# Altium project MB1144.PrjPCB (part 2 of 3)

## Sheet MCU2.SchDoc: MCU2
size A3; DocumentNumber: MB1144; Revision: C-02; SheetNumber: 4; SheetTotal: 25; PageSetup: Record=PageOptions|CenterHorizontal=True|CenterVertical=True|PrintScale=1.04|XCorrection=1.00|YCorrection=1.00|PrintKind=1|BorderSize=5000000|LeftOffset=0|BottomOffset=0|Orientation=2|PaperLength=1000|PaperWidth=1000|Scale=100|PaperSource=7|PrintQuality=600|MediaType=1|DitherType=10|PaperKind=A3|PrintScaleMode=1; Project: STM32L476G-EVAL

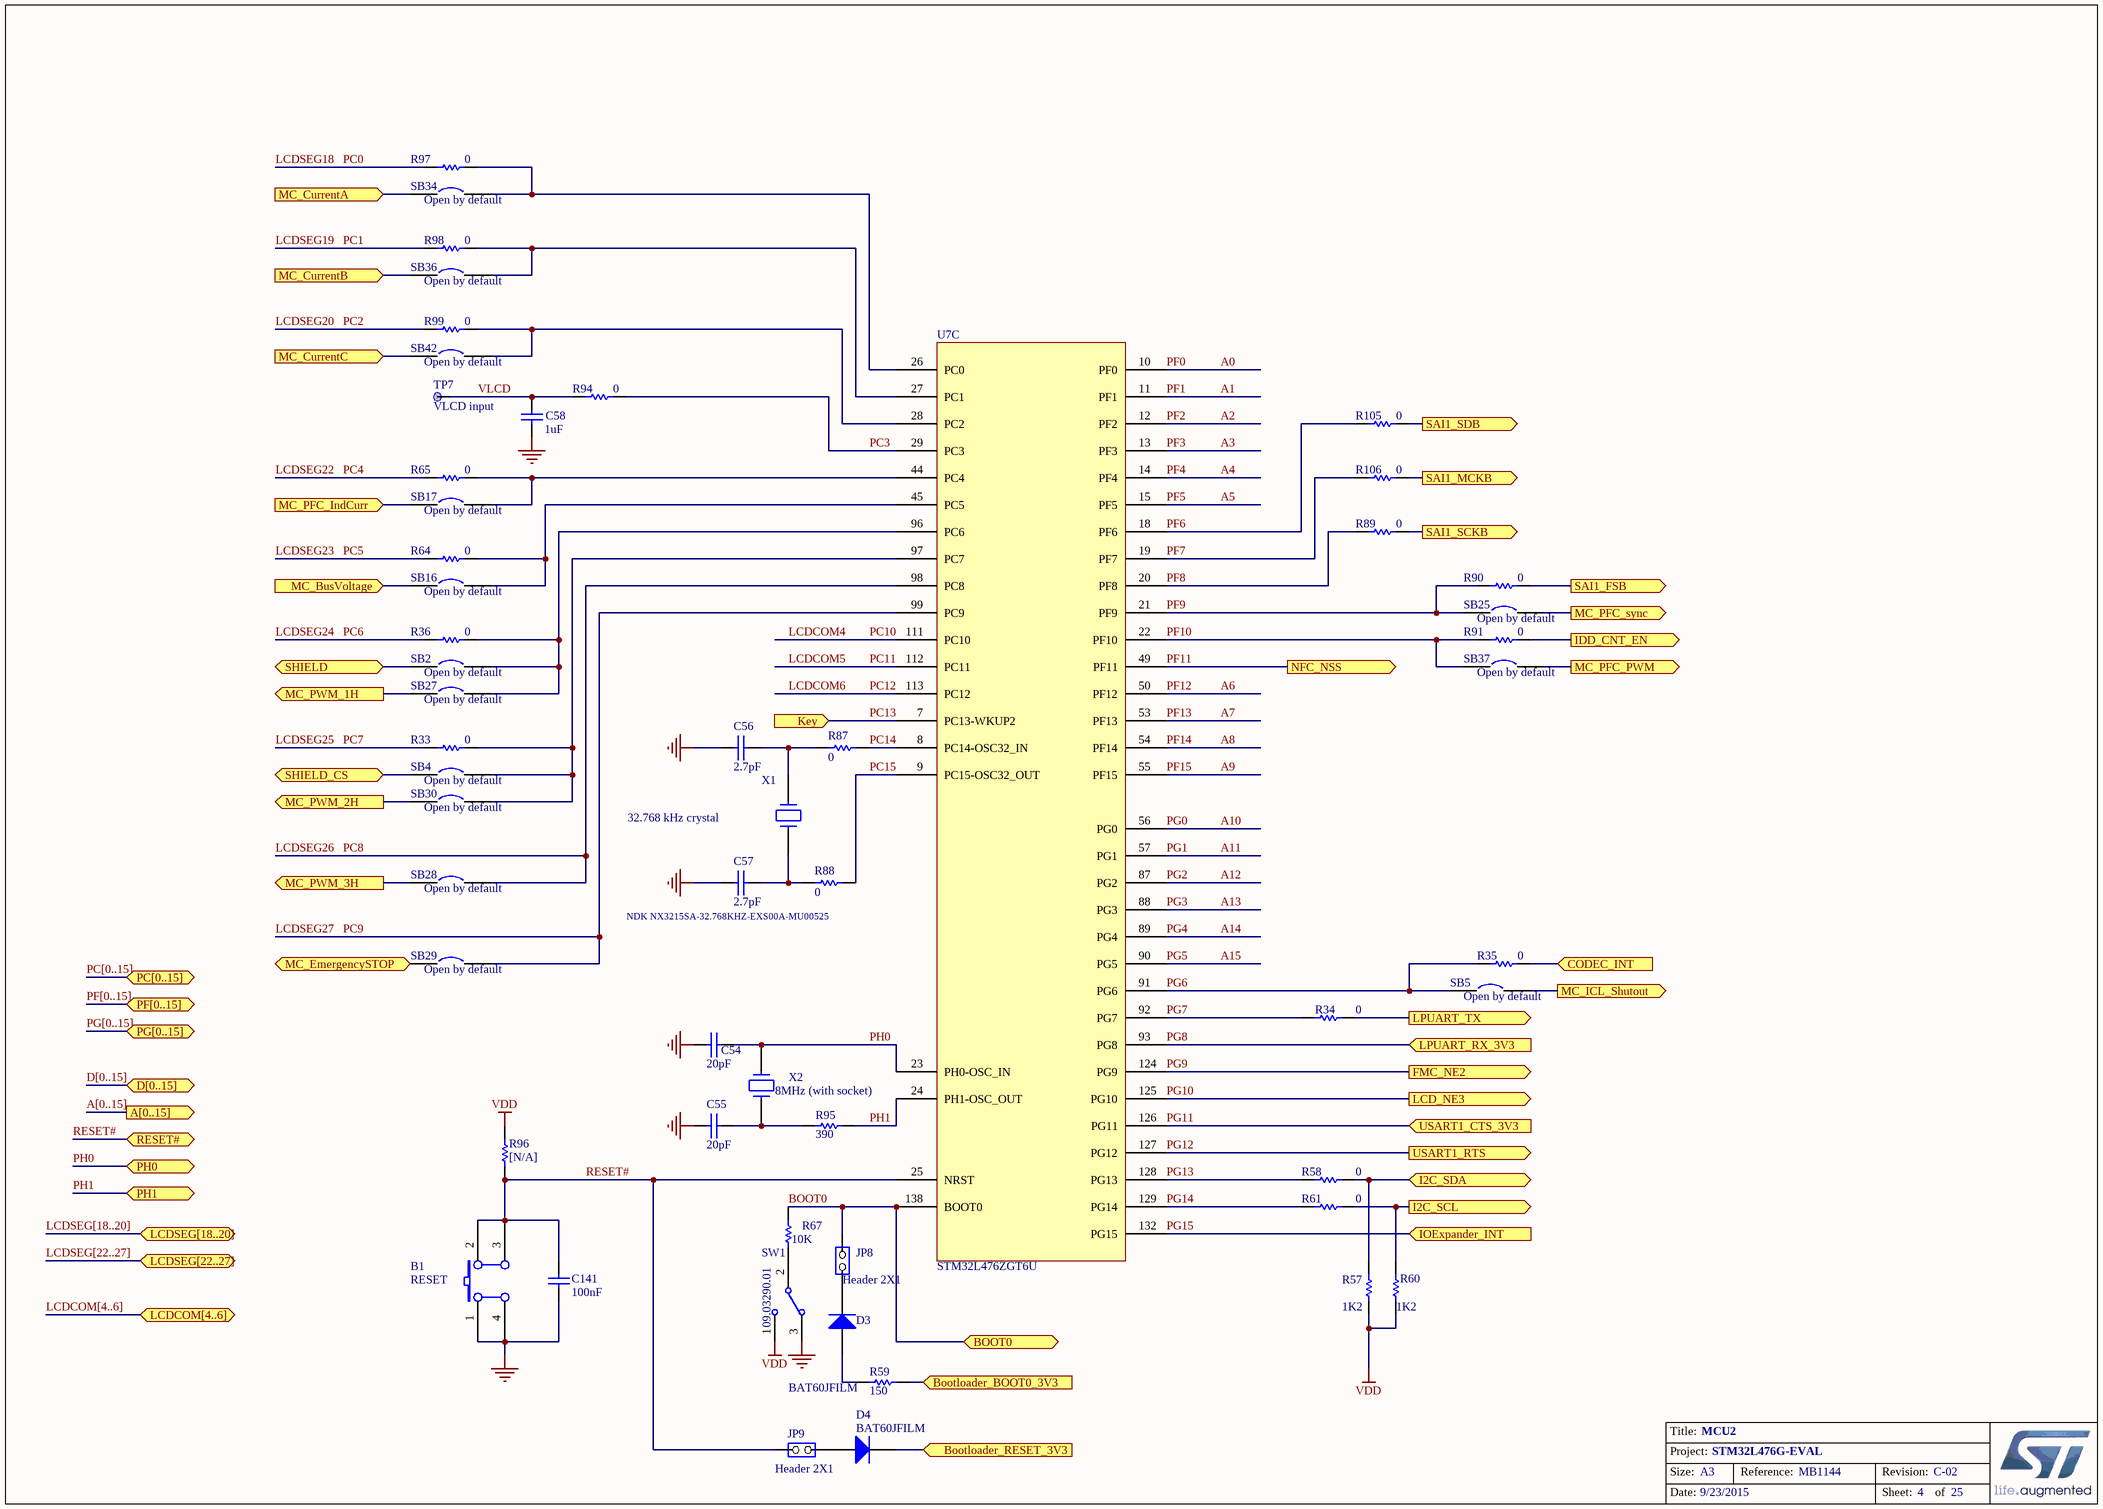
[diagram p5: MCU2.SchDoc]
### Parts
B1  RESET  [PB10]
C54  20pF  [0402R]
C55  20pF  [0402R]
C56  2.7pF  [0603C]
C57  2.7pF  [0603C]
C58  1uF  [0603C]
C141  100nF  [0402C]
D3  BAT60JFILM  [SOD-323]
D4  BAT60JFILM  [SOD-323]
JP8  Header 2X1  [SIP2]
JP9  Header 2X1  [SIP2]
R33  0  [SB_0603]
R34  0  [0603R]
R35  0  [SB_0603]
R36  0  [SB_0603]
R57  1K2  [0402R]
R58  0  [0603R]
R59  150  [0402R]
R60  1K2  [0402R]
R61  0  [0603R]
R64  0  [SB_0603]
R65  0  [SB_0603]
R67  10K  [0402R]
R87  0  [0603R]
R88  0  [0603R]
R89  0  [0603R]
R90  0  [SB_0603]
R91  0  [SB_0603]
R94  0  [0603R]
R95  390  [0603R]
R96  [N/A]  [0603R]
R97  0  [SB_0603]
R98  0  [SB_0603]
R99  0  [SB_0603]
R105  0  [0603R]
R106  0  [0603R]
SB2  Open by default  [SB_0603]
SB4  Open by default  [SB_0603]
SB5  Open by default  [SB_0603]
SB16  Open by default  [SB_0603]
SB17  Open by default  [SB_0603]
SB25  Open by default  [SB_0603]
SB27  Open by default  [SB_0603]
SB28  Open by default  [SB_0603]
SB29  Open by default  [SB_0603]
SB30  Open by default  [SB_0603]
SB34  Open by default  [SB_0603]
SB36  Open by default  [SB_0603]
SB37  Open by default  [SB_0603]
SB42  Open by default  [SB_0603]
SW1  09.03290.01  [SW1_3TH_2R54_10X2R5]
TP7  TP Name: VLCD input  [TP]  (hidden comment: [N/A])
U7  STM32L476ZGT6U  [TQFP144_0R5_22X22_SOCKET]  (part C of 3)
X1  NDK NX3215SA-32.768KHZ-EXS00A-MU00525  [XTAL_2SM_3R2X1R5]
X2  8MHz (with socket)  [XTAL_SOCKET]

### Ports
A[0..15] (out), BOOT0, Bootloader_BOOT0_3V3 (in), Bootloader_RESET_3V3 (in), CODEC_INT (in), D[0..15] (bidir), FMC_NE2 (out), I2C_SCL (out), I2C_SDA (bidir), IDD_CNT_EN (out), IOExpander_INT (in), Key (in), LCD_NE3 (out), LCDCOM[4..6] (bidir), LCDSEG[18..20] (bidir), LCDSEG[22..27] (bidir), LPUART_RX_3V3 (in), LPUART_TX (out), MC_BusVoltage (in), MC_CurrentA (in), MC_CurrentB (in), MC_CurrentC (in), MC_EmergencySTOP (in), MC_ICL_Shutout (out), MC_PFC_IndCurr (in), MC_PFC_PWM (out), MC_PFC_sync (out), MC_PWM_1H (out), MC_PWM_2H (out), MC_PWM_3H (out), NFC_NSS (out), PC[0..15] (bidir), PF[0..15] (bidir), PG[0..15] (bidir), PH0, PH1, RESET# (bidir), SAI1_FSB (out), SAI1_MCKB (out), SAI1_SCKB (out), SAI1_SDB (out), SHIELD, SHIELD_CS, USART1_CTS_3V3 (in), USART1_RTS (out)

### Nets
GND: B1.1(A0) B1.4(A1) C54.2 C55.2 C56.2 C57.2 C58.1 C141.1 SW1.3
VDD: R57.2 R60.2 R96.2 SW1.1
A0: U7.10(PF0)  [also labelled PF0]
A1: U7.11(PF1)  [also labelled PF1]
A2: U7.12(PF2)  [also labelled PF2]
A3: U7.13(PF3)  [also labelled PF3]
A4: U7.14(PF4)  [also labelled PF4]
A5: U7.15(PF5)  [also labelled PF5]
A6: U7.50(PF12)  [also labelled PF12]
A7: U7.53(PF13)  [also labelled PF13]
A8: U7.54(PF14)  [also labelled PF14]
A9: U7.55(PF15)  [also labelled PF15]
A10: U7.56(PG0)  [also labelled PG0]
A11: U7.57(PG1)  [also labelled PG1]
A12: U7.87(PG2)  [also labelled PG2]
A13: U7.88(PG3)  [also labelled PG3]
A14: U7.89(PG4)  [also labelled PG4]
A15: U7.90(PG5)  [also labelled PG5]
BOOT0: JP8.1(COMMON) R67.1 U7.138(BOOT0) ; port BOOT0
I2C_SCL: R60.1 R61.1 ; port I2C_SCL
I2C_SDA: R57.1 R58.1 ; port I2C_SDA
LCDCOM4: U7.111(PC10)  [also labelled PC10]
LCDCOM5: U7.112(PC11)  [also labelled PC11]
LCDCOM6: U7.113(PC12)  [also labelled PC12]
LCDSEG18: R97.1  [also labelled PC0]
LCDSEG19: R98.1  [also labelled PC1]
LCDSEG20: R99.1  [also labelled PC2]
LCDSEG22: R65.1  [also labelled PC4]
LCDSEG23: R64.1  [also labelled PC5]
LCDSEG24: R36.1  [also labelled PC6]
LCDSEG25: R33.1  [also labelled PC7]
LCDSEG26: SB28.2 U7.98(PC8)  [also labelled PC8]
LCDSEG27: SB29.2 U7.99(PC9)  [also labelled PC9]
PC3: R94.1 U7.29(PC3)
PC13: U7.7(PC13-WKUP2) ; port Key
PC14: R87.2 U7.8(PC14-OSC32_IN)
PC15: R88.2 U7.9(PC15-OSC32_OUT)
PF6: R105.2 U7.18(PF6)
PF7: R106.2 U7.19(PF7)
PF8: R89.2 U7.20(PF8)
PF9: R90.2 SB25.1 U7.21(PF9)
PF10: R91.2 SB37.1 U7.22(PF10)
PF11: U7.49(PF11) ; port NFC_NSS
PG6: R35.2 SB5.1 U7.91(PG6)
PG7: R34.2 U7.92(PG7)
PG8: U7.93(PG8) ; port LPUART_RX_3V3
PG9: U7.124(PG9) ; port FMC_NE2
PG10: U7.125(PG10) ; port LCD_NE3  [project net LCD_NE3]
PG11: U7.126(PG11) ; port USART1_CTS_3V3
PG12: U7.127(PG12) ; port USART1_RTS
PG13: R58.2 U7.128(PG13)
PG14: R61.2 U7.129(PG14)
PG15: U7.132(PG15) ; port IOExpander_INT
PH0: C54.1 U7.23(PH0-OSC_IN) X2.2 ; port PH0
PH1: R95.1 U7.24(PH1-OSC_OUT) ; port PH1
RESET#: B1.2(B0) B1.3(B1) C141.2 JP9.1(COMMON) R96.1 U7.25(NRST) ; port RESET#
VLCD: C58.2 R94.2 TP7.1
NetC3_1: SB17.1 ; port MC_PFC_IndCurr
NetC7_2: SB29.1 ; port MC_EmergencySTOP
NetC9_2: SB37.2 ; port MC_PFC_PWM
NetC10_2: SB42.1 ; port MC_CurrentC
NetC11_1: SB16.1 ; port MC_BusVoltage
NetC13_2: SB36.1 ; port MC_CurrentB
NetC14_2: SB34.1 ; port MC_CurrentA
NetC16_2: SB25.2 ; port MC_PFC_sync
NetC34_2: SB4.1 ; port SHIELD_CS
NetC55_1: C55.1 R95.2 X2.1
NetC56_1: C56.1 R87.1 X1.2
NetC57_1: C57.1 R88.1 X1.1
NetCN2_3: SB27.1 ; port MC_PWM_1H
NetCN2_7: SB30.1 ; port MC_PWM_2H
NetCN2_11: SB28.1 ; port MC_PWM_3H
NetCN2_21: SB5.2 ; port MC_ICL_Shutout
NetD3_1: D3.1(A) R59.1
NetD3_2: D3.2(K) JP8.2(NO)
NetD4_1: D4.1(A) JP9.2(NO)
NetD4_2: D4.2(K) ; port Bootloader_RESET_3V3
NetR33_2: R33.2 SB4.2 SB30.2 U7.97(PC7)
NetR34_1: R34.1 ; port LPUART_TX
NetR35_1: R35.1 ; port CODEC_INT
NetR36_2: R36.2 SB2.2 SB27.2 U7.96(PC6)
NetR37_1: SB2.1 ; port SHIELD
NetR59_2: R59.2 ; port Bootloader_BOOT0_3V3
NetR64_2: R64.2 SB16.2 U7.45(PC5)
NetR65_2: R65.2 SB17.2 U7.44(PC4)
NetR67_2: R67.2 SW1.2
NetR89_1: R89.1 ; port SAI1_SCKB
NetR90_1: R90.1 ; port SAI1_FSB
NetR91_1: R91.1 ; port IDD_CNT_EN
NetR97_2: R97.2 SB34.2 U7.26(PC0)
NetR98_2: R98.2 SB36.2 U7.27(PC1)
NetR99_2: R99.2 SB42.2 U7.28(PC2)
NetR105_1: R105.1 ; port SAI1_SDB
NetR106_1: R106.1 ; port SAI1_MCKB

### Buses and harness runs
bus A[0..15] = port A[0..15]
bus D[0..15] = port D[0..15]
bus LCDCOM[4..6] = port LCDCOM[4..6]
bus LCDSEG[18..20] = port LCDSEG[18..20]
bus LCDSEG[22..27] = port LCDSEG[22..27]
bus PC[0..15] = port PC[0..15]
bus PF[0..15] = port PF[0..15]
bus PG[0..15] = port PG[0..15]

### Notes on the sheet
- 32.768 kHz crystal

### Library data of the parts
B1 = SW PUSHBUTTON: SE PUSHBUTTON; Ordered by: Subcon; Comments: no comment; Assembly: Black; ECCN_US/EU: NA
C54-C57 = CAP: Capacitor; Ordered by: Subcon; ECCN_US/EU: NA
C58 = CAP: Capacitor; Value: 100nF; Ordered by: Subcon; ECCN_US/EU: NA
C141 = CAP: Capacitor; Value: 100pF; Ordered by: Subcon; ECCN_US/EU: NA
D3 D4 = Diode: Default Diode; Code - JEDEC: DO-214-AB; Ordered by: ST; ECCN_US/EU: EAR99/NEC; Ref St: 9151097
JP8 JP9 = JP2: Ordered by: Subcon; ECCN_US/EU: NA
R33 R34 R36 R57 R58 R60 R61 R64 R65 R87 R88 R95 R97-R99 = Res1: Resistor; Value: 1K; Ordered by: Subcon; ECCN_US/EU: NA
R35 R59 R67 R89-R91 R94 R105 R106 = res1: Resistor; Value: 1K; Ordered by: Subcon; ECCN_US/EU: NA
R96 = res1: Resistor; Value: 1K; Ordered by: Subcon; ECCN_US/EU: NA; Fitted: NO
SB2 SB4 SB5 SB16 SB17 SB25 SB27-SB30 SB34 SB36 SB37 SB42 = Circuit Breaker: Ordered by: Subcon; Comments: Solder bridge; Fitted: NO; ECCN_US/EU: NA
SW1 = SW-SPDT: SPDT Subminiature Toggle Switch, Right Angle Mounting, Vertical Actuation; Revision 1: Jul-2002: Re-released for DXP Platform.; Revision 2: 17-Dec-2003: Schematic revised, PCB Footprint replaced.; Ordered by: Subcon; ECCN_US/EU: NA
TP7 = TP: Ordered by: Subcon; Fitted or not fitted: NO; ECCN_US/EU: NA; Fitted: NO
U7 = STM32L476_TQFP144: Manuf_Part_1: STM32L476ZGT6U cut1.3; Ordered by: ST; ECCN_US/EU: 3A991A2/NEC; Assembly: MCU; Ref St: 9175195
X1 = CRYSTAL_32K: Crystal; Ordered by: ST; ECCN_US/EU: NA
X2 = CRYSTAL: Manuf_1: jfvny; Manuf_Part_1: HC-49S-C16QSA-8M; Ordered by: Subcon; ECCN_US/EU: NA

## Sheet SRAM&Flash.SchDoc: SRAM&Flash
size A3; DocumentNumber: MB1144; Revision: C-02; SheetNumber: 10; SheetTotal: 25; Project: STM32L476G-EVAL

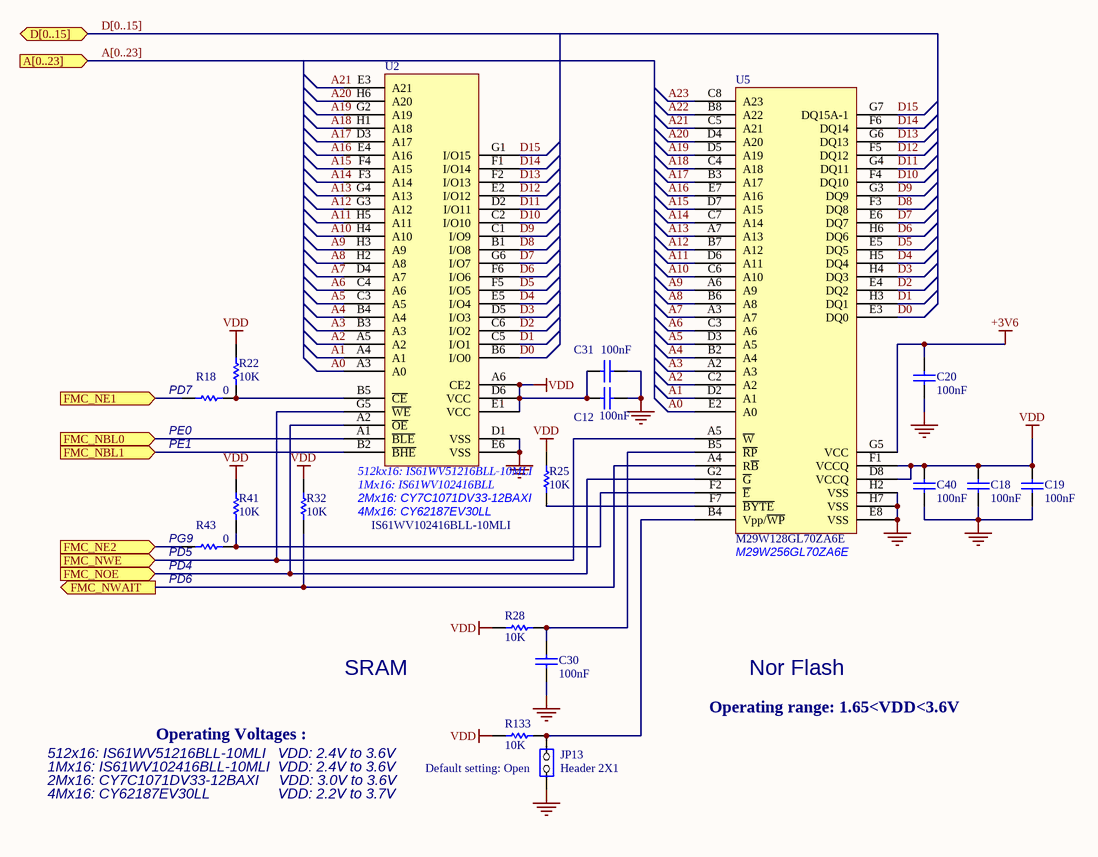
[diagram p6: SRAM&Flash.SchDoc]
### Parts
C12  100nF  [0402C]
C18  100nF  [0402C]
C19  100nF  [0402C]
C20  100nF  [0402C]
C30  100nF  [0402C]
C31  100nF  [0402C]
C40  100nF  [0402C]
JP13  Header 2X1  [SIP2]
R18  0  [0603R]
R22  10K  [0402R]
R25  10K  [0402R]
R28  10K  [0402R]
R32  10K  [0402R]
R41  10K  [0402R]
R43  0  [0603R]
R133  10K  [0402R]
U2  IS61WV102416BLL-10MLI  [BGA48_0R75_9X11]
U5  M29W128GL70ZA6E  [BGA64_1_10X13]

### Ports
A[0..23] (in), D[0..15] (bidir), FMC_NBL0 (in), FMC_NBL1 (in), FMC_NE1 (in), FMC_NE2 (in), FMC_NOE (in), FMC_NWAIT (out), FMC_NWE (in)

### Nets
+3V6: C20.1 U5.G5(VCC)
GND: C12.2 C18.2 C19.2 C20.2 C30.2 C31.2 C40.2 JP13.1(COMMON) U2.D1(VSS) U2.E6(VSS) U5.E8(VSS) U5.H2(VSS) U5.H7(VSS)
VDD: C12.1 C18.1 C19.1 C31.1 C40.1 R22.1 R25.1 R28.1 R32.1 R41.1 R133.1 U2.A6(CE2) U2.D6(VCC) U2.E1(VCC) U5.D8(VCCQ) U5.F1(VCCQ)
A0: U2.A3(A0) U5.E2(A0)
A1: U2.A4(A1) U5.D2(A1)
A2: U2.A5(A2) U5.C2(A2)
A3: U2.B3(A3) U5.A2(A3)
A4: U2.B4(A4) U5.B2(A4)
A5: U2.C3(A5) U5.D3(A5)
A6: U2.C4(A6) U5.C3(A6)
A7: U2.D4(A7) U5.A3(A7)
A8: U2.H2(A8) U5.B6(A8)
A9: U2.H3(A9) U5.A6(A9)
A10: U2.H4(A10) U5.C6(A10)
A11: U2.H5(A11) U5.D6(A11)
A12: U2.G3(A12) U5.B7(A12)
A13: U2.G4(A13) U5.A7(A13)
A14: U2.F3(A14) U5.C7(A14)
A15: U2.F4(A15) U5.D7(A15)
A16: U2.E4(A16) U5.E7(A16)
A17: U2.D3(A17) U5.B3(A17)
A18: U2.H1(A18) U5.C4(A18)
A19: U2.G2(A19) U5.D5(A19)
A20: U2.H6(A20) U5.D4(A20)
A21: U2.E3(A21) U5.C5(A21)
A22: U5.B8(A22)
A23: U5.C8(A23)
D0: U2.B6(I/O0) U5.E3(DQ0)
D1: U2.C5(I/O1) U5.H3(DQ1)
D2: U2.C6(I/O2) U5.E4(DQ2)
D3: U2.D5(I/O3) U5.H4(DQ3)
D4: U2.E5(I/O4) U5.H5(DQ4)
D5: U2.F5(I/O5) U5.E5(DQ5)
D6: U2.F6(I/O6) U5.H6(DQ6)
D7: U2.G6(I/O7) U5.E6(DQ7)
D8: U2.B1(I/O8) U5.F3(DQ8)
D9: U2.C1(I/O9) U5.G3(DQ9)
D10: U2.C2(I/O10) U5.F4(DQ10)
D11: U2.D2(I/O11) U5.G4(DQ11)
D12: U2.E2(I/O12) U5.F5(DQ12)
D13: U2.F2(I/O13) U5.G6(DQ13)
D14: U2.F1(I/O14) U5.F6(DQ14)
D15: U2.G1(I/O15) U5.G7(DQ15A-1)
PD4: U2.A2(~{OE}) U5.G2(~{G}) ; port FMC_NOE
PD5: U2.G5(~{WE}) U5.A5(~{W}) ; port FMC_NWE
PD7: R18.2 ; port FMC_NE1
PG9: R43.2 ; port FMC_NE2
NetC30_1: C30.1 R28.2 U5.B5(~{RP})
NetCN14_40: U2.A1(~{BLE}) ; port FMC_NBL0
NetCN14_42: U2.B2(~{BHE}) ; port FMC_NBL1
NetJP13_2: JP13.2(NO) R133.2 U5.B4(Vpp/~{WP})
NetR18_1: R18.1 R22.2 U2.B5(~{CE})
NetR25_2: R25.2 U5.F7(~{BYTE})
NetR32_2: R32.2 U5.A4(R~{B}) ; port FMC_NWAIT
NetR41_2: R41.2 R43.1 U5.F2(~{E})

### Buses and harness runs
bus A[0..23] = port A[0..23]
bus D[0..15] = port D[0..15]

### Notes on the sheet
- (near R18) PE0
- (near R18) PD7
- PE1
- 2Mx16: CY7C1071DV33-12BAXI
- 512kx16: IS61WV51216BLL-10MLI
- (near U2) 1Mx16: IS61WV102416BLL
- (near R43) PD5
- (near R43) PG9
- (near R43) PD4
- 4Mx16: CY62187EV30LL
- (near U5) M29W256GL70ZA6E
- (near R43) PD6
- SRAM
- Nor Flash
- 512x16: IS61WV51216BLL-10MLI   VDD: 2.4V to 3.6V
- 1Mx16: IS61WV102416BLL-10MLI  VDD: 2.4V to 3.6V
- Operating Voltages :
- (near JP13) Default setting: Open
- Operating range: 1.65<VDD<3.6V
- 2Mx16: CY7C1071DV33-12BAXI     VDD: 3.0V to 3.6V
- 4Mx16: CY62187EV30LL                 VDD: 2.2V to 3.7V

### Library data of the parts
C12 C18-C20 C30 C31 C40 = Cap: Capacitor; Value: 10nF; Ordered by: Subcon; ECCN_US/EU: NA
JP13 = JP2: Ordered by: Subcon; ECCN_US/EU: NA
R18 R43 = Res1: as R33 on sheet MCU2
R22 R25 R28 R32 R41 R133 = res1: as R35 on sheet MCU2
U2 = SRAM_4Mx16: Manuf_1: ISSI; Manuf_Part_1: IS61WV102416ALL; Comments: 1Mx16 ISSI SRAM; Ordered by: Subcon; ECCN_US/EU: EAR99/NEC
U5 = M29W128FL70ZA6E: Manuf_1: Micron; Ordered by: Subcon; ECCN_US/EU: 3A991

## Sheet MotorControl.SchDoc: MotorControl
size A4; DocumentNumber: MB1144; Revision: C-02; SheetNumber: 23; SheetTotal: 25; Project: STM32L476G-EVAL

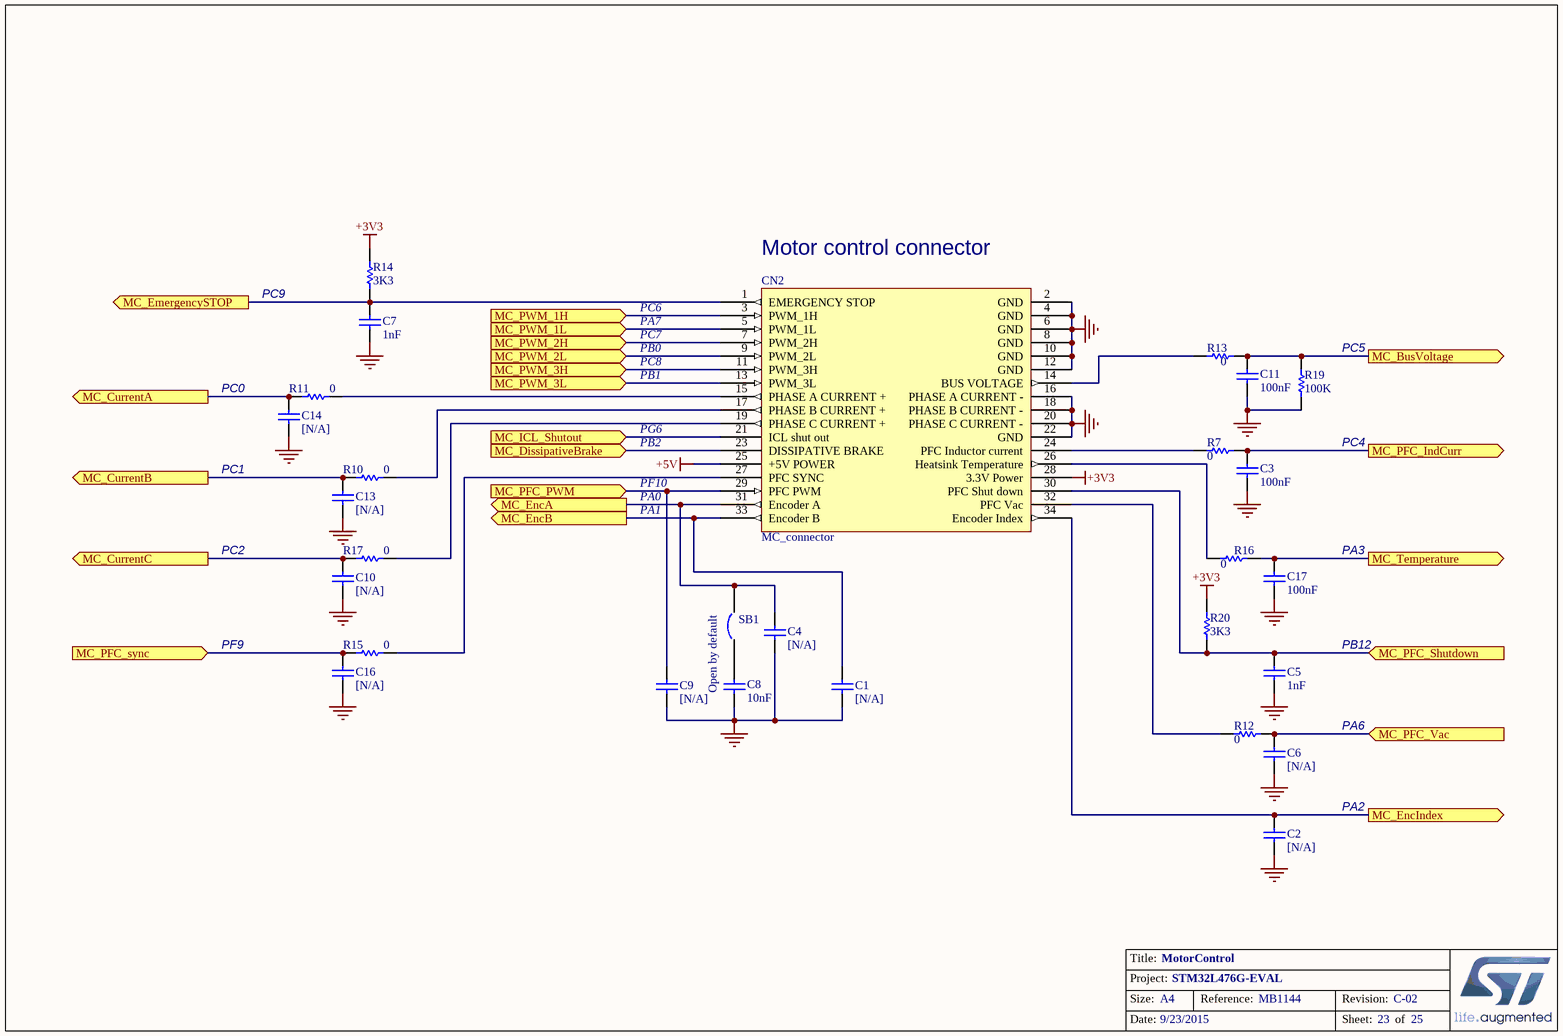
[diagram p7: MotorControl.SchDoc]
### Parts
C1  [N/A]  [0603C]
C2  [N/A]  [0603C]
C3  100nF  [0402C]
C4  [N/A]  [0603C]
C5  1nF  [0402C]
C6  [N/A]  [0603C]
C7  1nF  [0402C]
C8  10nF  [0402C]
C9  [N/A]  [0603C]
C10  [N/A]  [0603C]
C11  100nF  [0402C]
C13  [N/A]  [0603C]
C14  [N/A]  [0603C]
C16  [N/A]  [0603C]
C17  100nF  [0402C]
CN2  MC_connector  [IDC34S]
R7  0  [0603R]
R10  0  [0603R]
R11  0  [0603R]
R12  0  [0603R]
R13  0  [0603R]
R14  3K3  [0402R]
R15  0  [0603R]
R16  0  [0603R]
R17  0  [0603R]
R19  100K  [0402R]
R20  3K3  [0402R]
SB1  Open by default  [SB_0603]

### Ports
MC_BusVoltage (out), MC_CurrentA (out), MC_CurrentB (out), MC_CurrentC (out), MC_DissipativeBrake (in), MC_EmergencySTOP (out), MC_EncA (out), MC_EncB (out), MC_EncIndex (out), MC_ICL_Shutout (in), MC_PFC_IndCurr (out), MC_PFC_PWM (in), MC_PFC_Shutdown (in), MC_PFC_sync (in), MC_PFC_Vac (in), MC_PWM_1H (in), MC_PWM_1L (in), MC_PWM_2H (in), MC_PWM_2L (in), MC_PWM_3H (in), MC_PWM_3L (in), MC_Temperature (out)

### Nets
+3V3: CN2.28(3.3V_Power) R14.2 R20.2
+5V: CN2.25(+5V_POWER)
GND: C1.1 C2.1 C3.2 C4.1 C5.1 C6.1 C7.1 C8.2 C9.1 C10.1 C11.2 C13.1 C14.1 C16.1 C17.2 CN2.2(GND) CN2.4(GND) CN2.6(GND) CN2.8(GND) CN2.10(GND) CN2.12(GND) CN2.16(PHASE_A_CURRENT_-) CN2.18(PHASE_B_CURRENT_-) CN2.20(PHASE_C_CURRENT_-) CN2.22(GND) R19.2
NetC1_2: C1.2 CN2.33(Encoder_B) ; port MC_EncB
NetC2_2: C2.2 CN2.34(Encoder_Index) ; port MC_EncIndex
NetC3_1: C3.1 R7.2 ; port MC_PFC_IndCurr
NetC4_2: C4.2 CN2.31(Encoder_A) SB1.2 ; port MC_EncA
NetC5_2: C5.2 CN2.30(PFC_Shut_down) R20.1 ; port MC_PFC_Shutdown
NetC6_2: C6.2 R12.2 ; port MC_PFC_Vac
NetC7_2: C7.2 CN2.1(EMERGENCY_STOP) R14.1 ; port MC_EmergencySTOP
NetC8_1: C8.1 SB1.1
NetC9_2: C9.2 CN2.29(PFC_PWM) ; port MC_PFC_PWM
NetC10_2: C10.2 R17.1 ; port MC_CurrentC
NetC11_1: C11.1 R13.2 R19.1 ; port MC_BusVoltage
NetC13_2: C13.2 R10.1 ; port MC_CurrentB
NetC14_2: C14.2 R11.1 ; port MC_CurrentA
NetC16_2: C16.2 R15.1 ; port MC_PFC_sync
NetC17_1: C17.1 R16.2 ; port MC_Temperature
NetCN2_3: CN2.3(PWM_1H) ; port MC_PWM_1H
NetCN2_5: CN2.5(PWM_1L) ; port MC_PWM_1L
NetCN2_7: CN2.7(PWM_2H) ; port MC_PWM_2H
NetCN2_9: CN2.9(PWM_2L) ; port MC_PWM_2L
NetCN2_11: CN2.11(PWM_3H) ; port MC_PWM_3H
NetCN2_13: CN2.13(PWM_3L) ; port MC_PWM_3L
NetCN2_14: CN2.14(BUS_VOLTAGE) R13.1
NetCN2_15: CN2.15(PHASE_A_CURRENT_+) R11.2
NetCN2_17: CN2.17(PHASE_B_CURRENT_+) R10.2
NetCN2_19: CN2.19(PHASE_C_CURRENT_+) R17.2
NetCN2_21: CN2.21(ICL_shut_out) ; port MC_ICL_Shutout
NetCN2_23: CN2.23(DISSIPATIVE_BRAKE) ; port MC_DissipativeBrake
NetCN2_24: CN2.24(PFC_Inductor_current) R7.1
NetCN2_26: CN2.26(Heatsink_Temperature) R16.1
NetCN2_27: CN2.27(PFC_SYNC) R15.2
NetCN2_32: CN2.32(PFC_Vac) R12.1

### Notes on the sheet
- PC9
- PC6
- (near CN2) Motor control connector
- PA7
- PB0
- PB1
- PC7
- PC8
- (near R19) PC5
- PC0
- PG6
- PB2
- PC4
- PC1
- PA1
- PA0
- PF10
- PC2
- PA3
- PF9
- PB12
- PA6
- PA2

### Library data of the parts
C1 C2 C4 C6 C9 C10 C13 C14 C16 = cap: Capacitor; Value: 100pF; Ordered by: Subcon; ECCN_US/EU: NA; Fitted: NO
C3 C11 C17 = Cap: as C12 on sheet SRAM&Flash
C5 C7 C8 = CAP: as C141 on sheet MCU2
CN2 = MC_connector_1: Ordered by: Subcon; Comments: Motor Control conn.; ECCN_US/EU: NA
R7 R10-R17 R20 = Res1: as R33 on sheet MCU2
R19 = res1: as R35 on sheet MCU2
SB1 = Circuit Breaker: as SB2 on sheet MCU2

## Sheet MicroSD.SchDoc: MicroSD
size A4; DocumentNumber: MB1144; Revision: C-02; SheetNumber: 14; SheetTotal: 25; Project: STM32L476G-EVAL

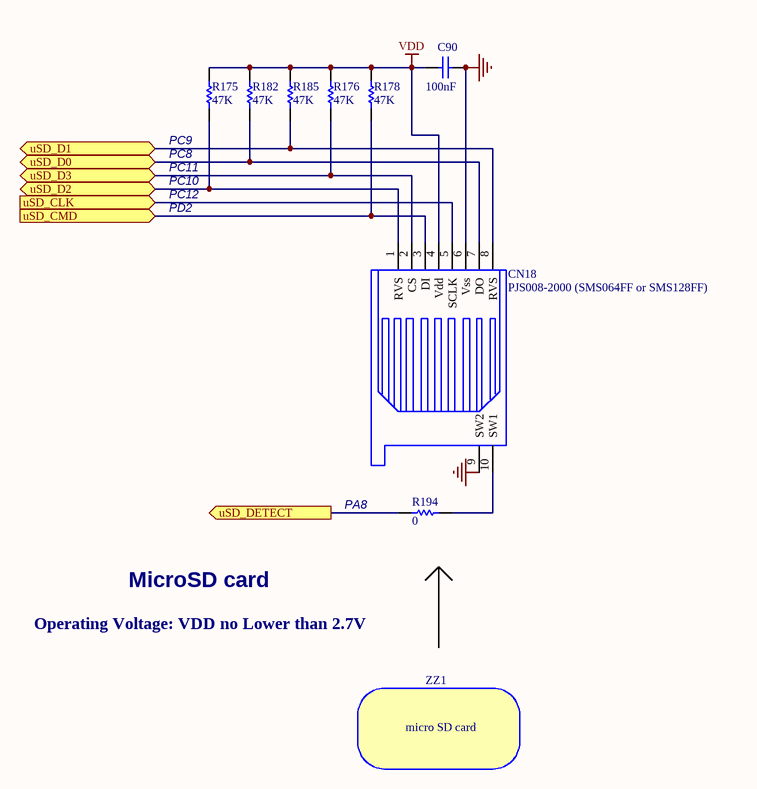
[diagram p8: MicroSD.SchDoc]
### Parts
C90  100nF  [0402C]
CN18  PJS008-2000 (SMS064FF or SMS128FF)  [MSD_PJS008_]
R175  47K  [0402R]
R176  47K  [0402R]
R178  47K  [0402R]
R182  47K  [0402R]
R185  47K  [0402R]
R194  0  [0603R]
ZZ1  micro SD card

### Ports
uSD_CLK (in), uSD_CMD (in), uSD_D0 (bidir), uSD_D1 (bidir), uSD_D2 (bidir), uSD_D3 (bidir), uSD_DETECT (out)

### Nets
GND: C90.2 CN18.6(Vss) CN18.9(SW2)
VDD: C90.1 CN18.4(Vdd) R175.1 R176.1 R178.1 R182.1 R185.1
NetCN11_4: R194.1 ; port uSD_DETECT
NetCN14_2: CN18.3(DI) R178.2 ; port uSD_CMD
NetCN18_1: CN18.1(RVS) R175.2 ; port uSD_D2
NetCN18_2: CN18.2(CS) R176.2 ; port uSD_D3
NetCN18_5: CN18.5(SCLK) ; port uSD_CLK
NetCN18_7: CN18.7(DO) R182.2 ; port uSD_D0
NetCN18_8: CN18.8(RVS) R185.2 ; port uSD_D1
NetCN18_10: CN18.10(SW1) R194.2

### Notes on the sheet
- (near R175) PC9
- (near R175) PC8
- PC10
- PC11
- PC12
- PD2
- PA8
- MicroSD card
- Operating Voltage: VDD no Lower than 2.7V

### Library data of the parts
C90 = CAP: as C141 on sheet MCU2
CN18 = SMS016AFA5E: ECCN_US/EU: NA; Ordered by: Subcon; Assembly: with SD card; Comments: Micro SD card connector
R175 R176 R178 R182 R185 R194 = Res1: as R33 on sheet MCU2
ZZ1 = BoM_Item: 4GB or more; Ordered by: Subcon; Assembly: to plug in CN18

## Sheet QSPI.SchDoc: QSPI
size A4; DocumentNumber: MB1144; Revision: C-02; SheetNumber: 13; SheetTotal: 25; Project: STM32L476G-EVAL

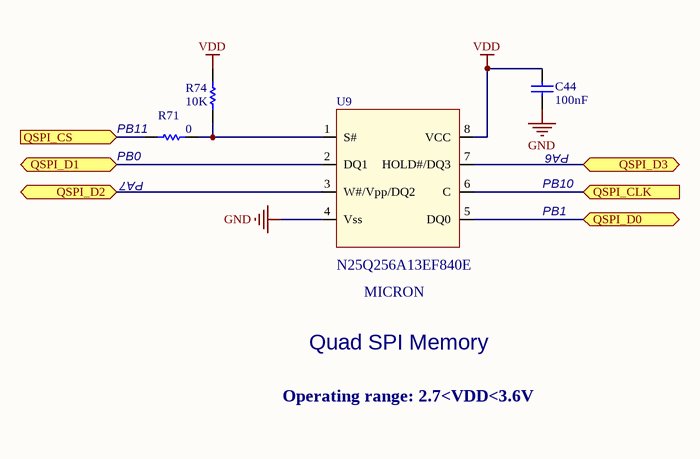
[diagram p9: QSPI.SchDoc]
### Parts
C44  100nF  [0402C]
R71  0  [0603R]
R74  10K  [0402R]
U9  N25Q256A13EF840E  [DFN8_1R27_6X8_TP4R8X5R8]

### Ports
QSPI_CLK (in), QSPI_CS (in), QSPI_D0 (bidir), QSPI_D1 (bidir), QSPI_D2 (bidir), QSPI_D3 (bidir)

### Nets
GND: C44.2 U9.4(Vss)
VDD: C44.1 R74.1 U9.8(VCC)
NetR71_1: R71.1 R74.2 U9.1(S#)
NetR71_2: R71.2 ; port QSPI_CS
NetSB9_1: U9.6(C) ; port QSPI_CLK
NetSB12_1: U9.5(DQ0) ; port QSPI_D0
NetSB14_1: U9.2(DQ1) ; port QSPI_D1
NetSB18_1: U9.3(W#/Vpp/DQ2) ; port QSPI_D2
NetSB21_1: U9.7(HOLD#/DQ3) ; port QSPI_D3

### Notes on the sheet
- (near R71) PB0
- (near R71) PB11
- PA6
- (near R71) PA7
- PB1
- PB10
- MICRON
- Quad SPI Memory
- Operating range: 2.7<VDD<3.6V

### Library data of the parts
C44 = Cap: as C12 on sheet SRAM&Flash
R71 = Res1: as R33 on sheet MCU2
R74 = res1: as R35 on sheet MCU2
U9 = QSPI_8pins: Manuf_1: Micron; ECCN_US/EU: 3A991; Ordered by: Subcon

## Sheet Extension connector.SCHDOC: Extension connector
size A3; DocumentNumber: MB1144; Revision: C-02; SheetNumber: 12; SheetTotal: 25; Project: STM32L476G-EVAL

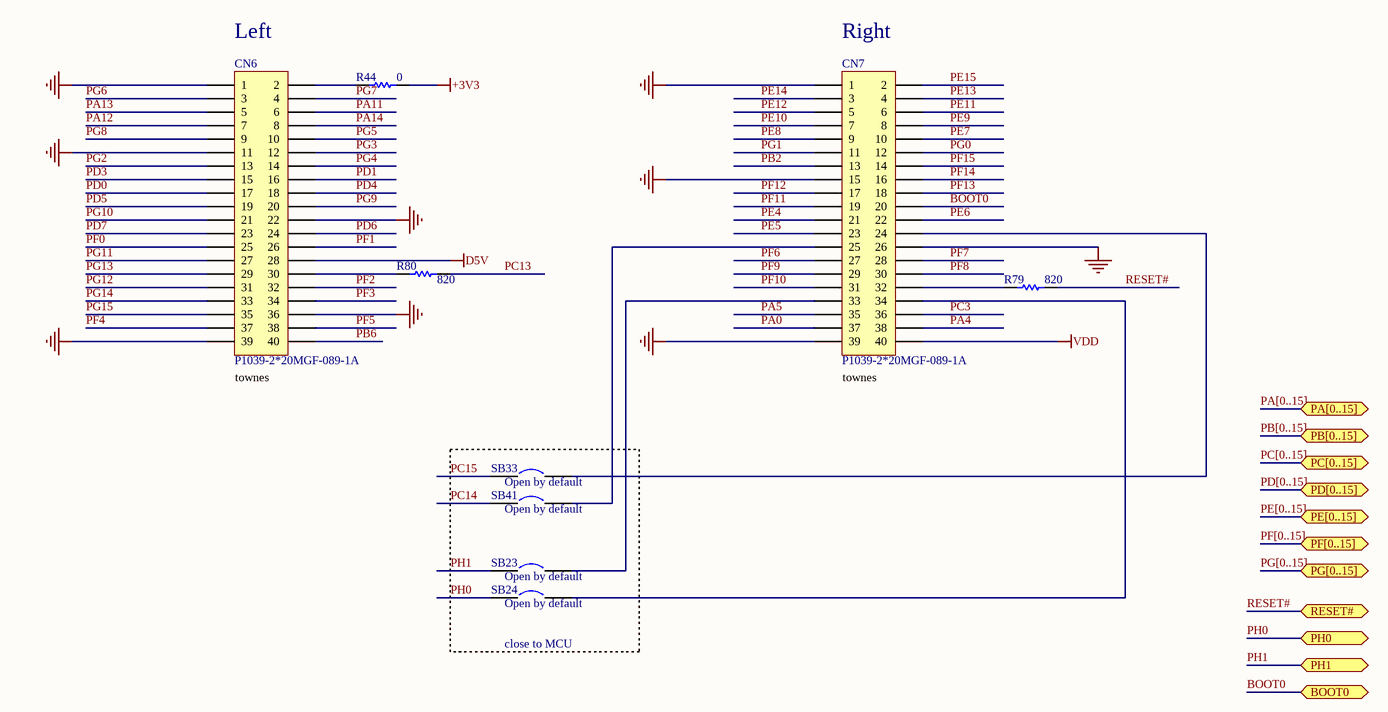
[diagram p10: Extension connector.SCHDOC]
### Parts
CN6  P1039-2*20MGF-089-1A  [FTR-120-53-L-D-LC]
CN7  P1039-2*20MGF-089-1A  [FTR-120-53-L-D-LC]
R44  0  [0603R]
R79  820  [0402R]
R80  820  [0402R]
SB23  Open by default  [SB_0603]
SB24  Open by default  [SB_0603]
SB33  Open by default  [SB_0603]
SB41  Open by default  [SB_0603]

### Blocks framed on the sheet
close to MCU: SB23 SB24 SB33 SB41

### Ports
BOOT0, PA[0..15] (bidir), PB[0..15] (bidir), PC[0..15] (bidir), PD[0..15] (bidir), PE[0..15] (bidir), PF[0..15] (bidir), PG[0..15] (bidir), PH0, PH1, RESET# (bidir)

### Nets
+3V3: R44.1
D5V: CN6.28
GND: CN6.1 CN6.11 CN6.22 CN6.36 CN6.39 CN7.1 CN7.15 CN7.26 CN7.39
VDD: CN7.40
BOOT0: CN7.20 ; port BOOT0
PA0: CN7.37
PA4: CN7.38
PA5: CN7.35
PA11: CN6.6
PA12: CN6.7
PA13: CN6.5
PA14: CN6.8
PB2: CN7.13
PB6: CN6.40
PC3: CN7.36
PC13: R80.2
PC14: SB41.1
PC15: SB33.1
PD0: CN6.17  [project net D2]
PD1: CN6.16  [project net D3]
PD3: CN6.15
PD4: CN6.18
PD5: CN6.19
PD6: CN6.24
PD7: CN6.23
PE4: CN7.21
PE5: CN7.23
PE6: CN7.22
PE7: CN7.10  [project net D4]
PE8: CN7.9  [project net D5]
PE9: CN7.8  [project net D6]
PE10: CN7.7  [project net D7]
PE11: CN7.6  [project net D8]
PE12: CN7.5  [project net D9]
PE13: CN7.4  [project net D10]
PE14: CN7.3  [project net D11]
PE15: CN7.2  [project net D12]
PF0: CN6.25  [project net A0]
PF1: CN6.26  [project net A1]
PF2: CN6.32  [project net A2]
PF3: CN6.34  [project net A3]
PF4: CN6.37  [project net A4]
PF5: CN6.38  [project net A5]
PF6: CN7.27
PF7: CN7.28
PF8: CN7.30
PF9: CN7.29
PF10: CN7.31
PF11: CN7.19
PF12: CN7.17  [project net A6]
PF13: CN7.18  [project net A7]
PF14: CN7.16  [project net A8]
PF15: CN7.14  [project net A9]
PG0: CN7.12  [project net A10]
PG1: CN7.11  [project net A11]
PG2: CN6.13  [project net A12]
PG3: CN6.12  [project net A13]
PG4: CN6.14  [project net A14]
PG5: CN6.10  [project net A15]
PG6: CN6.3
PG7: CN6.4
PG8: CN6.9
PG9: CN6.20
PG10: CN6.21  [project net LCD_NE3]
PG11: CN6.27
PG12: CN6.31
PG13: CN6.29
PG14: CN6.33
PG15: CN6.35
PH0: SB24.1 ; port PH0
PH1: SB23.1 ; port PH1
RESET#: R79.1 ; port RESET#
NetCN6_2: CN6.2 R44.2
NetCN6_30: CN6.30 R80.1
NetCN7_24: CN7.24 SB33.2
NetCN7_25: CN7.25 SB41.2
NetCN7_32: CN7.32 R79.2
NetCN7_33: CN7.33 SB23.2
NetCN7_34: CN7.34 SB24.2

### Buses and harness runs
bus PA[0..15] = port PA[0..15]
bus PB[0..15] = port PB[0..15]
bus PC[0..15] = port PC[0..15]
bus PD[0..15] = port PD[0..15]
bus PE[0..15] = port PE[0..15]
bus PF[0..15] = port PF[0..15]
bus PG[0..15] = port PG[0..15]

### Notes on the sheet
- (near CN6) Left
- (near CN7) Right
- (near CN6) townes
- (near CN7) townes

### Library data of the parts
CN6 CN7 = FTR-120-53-L-D-LC: Header, 20-Pin, Dual row; Ordered by: Subcon; Comments: extension connector; ECCN_US/EU: NA
R44 R79 R80 = Res1: as R33 on sheet MCU2
SB23 SB24 SB33 SB41 = Circuit Breaker: as SB2 on sheet MCU2

## Sheet JTAG&Trace.SchDoc: JTAG&Trace
size A3; DocumentNumber: MB1144; Revision: C-02; SheetNumber: 24; SheetTotal: 25; Project: STM32L476G-EVAL

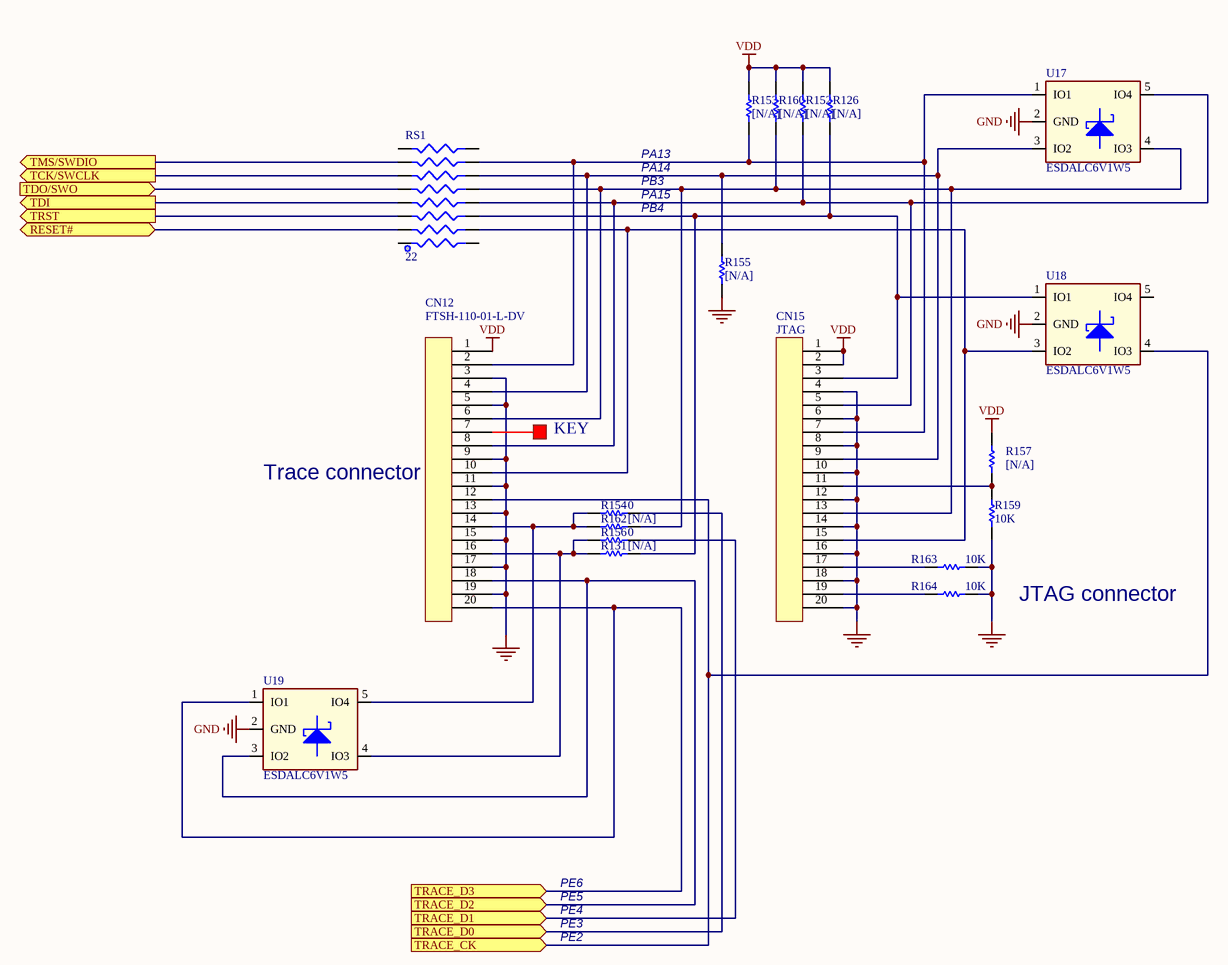
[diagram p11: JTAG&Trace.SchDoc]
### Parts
CN12  FTSH-110-01-L-DV  [FTSH-110-01-L-DV]
CN15  JTAG  [IDC20S]
R126  [N/A]  [0603R]
R131  [N/A]  [0603R]
R152  [N/A]  [0603R]
R153  [N/A]  [0603R]
R154  0  [0603R]
R155  [N/A]  [0603R]
R156  0  [0603R]
R157  [N/A]  [0603R]
R159  10K  [0402R]
R160  [N/A]  [0603R]
R162  [N/A]  [0603R]
R163  10K  [0402R]
R164  10K  [0402R]
RS1  22  [RP0402X8_REV]
U17  ESDALC6V1W5  [SOT-353]
U18  ESDALC6V1W5  [SOT-353]
U19  ESDALC6V1W5  [SOT-353]

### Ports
RESET# (bidir), TCK/SWCLK (out), TDI (out), TDO/SWO (in), TMS/SWDIO (out), TRACE_CK (in), TRACE_D0 (in), TRACE_D1 (in), TRACE_D2 (in), TRACE_D3 (in), TRST (out)

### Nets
GND: CN12.3 CN12.5 CN12.9 CN12.11 CN12.13 CN12.15 CN12.17 CN12.19 CN15.4 CN15.6 CN15.8 CN15.10 CN15.12 CN15.14 CN15.16 CN15.18 CN15.20 R155.1 R159.1 R163.1 R164.1 U17.2(GND) U18.2(GND) U19.2(GND)
VDD: CN12.1 CN15.1 CN15.2 R126.2 R152.2 R153.2 R157.2 R160.2
LCDSEG7: RS1.9 ; port TDO/SWO
LCDSEG8: RS1.5 ; port TRST
LCDSEG17: RS1.7 ; port TDI
PA13: RS1.13 ; port TMS/SWDIO
PA14: RS1.11 ; port TCK/SWCLK
RESET#: RS1.3 ; port RESET#
NetCN12_2: CN12.2 CN15.7 R153.1 RS1.14 U17.1(IO1)
NetCN12_4: CN12.4 CN15.9 R155.2 RS1.12 U17.3(IO2)
NetCN12_6: CN12.6 CN15.13 R160.1 R162.2 RS1.10 U17.4(IO3)
NetCN12_8: CN12.8 CN15.5 R152.1 RS1.8 U17.5(IO4)
NetCN12_10: CN12.10 CN15.15 RS1.4 U18.3(IO2)
NetCN12_12: CN12.12 U18.4(IO3) ; port TRACE_CK
NetCN12_14: CN12.14 R154.1 R162.1 U19.5(IO4)
NetCN12_16: CN12.16 R131.1 R156.1 U19.4(IO3)
NetCN12_18: CN12.18 U19.3(IO2) ; port TRACE_D2
NetCN12_20: CN12.20 U19.1(IO1) ; port TRACE_D3
NetCN15_3: CN15.3 R126.1 R131.2 RS1.6 U18.1(IO1)
NetCN15_11: CN15.11 R157.1 R159.2
NetCN15_17: CN15.17 R163.2
NetCN15_19: CN15.19 R164.2
NetR104_1: R154.2 ; port TRACE_D0
NetR156_2: R156.2 ; port TRACE_D1

Not connected (* = marked no-connect by the designer): CN12 7; RS1 1 2 15 16; U18 5(IO4)

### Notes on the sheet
- PA13
- PA14
- PB3
- PA15
- PB4
- (near CN12) Trace connector
- KEY
- JTAG connector
- PE6
- PE5
- PE4
- PE3
- PE2

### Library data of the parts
CN12 = 20PIN1: Ordered by: Subcon; Comments: Trace connector; Assembly: with pin7 removed; ECCN_US/EU: NA
CN15 = 20PIN1: Ordered by: Subcon; Comments: JTAG connector; ECCN_US/EU: NA
R126 R131 R152 R153 R155 R157 R160 R162 = Res1: Resistor; Value: 1K; Ordered by: Subcon; ECCN_US/EU: NA; Fitted: NO
R154 R156 R159 R163 R164 = Res1: as R33 on sheet MCU2
RS1 = RES8B: Ordered by: Subcon; ECCN_US/EU: NA
U17-U19 = ESDALC6V1W5: Dual Transil array for ESD protection; Manuf_1: ST; Ref St: 9151112; Order: ESDA5V3L; ECCN_US/EU: EAR99/NEC

## Sheet ST_LINK.SCHDOC: ST_LINK
size A3; DocumentNumber: MB1144; Revision: C-02; SheetNumber: 25; SheetTotal: 25; Project: STM32L476G-EVAL

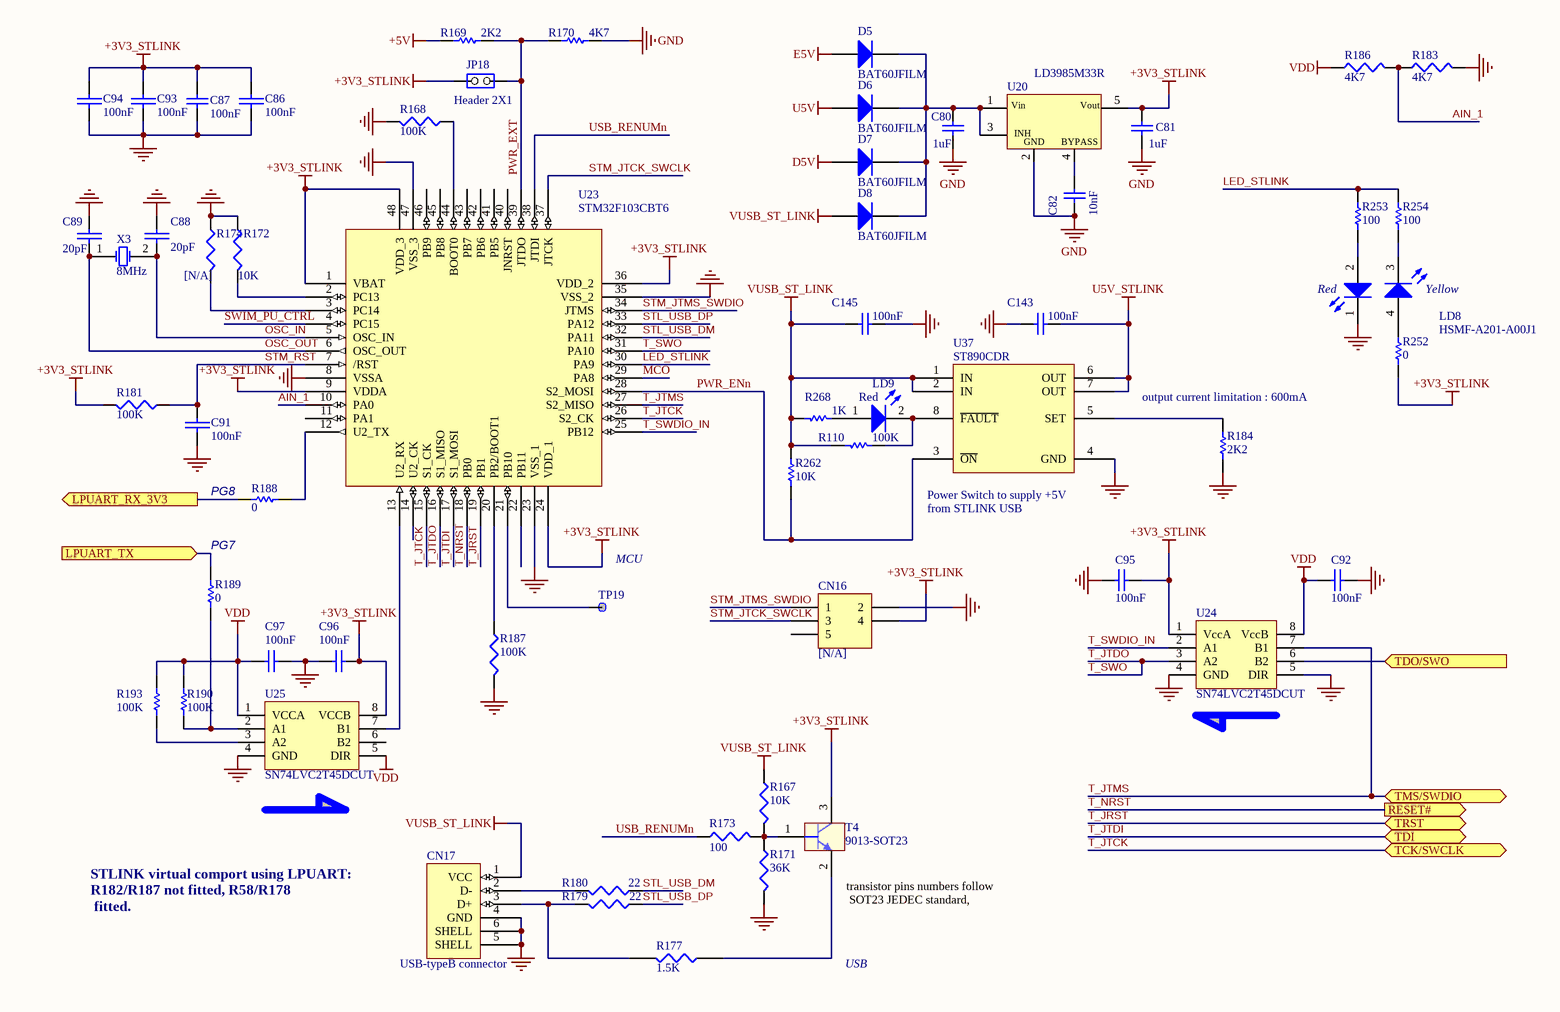
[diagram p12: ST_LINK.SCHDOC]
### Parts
C80  1uF  [0603C]
C81  1uF  [0603C]
C82  10nF  [0402C]
C86  100nF  [0402C]
C87  100nF  [0402C]
C88  20pF  [0402R]
C89  20pF  [0402R]
C91  100nF  [0402C]
C92  100nF  [0402C]
C93  100nF  [0402C]
C94  100nF  [0402C]
C95  100nF  [0402C]
C96  100nF  [0402C]
C97  100nF  [0402C]
C143  100nF  [0402C]
C145  100nF  [0402C]
CN16  [N/A]  [HDR_2X3-1_2R54-6]
CN17  USB-typeB connector  [USB-B]
D5  BAT60JFILM  [SOD-323]
D6  BAT60JFILM  [SOD-323]
D7  BAT60JFILM  [SOD-323]
D8  BAT60JFILM  [SOD-323]
JP18  Header 2X1  [SIP2]
LD8  HSMF-A201-A00J1  [LED2_3528]
LD9  Red  [0603D]
R110  100K  [0402R]
R167  10K  [0402R]
R168  100K  [0402R]
R169  2K2  [0402R]
R170  4K7  [0402R]
R171  36K  [0402R]
R172  10K  [0402R]
R173  100  [0402R]
R174  [N/A]  [0603R]
R177  1.5K  [0402R]
R179  22  [0402R]
R180  22  [0402R]
R181  100K  [0402R]
R183  4K7  [0402R]
R184  2K2  [0402R]
R186  4K7  [0402R]
R187  100K  [0402R]
R188  0  [0603R]
R189  0  [0603R]
R190  100K  [0402R]
R193  100K  [0402R]
R252  0  [0603R]
R253  100  [0402R]
R254  100  [0402R]
R262  10K  [0402R]
R268  1K  [0402R]
T4  9013-SOT23  [SOT-23]
TP19  [N/A]  [TP_C79]  (value not drawn)
U20  LD3985M33R  [SOT23-5]
U23  STM32F103CBT6  [LQFP48_0R5_9X9]
U24  SN74LVC2T45DCUT  [USOP8_0R5_2X3R1]
U25  SN74LVC2T45DCUT  [USOP8_0R5_2X3R1]
U37  ST890CDR  [SOIC8_1R27_4R9X6]
X3  8MHz  [XTAL_2SM_12R7X4R7]

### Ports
LPUART_RX_3V3 (out), LPUART_TX (in), RESET# (out), TCK/SWCLK, TDI, TDO/SWO (in), TMS/SWDIO, TRST

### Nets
+3V3_STLINK: C81.1 C86.2 C87.1 C93.2 C94.2 C95.2 C96.1 CN16.4 JP18.1(COMMON) R181.2 R252.2 T4.3(C) U20.5(Vout) U23.1(VBAT) U23.9(VDDA) U23.24(VDD_1) U23.36(VDD_2) U23.48(VDD_3) U24.1(VccA) U25.8(VCCB)
+5V: R169.2
D5V: D7.1(A)
E5V: D5.1(A)
GND: C80.2 C81.2 C82.2 C86.1 C87.2 C88.1 C89.1 C91.1 C92.2 C93.1 C94.1 C95.1 C96.2 C97.2 C143.1 C145.2 CN16.2 CN17.4(GND) CN17.5(SHELL) CN17.6(SHELL) LD8.1(RED_cathode) R168.2 R170.1 R171.2 R172.1 R174.1 R183.2 R184.2 R187.2 U20.2(GND) U23.8(VSSA) U23.23(VSS_1) U23.35(VSS_2) U23.47(VSS_3) U24.4(GND) U24.5(DIR) U25.4(GND) U37.4(GND)
U5V: D6.1(A)
U5V_STLINK: C143.2 U37.6(OUT) U37.7(OUT)
VDD: C92.1 C97.1 R186.1 R190.1 R193.1 U24.8(VccB) U25.1(VCCA) U25.5(DIR)
VUSB_ST_LINK: C145.1 CN17.1(VCC) D8.1(A) R110.1 R167.1 R262.2 R268.1 U37.1(IN) U37.2(IN)
AIN_1: R183.1 R186.2 U23.10(PA0)
LCDSEG7: U24.6(B2) ; port TDO/SWO
LED_STLINK: R253.1 R254.1 U23.30(PA9)
MCO: U23.29(PA8)
OSC_IN: C88.2 U23.5(OSC_IN) X3.2(OSC2)
OSC_OUT: C89.2 U23.6(OSC_OUT) X3.1(OSC1)
PG8: R188.2 ; port LPUART_RX_3V3
PWR_ENn: R262.1 U23.28(S2_MOSI) U37.3(~{ON})
PWR_EXT: JP18.2(NO) R169.1 R170.2 U23.39(JTDO)
STL_USB_DM: R180.1 U23.32(PA11)
STL_USB_DP: R179.1 U23.33(PA12)
STM_JTCK_SWCLK: CN16.3 U23.37(JTCK)
STM_JTMS_SWDIO: CN16.1 U23.34(JTMS)
STM_RST: C91.2 R181.1 U23.7(/RST)
SWIM_PU_CTRL: U23.4(PC15)
T_JRST: U23.19(PB1) ; port TRST  [project net LCDSEG8]
T_JTCK: U23.15(S1_CK) U23.26(S2_CK) ; port TCK/SWCLK  [project net PA14]
T_JTDI: U23.17(S1_MOSI) ; port TDI  [project net LCDSEG17]
T_JTDO: U23.16(S1_MISO) U23.31(PA10) U24.3(A2)  [also labelled T_SWO]
T_JTMS: U23.27(S2_MISO) U24.7(B1) ; port TMS/SWDIO  [project net PA13]
T_NRST: U23.18(PB0) ; port RESET#  [project net RESET#]
T_SWDIO_IN: U23.25(PB12) U24.2(A1)
USB_RENUMn: R173.1 U23.38(JTDI)
NetC80_1: C80.1 D5.2(K) D6.2(K) D7.2(K) D8.2(K) U20.1(Vin) U20.3(CE)
NetC82_1: C82.1 U20.4(BYPASS)
NetCN17_2: CN17.2(D-) R180.2
NetCN17_3: CN17.3(D+) R177.2 R179.2
NetLD8_2: LD8.2(Red_anode) R253.2
NetLD8_3: LD8.3(YellowGreen_cathode) R254.2
NetLD8_4: LD8.4(YellowGreen_anode) R252.1
NetLD9_1: LD9.1(A) R268.2
NetLD9_2: LD9.2(K) R110.2 U37.8(~{FAULT})
NetR34_1: R189.1 ; port LPUART_TX
NetR167_2: R167.2 R171.1 R173.2 T4.1(B)
NetR168_1: R168.1 U23.44(BOOT0)
NetR172_2: R172.2 U23.2(PC13)
NetR174_2: R174.2 U23.3(PC14)
NetR177_1: R177.1 T4.2(E)
NetR184_1: R184.1 U37.5(SET)
NetR187_1: R187.1 U23.20(PB2/BOOT1)
NetR188_1: R188.1 U23.12(U2_TX)
NetR189_2: R189.2 R190.2 U25.2(A1)
NetR193_2: R193.2 U25.3(A2)
NetTP19_1: TP19.1 U23.21(PB10)
NetU23_13: U23.13(U2_RX) U25.7(B1)

Not connected (* = marked no-connect by the designer): CN16 5; U23 11(PA1) 14(U2_CK) 22(PB11) 40(JNRST) 41(PB5) 42(PB6) 43(PB7) 45(PB8) 46(PB9); U25 6(B2)

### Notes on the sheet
- (near R184) output current limitation : 600mA
- (near R188) PG8
- (near U37) Power Switch to supply +5V from STLINK USB
- (near R189) PG7
- (near TP19) MCU
- STLINK virtual comport using LPUART: R182/R187 not fitted, R58/R178
  fitted.
- (near T4) transistor pins numbers follow
  SOT23 JEDEC standard,
- USB

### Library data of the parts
C80 C81 = CAP: as C58 on sheet MCU2
C82 = Cap: Capacitor; Ordered by: Subcon; ECCN_US/EU: NA
C86 C91 C93 C94 = CAP: Ordered by: Subcon; ECCN_US/EU: NA
C87 = Cap: as C12 on sheet SRAM&Flash
C88 C89 = CAP: as C54-C57 on sheet MCU2
C92 C95-C97 = CAP: as C141 on sheet MCU2
C143 C145 = Capacitor_ST: Capacitor 0402 / 0603 / 0805; Ordered by: Subcon; ECCN_US/EU: NA
CN16 = Header 3X2: Header, 3-Pin, Dual row; ECCN_US/EU: NA; Ordered by: Subcon; Comments: ST-LINK programming; Fitted: NO
CN17 = USB-typeB connector: ECCN_US/EU: NA; Ordered by: Subcon; Comments: ST-LINK/V2-1 connector
D5-D8 = Diode: as D3 on sheet MCU2
JP18 = JP2: Ordered by: Subcon; ECCN_US/EU: NA
LD8 = HSMF-A201-A00J1: Ordered by: Subcon; ECCN_US/EU: NA
LD9 = LED2: Typical RED, GREEN, YELLOW, AMBER GaAs LED; Ordered by: Subcon; ECCN_US/EU: NA
R110 R188-R190 R193 R252-R254 = Res1: as R33 on sheet MCU2
R167 R171-R173 = R: Resistor; Right: 20; Bottom: 30; Ordered by: Subcon; ECCN_US/EU: NA
R168 R179-R181 R187 = RES1: Resistor; Ordered by: Subcon; ECCN_US/EU: NA
R169 R170 R184 = res1: as R35 on sheet MCU2
R174 = R: Right: 20; Bottom: 30; Ordered by: Subcon; ECCN_US/EU: NA; Fitted: NO
R177 R183 R186 = RES1: Ordered by: Subcon; ECCN_US/EU: NA
R262 = Resistor_ST: Resistor; Description: Resistor 0402 or 0603 or 0805; Ordered by: Subcon; ECCN_US/EU: NA
R268 = Res1: Resistor; Ordered by: Subcon; ECCN_US/EU: NA
T4 = 9013-SOT23: NPN Bipolar Transistor; Manuf_1: Taitron; Manuf_Part_1: MMBT9013; Description: NPN Bipolar Transistor, SOT-23 Footprint; Ordered by: Subcon; ECCN_US/EU: EAR99/NEC
TP19 = TP: as TP7 on sheet MCU2
U20 = LD3985M33R: Ultra low drop-low noise BiCMOS voltage, regulators low ESR capacitors compatible; Manuf_1: ST; Ref St: 9176161; ECCN_US/EU: EAR99/NEC
U23 = STM32F10x(48pin): Ordered by: ST; ECCN_US/EU: 3A991A2/NEC; Ref St: 9175111
U24 U25 = SN74LVC2T45DCUT: Manuf_1: TI; Ordered by: Subcon; ECCN_US/EU: EAR99/NEC
U37 = ST890CDR: Ordered by: ST; ECCN_US/EU: EAR99/NEC; Ref St: 9172002
X3 = XTAL: Crystal Oscillator; Manuf_1: jfvny; Manuf_Part_1: SSL8000012AFDHF0-SJ28; Ordered by: Subcon; ECCN_US/EU: NA

## Sheet USART_IrDA.SchDoc: USART_IrDA
size A3; DocumentNumber: MB1144; Revision: C-02; SheetNumber: 9; SheetTotal: 25; Project: STM32L476G-EVAL

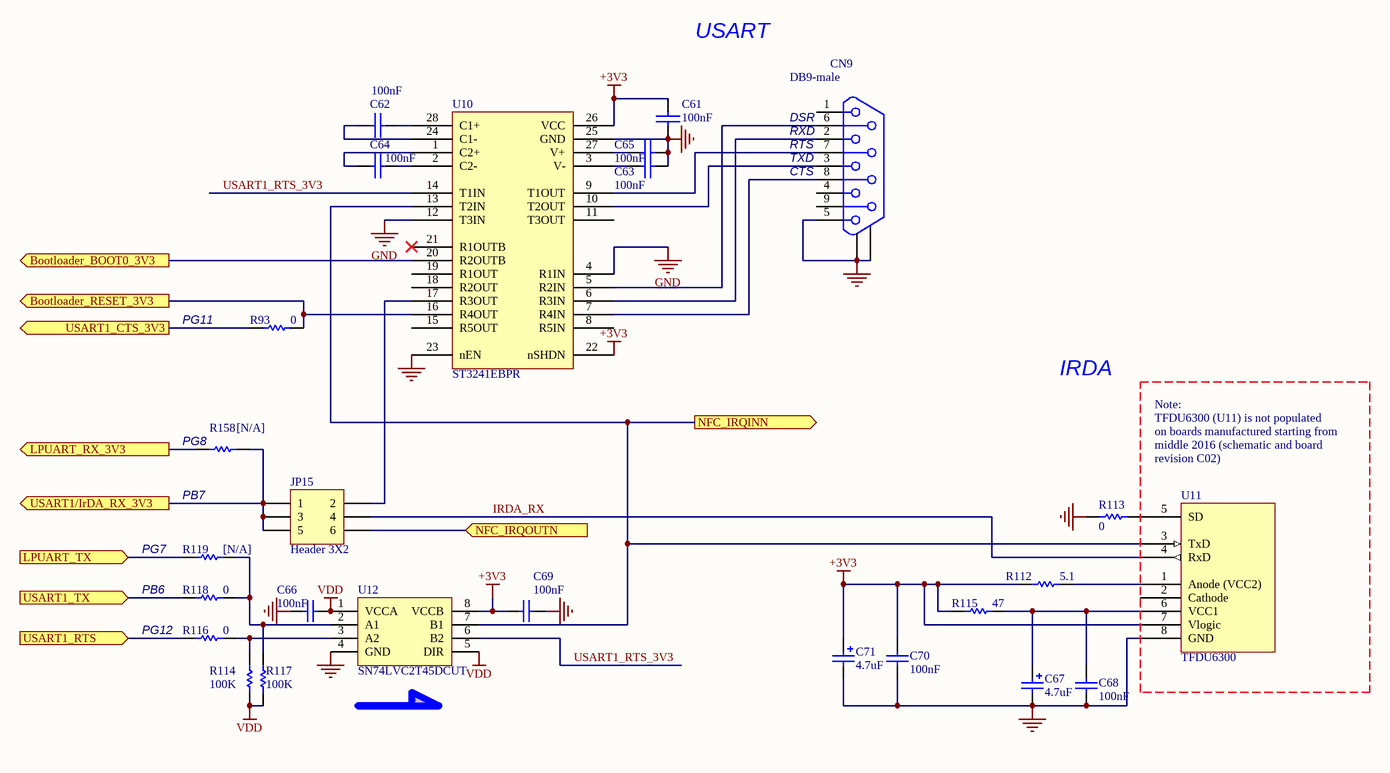
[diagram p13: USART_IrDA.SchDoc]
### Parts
C61  100nF  [0402C]
C62  100nF  [0402C]
C63  100nF  [0402C]
C64  100nF  [0402C]
C65  100nF  [0402C]
C66  100nF  [0402C]
C67  4.7uF  [TAN-A]
C68  100nF  [0402C]
C69  100nF  [0402C]
C70  100nF  [0402C]
C71  4.7uF  [TAN-A]
CN9  DB9-male  [DB9/M]
JP15  Header 3X2  [HDR_2X3_2R54]
R93  0  [0603R]
R112  5.1  [0402R]
R113  0  [0603R]
R114  100K  [0402R]
R115  47  [0402R]
R116  0  [0603R]
R117  100K  [0402R]
R118  0  [0603R]
R119  [N/A]  [0603R]
R158  [N/A]  [0603R]
U10  ST3241EBPR  [SSOP28_0R65_10R2X7R8]
U11  TFDU6300  [IR_VISHAY3]
U12  SN74LVC2T45DCUT  [USOP8_0R5_2X3R1]

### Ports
Bootloader_BOOT0_3V3 (out), Bootloader_RESET_3V3 (out), LPUART_RX_3V3 (out), LPUART_TX (in), NFC_IRQINN (out), NFC_IRQOUTN (in), USART1/IrDA_RX_3V3 (out), USART1_CTS_3V3 (out), USART1_RTS (in), USART1_TX (in)

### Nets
+3V3: C61.2 C69.2 C70.2 C71.1 R112.1 R115.1 U10.22(nSHDN) U10.26(VCC) U11.7(Vlogic) U12.8(VCCB)
GND: C61.1 C63.2 C65.2 C66.1 C67.2 C68.1 C69.1 C70.1 C71.2 CN9.5 CN9.10 CN9.11 R113.2 U10.4(R1IN) U10.12(T3IN) U10.23(nEN) U10.25(GND) U11.8(GND) U12.4(GND)
VDD: C66.2 R114.2 R117.2 U12.1(VCCA) U12.5(DIR)
IRDA_RX: JP15.4 U11.4(RxD)
PB6: R118.2 ; port USART1_TX
PG8: R158.2 ; port LPUART_RX_3V3
PG11: R93.2 ; port USART1_CTS_3V3
PG12: R116.2 ; port USART1_RTS
USART1_RTS_3V3: U10.14(T1IN) U12.6(B2)
NetC62_1: C62.1 U10.24(C1-)
NetC62_2: C62.2 U10.28(C1+)
NetC63_1: C63.1 U10.3(V-)
NetC64_1: C64.1 U10.1(C2+)
NetC64_2: C64.2 U10.2(C2-)
NetC65_1: C65.1 U10.27(V+)
NetC67_1: C67.1 C68.2 R115.2 U11.6(VCC1)
NetCN9_2: CN9.2 U10.6(R3IN)
NetCN9_3: CN9.3 U10.10(T2OUT)
NetCN9_6: CN9.6 U10.5(R2IN)
NetCN9_7: CN9.7 U10.9(T1OUT)
NetCN9_8: CN9.8 U10.7(R4IN)
NetCN13_1: JP15.6 ; port NFC_IRQOUTN
NetCN13_2: U10.13(T2IN) U11.3(TxD) U12.7(B1) ; port NFC_IRQINN
NetCN14_10: JP15.1 JP15.3 JP15.5 R158.1 ; port USART1/IrDA_RX_3V3
NetD4_2: R93.1 U10.16(R4OUT) ; port Bootloader_RESET_3V3
NetJP15_2: JP15.2 U10.17(R3OUT)
NetR34_1: R119.2 ; port LPUART_TX
NetR59_2: U10.20(R2OUTB) ; port Bootloader_BOOT0_3V3
NetR112_2: R112.2 U11.1(Anode_(VCC2))
NetR113_1: R113.1 U11.5(SD)
NetR114_1: R114.1 R116.1 U12.3(A2)
NetR117_1: R117.1 R118.1 R119.1 U12.2(A1)

Not connected (* = marked no-connect by the designer): CN9 1 4 9; U10 8(R5IN) 11(T3OUT) 15(R5OUT) 18(R2OUT) 19(R1OUT) 21(R1OUTB)*; U11 2(Cathode)

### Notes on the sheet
- USART
- (near CN9) RXD
- (near CN9) RTS
- (near CN9) TXD
- (near CN9) DSR
- (near CN9) CTS
- PG11
- IRDA
- PB7
- (near R158) PG8
- Note:
  TFDU6300 (U11) is not populated
  on boards manufactured starting from
  middle 2016 (schematic and board revision C02)
- PG7
- PG12
- PB6

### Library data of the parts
C61-C65 = CAP: as C54-C57 on sheet MCU2
C66 C68-C70 = CAP: as C141 on sheet MCU2
C67 C71 = Cap Pol1: Polarized Capacitor (Radial); Value: 100pF; Ordered by: Subcon; ECCN_US/EU: NA
CN9 = DB9: Ordered by: Subcon; Comments: DB9 USART; ECCN_US/EU: NA
JP15 = Header 3X2: Header, 3-Pin, Dual row; ECCN_US/EU: NA; Ordered by: Subcon
R93 R112-R118 = Res1: as R33 on sheet MCU2
R119 R158 = Res1: as R126 on sheet JTAG&Trace
U10 = ST3241: Ordered by: ST; ECCN_US/EU: EAR99/NEC; Ref St: 9176312
U11 = TFDU4300: Manuf_1: Vishay; Ordered by: Subcon; ECCN_US/EU: EAR99/NEC; Fitted or not fitted: NO
U12 = SN74LVC2T45DCUT: as U24 on sheet ST_LINK

## Sheet SWP_SmartCard_NFC.SchDoc: SWP_SmartCard_NFC
size A3; DocumentNumber: MB1144; Revision: C-02; SheetNumber: 8; SheetTotal: 25; Project: STM32L476G-EVAL

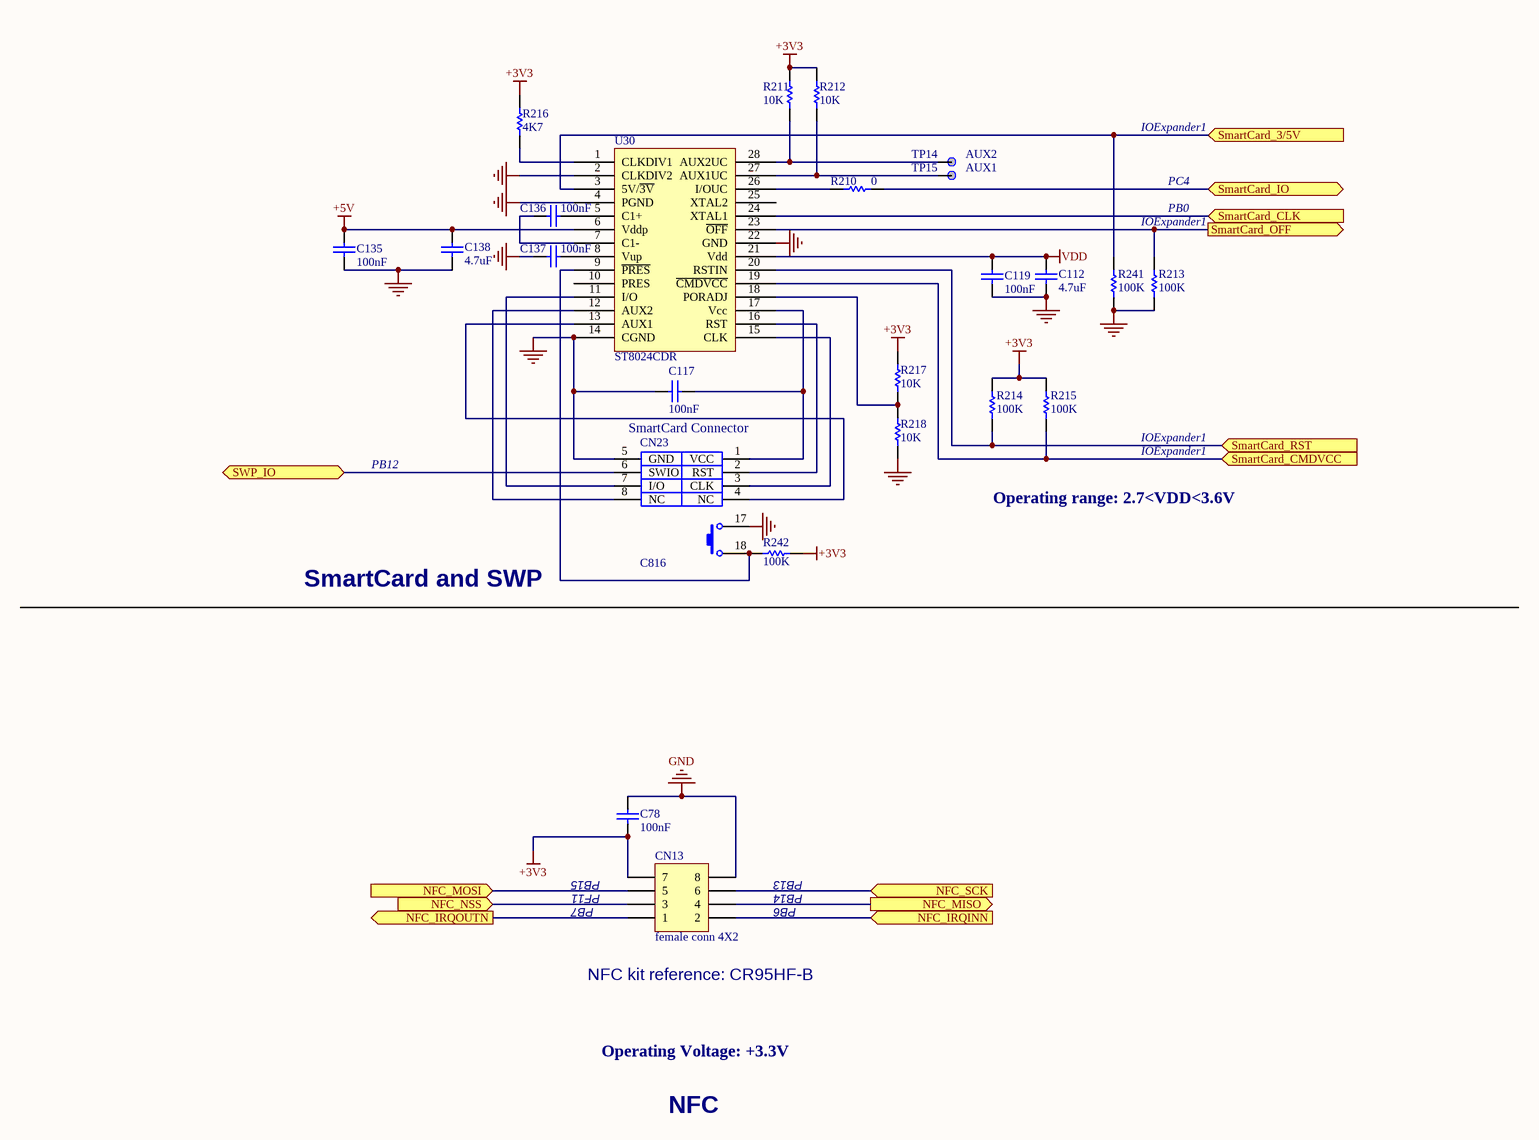
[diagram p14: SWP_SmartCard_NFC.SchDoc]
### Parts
C78  100nF  [0402C]
C112  4.7uF  [0603C]
C117  100nF  [0402C]
C119  100nF  [0402C]
C135  100nF  [0402C]
C136  100nF  [0402C]
C137  100nF  [0402C]
C138  4.7uF  [0603C]
CN13  female conn 4X2  [HDR_2X4_2R54_N]
CN23  C816  [sam_c816]
R210  0  [0603R]
R211  10K  [0402R]
R212  10K  [0402R]
R213  100K  [0402R]
R214  100K  [0402R]
R215  100K  [0402R]
R216  4K7  [0402R]
R217  10K  [0402R]
R218  10K  [0402R]
R241  100K  [0402R]
R242  100K  [0402R]
TP14  TP Name: AUX2  [TP]  (hidden comment: [N/A])
TP15  TP Name: AUX1  [TP]  (hidden comment: [N/A])
U30  ST8024CDR  [SOIC28W_1R27_17R9X10R325]

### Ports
NFC_IRQINN (in), NFC_IRQOUTN (out), NFC_MISO (out), NFC_MOSI (in), NFC_NSS (in), NFC_SCK (in), SmartCard_3/5V (in), SmartCard_CLK (in), SmartCard_CMDVCC (in), SmartCard_IO (bidir), SmartCard_OFF (out), SmartCard_RST (in), SWP_IO (bidir)

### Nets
+3V3: C78.2 CN13.7 R211.1 R212.1 R214.1 R215.1 R216.1 R217.1 R242.1
+5V: C135.1 C138.1 U30.6(Vddp)
GND: C78.1 C112.2 C117.1 C119.2 C135.2 C137.2 C138.2 CN13.8 CN23.5(GND) CN23.17 R213.2 R218.2 R241.2 U30.2(CLKDIV2) U30.4(PGND) U30.14(CGND) U30.22(GND)
VDD: C112.1 C119.1 U30.21(Vdd)
PF11: CN13.3 ; port NFC_NSS
NetC117_2: C117.2 CN23.1(VCC) U30.17(Vcc)
NetC136_1: C136.1 U30.7(C1-)
NetC136_2: C136.2 U30.5(C1+)
NetC137_1: C137.1 U30.8(Vup)
NetCN11_16: CN13.4 ; port NFC_MISO
NetCN11_18: CN13.6 ; port NFC_SCK
NetCN11_20: CN23.6(SWIO) ; port SWP_IO
NetCN11_26: CN13.5 ; port NFC_MOSI
NetCN13_1: CN13.1 ; port NFC_IRQOUTN
NetCN13_2: CN13.2 ; port NFC_IRQINN
NetCN23_2: CN23.2(RST) U30.16(RST)
NetCN23_3: CN23.3(CLK) U30.15(CLK)
NetCN23_4: CN23.4(NC) U30.13(AUX1)
NetCN23_7: CN23.7(I/O) U30.11(I/O)
NetCN23_8: CN23.8(NC) U30.12(AUX2)
NetCN23_18: CN23.18 R242.2 U30.9(~{PRES})
NetR107_1: U30.24(XTAL1) ; port SmartCard_CLK
NetR143_1: R210.2 ; port SmartCard_IO
NetR210_1: R210.1 U30.26(I/OUC)
NetR211_2: R211.2 TP14.1 U30.28(AUX2UC)
NetR212_2: R212.2 TP15.1 U30.27(AUX1UC)
NetR213_1: R213.1 U30.23(~{OFF}) ; port SmartCard_OFF
NetR214_2: R214.2 U30.20(RSTIN) ; port SmartCard_RST
NetR215_2: R215.2 U30.19(~{CMDVCC}) ; port SmartCard_CMDVCC
NetR216_2: R216.2 U30.1(CLKDIV1)
NetR217_2: R217.2 R218.1 U30.18(PORADJ)
NetR241_1: R241.1 U30.3(5V/~{3V}) ; port SmartCard_3/5V

Not connected (* = marked no-connect by the designer): U30 10(PRES) 25(XTAL2)

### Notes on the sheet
- IOExpander1
- PC4
- PB0
- (near CN23) SmartCard Connector
- PB12
- Operating range: 2.7<VDD<3.6V
- SmartCard and SWP
- PB7
- PB15
- PF11
- PB6
- PB14
- PB13
- (near CN13) NFC kit reference: CR95HF-B
- Operating Voltage: +3.3V
- NFC

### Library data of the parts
C78 = CAP: as C141 on sheet MCU2
C112 C138 = Cap: as C12 on sheet SRAM&Flash
C117 C119 C135-C137 = CAP: as C54-C57 on sheet MCU2
CN13 = female conn 4X2: female conn 4X2 4-Pin, Dual row; Ordered by: Subcon; ECCN_US/EU: NA; Comments: NFC connector
CN23 = Smart_card_CN: Ordered by: Subcon; Comments: Smartcard "GSM file and SWP" conenctor; ECCN_US/EU: NA; Assembly: with ST smartcard 8000080
R210-R218 R241 R242 = Res1: as R33 on sheet MCU2
TP14 TP15 = TP: as TP7 on sheet MCU2
U30 = ST8024CTR: Ordered by: ST; ECCN_US/EU: EAR99/NEC; Ref St: 9177802

## Sheet STPMS2&PT100.SchDoc: STPMS2&PT100
size A3; DocumentNumber: MB1144; Revision: C-02; SheetNumber: 21; SheetTotal: 25; Project: STM32L476G-EVAL

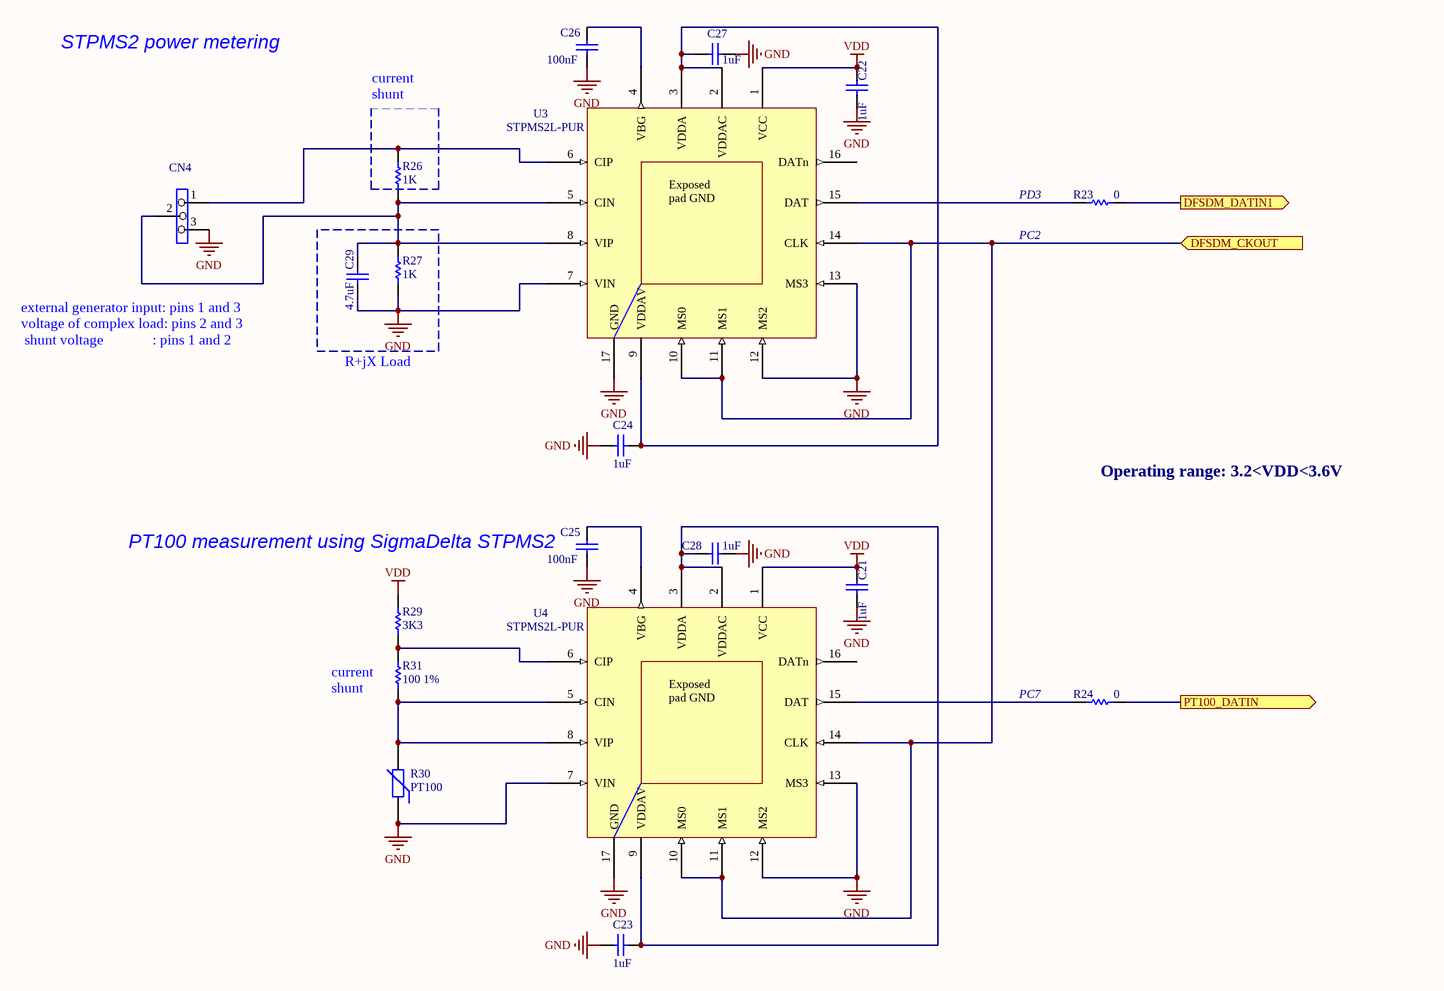
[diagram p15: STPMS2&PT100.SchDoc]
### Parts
C21  1uF  [0603C]
C22  1uF  [0603C]
C23  1uF  [0603C]
C24  1uF  [0603C]
C25  100nF  [0402C]
C26  100nF  [0402C]
C27  1uF  [0603C]
C28  1uF  [0603C]
C29  4.7uF  [0603C]
CN4  Header 3X1  [SIP3]  (value not drawn)
R23  0  [0603R]
R24  0  [0603R]
R26  1K  [0402R]
R27  1K  [0402R]
R29  3K3  [0402R]
R30  PT100  [HDR_1X2_1R27]
R31  100 1%  [0603R]
U3  STPMS2L-PUR  [QFN16_0R65_4X4]
U4  STPMS2L-PUR  [QFN16_0R65_4X4]

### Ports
DFSDM_CKOUT (in), DFSDM_DATIN1 (out), PT100_DATIN (out)

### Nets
GND: C21.2 C22.2 C23.1 C24.1 C25.1 C26.1 C27.2 C28.2 C29.2 CN4.3 R27.2 R30.1 U3.7(VIN) U3.12(MS2) U3.13(MS3) U3.17(GND) U4.7(VIN) U4.12(MS2) U4.13(MS3) U4.17(GND)
VDD: C21.1 C22.1 R29.1 U3.1(VCC) U4.1(VCC)
PD3: R23.1 ; port DFSDM_DATIN1
NetC23_2: C23.2 C28.1 U4.2(VDDAC) U4.3(VDDA) U4.9(VDDAV)
NetC24_2: C24.2 C27.1 U3.2(VDDAC) U3.3(VDDA) U3.9(VDDAV)
NetC25_2: C25.2 U4.4(VBG)
NetC26_2: C26.2 U3.4(VBG)
NetC29_1: C29.1 CN4.2 R26.2 R27.1 U3.5(CIN) U3.8(VIP)
NetCN4_1: CN4.1 R26.1 U3.6(CIP)
NetCN11_28: U3.10(MS0) U3.11(MS1) U3.14(CLK) U4.10(MS0) U4.11(MS1) U4.14(CLK) ; port DFSDM_CKOUT
NetR23_2: R23.2 U3.15(DAT)
NetR24_1: R24.1 ; port PT100_DATIN
NetR24_2: R24.2 U4.15(DAT)
NetR29_2: R29.2 R31.1 U4.6(CIP)
NetR30_2: R30.2 R31.2 U4.5(CIN) U4.8(VIP)

Not connected (* = marked no-connect by the designer): U3 16(DATn); U4 16(DATn)

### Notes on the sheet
- STPMS2 power metering
- current shunt
- (near R23) PD3
- PC2
- external generator input: pins 1 and 3
  voltage of complex load: pins 2 and 3
  shunt voltage              : pins 1 and 2
- R+jX Load
- PT100 measurement using SigmaDelta STPMS2
- Operating range: 3.2<VDD<3.6V
- (near R31) current shunt
- (near R24) PC7

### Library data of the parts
C21-C24 C27-C29 = CAP: as C58 on sheet MCU2
C25 C26 = Cap: as C12 on sheet SRAM&Flash
CN4 = Jumper3: Ordered by: Subcon; ECCN_US/EU: NA
R23 R24 = res1: as R35 on sheet MCU2
R26 R27 = Res1: as R268 on sheet ST_LINK
R29 R31 = Res1: as R33 on sheet MCU2
R30 = PT100: Varistor (Voltage-Sensitive Resistor); ECCN_US/EU: NA; Ordered by: Subcon
U3 U4 = STPMS2: STM sigmaDelta modulator; Ordered by: ST; ECCN_US/EU: EAR99/NEC; Ref St: 9177717

## Sheet IDD_measurement.SchDoc: IDD_measurement
size A3; DocumentNumber: MB1144; Revision: C-02; SheetNumber: 19; SheetTotal: 25; Project: STM32L476G-EVAL

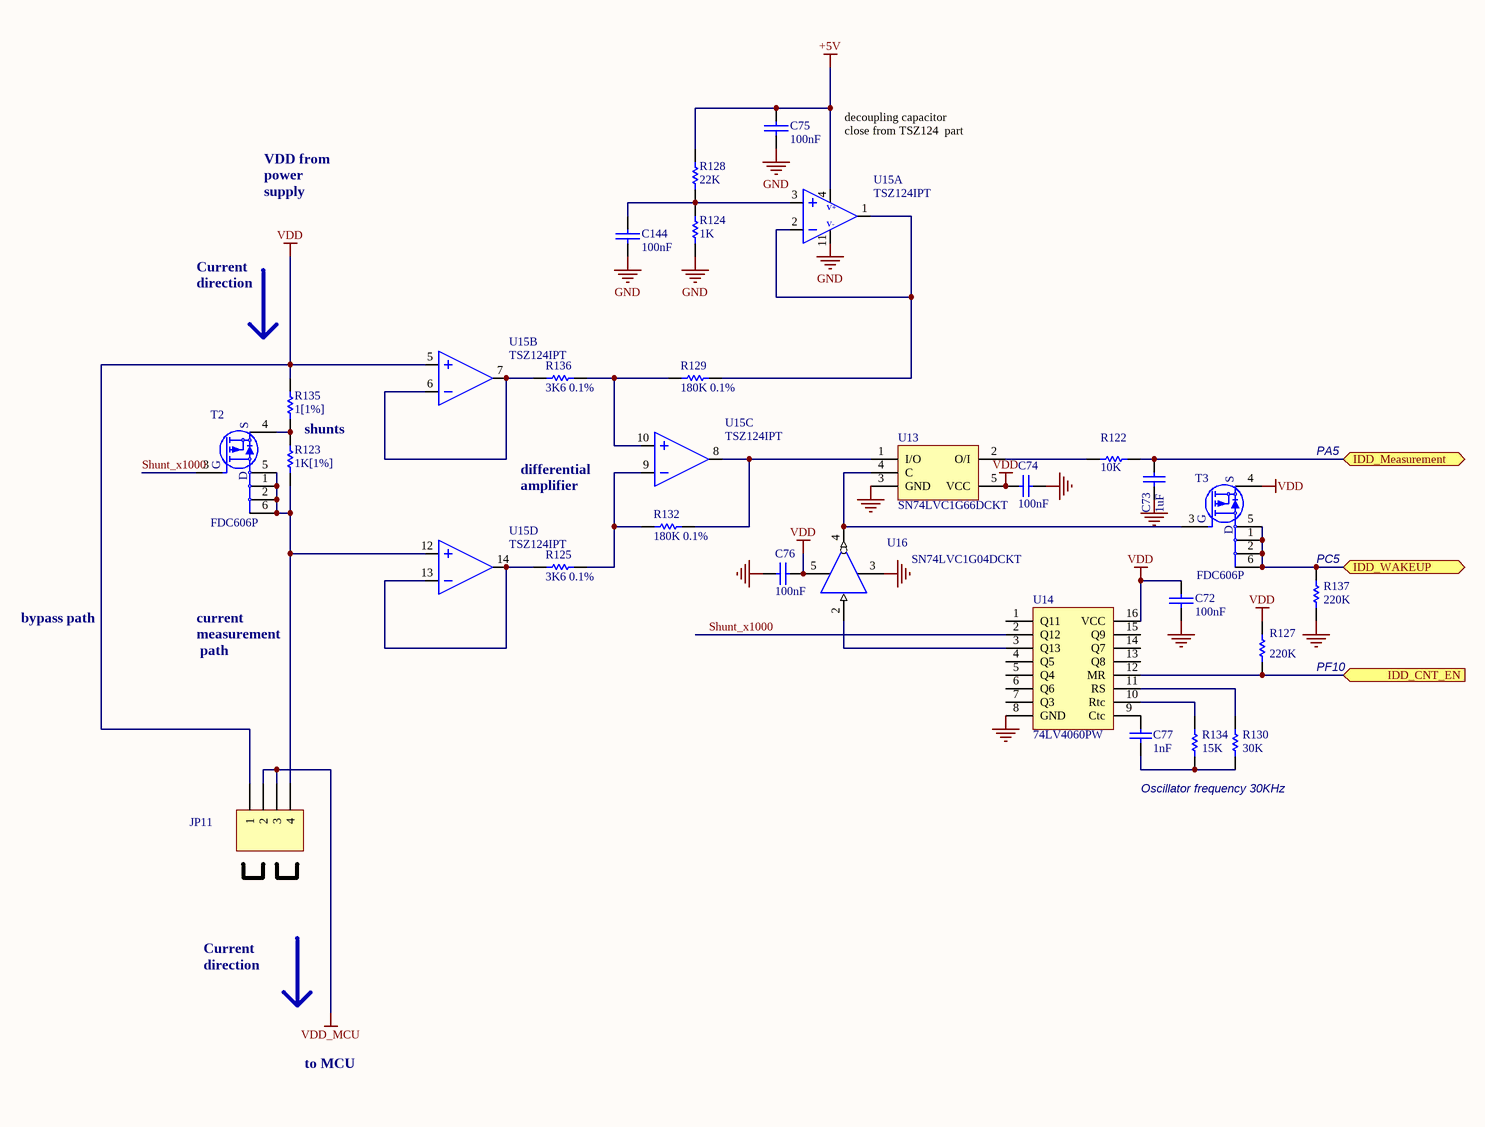
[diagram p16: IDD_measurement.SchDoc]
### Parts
C72  100nF  [0402C]
C73  1uF  [0603C]
C74  100nF  [0402C]
C75  100nF  [0402C]
C76  100nF  [0402C]
C77  1nF  [0402C]
C144  100nF  [0402C]
JP11  Header 4  [SIP4]  (value not drawn)
R122  10K  [0402R]
R123  1K[1%]  [0603R]
R124  1K  [0402R]
R125  3K6 0.1%  [0402R]
R127  220K  [0402R]
R128  22K  [0402R]
R129  180K 0.1%  [0402R]
R130  30K  [0402R]
R132  180K 0.1%  [0402R]
R134  15K  [0402R]
R135  1[1%]  [0603R]
R136  3K6 0.1%  [0402R]
R137  220K  [0402R]
T2  FDC606P  [SOT23-6]
T3  FDC606P  [SOT23-6]
U13  SN74LVC1G66DCKT  [SC70-5]
U14  74LV4060PW  [TSSOP16_0R65_5x6R4]
U15  TSZ124IPT  [TSSOP14_0R65_5X6R4]  (parts A,B,C,D of 4)
U16  SN74LVC1G04DCKT  [SC70-5]

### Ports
IDD_CNT_EN (in), IDD_Measurement, IDD_WAKEUP

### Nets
+5V: C75.1 R128.1 U15.4
GND: C72.2 C73.2 C74.1 C75.2 C76.2 C144.2 R124.2 R137.2 U13.3(GND) U14.8(GND) U15.11 U16.3(GND)
VDD: C72.1 C74.2 C76.1 JP11.1 R127.1 R135.2 T3.4(S) U13.5(VCC) U14.16(VCC) U15.5 U16.5(VCC)
VDD_MCU: JP11.2 JP11.3
Shunt_x1000: T2.3(G) U14.2(Q12)
NetC73_1: C73.1 R122.2 ; port IDD_Measurement
NetC77_1: C77.1 U14.9(Ctc)
NetC77_2: C77.2 R130.2 R134.2
NetC144_1: C144.1 R124.1 R128.2 U15.3
NetJP11_4: JP11.4 R123.1 T2.1(D) T2.2(D) T2.5(D) T2.6(D) U15.12
NetR91_1: R127.2 U14.12(MR) ; port IDD_CNT_EN
NetR122_1: R122.1 U13.2(O/I)
NetR123_2: R123.2 R135.1 T2.4(S)
NetR125_1: R125.1 U15.13 U15.14
NetR125_2: R125.2 R132.1 U15.9
NetR129_1: R129.1 R136.2 U15.10
NetR129_2: R129.2 U15.1 U15.2
NetR130_1: R130.1 U14.11(RS)
NetR132_2: R132.2 U13.1(I/O) U15.8
NetR134_1: R134.1 U14.10(Rtc)
NetR136_1: R136.1 U15.6 U15.7
NetR137_1: R137.1 T3.1(D) T3.2(D) T3.5(D) T3.6(D) ; port IDD_WAKEUP
NetT3_3: T3.3(G) U13.4(C) U16.4(1Y)
NetU14_3: U14.3(Q13) U16.2(1A)

Not connected (* = marked no-connect by the designer): U14 1(Q11) 4(Q5) 5(Q4) 6(Q6) 7(Q3) 13(Q8) 14(Q7) 15(Q9); U16 1(NC)

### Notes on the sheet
- decoupling capacitor
  close from TSZ124  part
- VDD from power supply
- Current direction
- shunts
- PA5
- differential
  amplifier
- (near R137) PC5
- bypass path
- current
  measurement
  path
- PF10
- Oscillator frequency 30KHz
- to MCU

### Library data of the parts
C72 C75 C144 = CAP: Ordered by: Subcon; ECCN_US/EU: NA
C73 = CAP: as C58 on sheet MCU2
C74 C76 = CAP: as C141 on sheet MCU2
C77 = Cap: as C12 on sheet SRAM&Flash
JP11 = Header 4: Header, 4-Pin; Ordered by: Subcon
R122 R123 R125 R127-R130 R132 R134-R137 = res1: as R35 on sheet MCU2
R124 = res1: Resistor; Ordered by: Subcon; ECCN_US/EU: NA
T2 T3 = STT5PF20V: Manuf_1: Fairchild; Ordered by: Subcon; ECCN_US/EU: EAR99/NEC
U13 = 74H1G66STR: Manuf_1: TI; Ordered by: Subcon; ECCN_US/EU: EAR99/NEC
U14 = M74HC4060TTR: Manuf_1: NXP; Ordered by: Subcon; ECCN_US/EU: EAR99/NEC
U15 = AOP-14PINS: Very high accuracy (5 µV) zero drift 5 V quad OpAmp; Ordered by: ST; ECCN_US/EU: EAR99/NEC; Ref St: 9177442
U16 = 74LX1G04CTR: Manuf_1: TI; Ordered by: Subcon; ECCN_US/EU: EAR99/NEC

## Sheet USB_OTG_FS.SchDoc: USB_OTG_FS
size A4; DocumentNumber: MB1144; Revision: C-02; SheetNumber: 18; SheetTotal: 25; Project: STM32L476G-EVAL

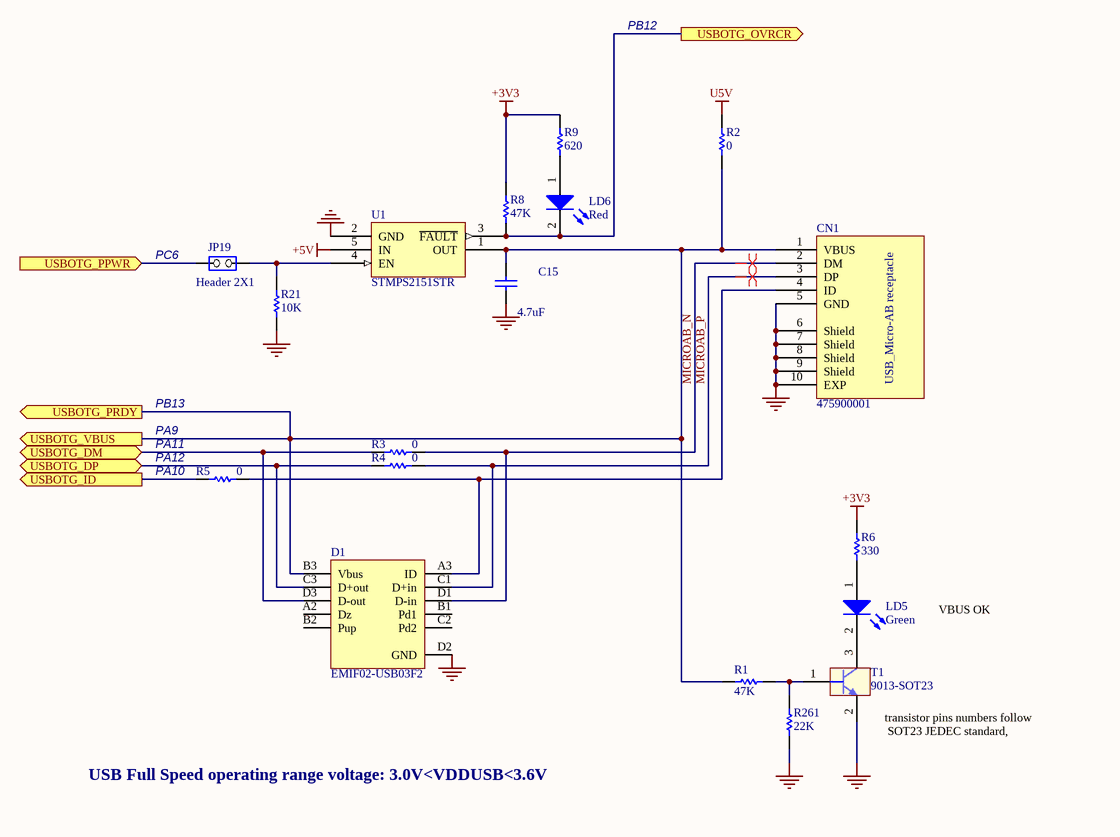
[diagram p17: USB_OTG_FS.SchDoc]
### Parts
C15  4.7uF  [0603C]
CN1  475900001  [MOLEX_47590001]
D1  EMIF02-USB03F2  [BGA11_0R5_1R57X2R07]
JP19  Header 2X1  [SIP2]
LD5  Green  [0603D]
LD6  Red  [0603D]
R1  47K  [0402R]
R2  0  [0603R]
R3  0  [0603R]
R4  0  [0603R]
R5  0  [0603R]
R6  330  [0402R]
R8  47K  [0402R]
R9  620  [0402R]
R21  10K  [0402R]
R261  22K  [0402R]
T1  9013-SOT23  [SOT-23]
U1  STMPS2151STR  [SOT23-5]

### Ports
USBOTG_DM (bidir), USBOTG_DP (bidir), USBOTG_ID (out), USBOTG_OVRCR (out), USBOTG_PPWR (in), USBOTG_PRDY (out), USBOTG_VBUS (out)

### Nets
+3V3: R6.1 R8.1 R9.1
+5V: U1.5(IN)
GND: C15.2 CN1.5(GND) CN1.6(Shield) CN1.7(Shield) CN1.8(Shield) CN1.9(Shield) CN1.10(EXP) D1.D2(GND) R21.1 R261.1 T1.2(E) U1.2(GND)
U5V: R2.1
MICROAB_N: CN1.2(DM) D1.D1(D-in) R3.1
MICROAB_P: CN1.3(DP) D1.C1(D+in) R4.1
PA11: D1.D3(D-out) R3.2 ; port USBOTG_DM
PA12: D1.C3(D+out) R4.2 ; port USBOTG_DP
NetC15_1: C15.1 CN1.1(VBUS) D1.B3(Vbus) R1.1 R2.2 U1.1(OUT) ; port USBOTG_VBUS, port USBOTG_PRDY
NetCN1_4: CN1.4(ID) D1.A3(ID) R5.1
NetCN11_6: R5.2 ; port USBOTG_ID
NetJP19_1: JP19.1(COMMON) ; port USBOTG_PPWR
NetJP19_2: JP19.2(NO) R21.2 U1.4(EN)
NetLD5_1: LD5.1(A) R6.2
NetLD5_2: LD5.2(K) T1.3(C)
NetLD6_1: LD6.1(A) R9.2
NetLD6_2: LD6.2(K) R8.2 U1.3(~{FAULT}) ; port USBOTG_OVRCR
NetR1_2: R1.2 R261.2 T1.1(B)

Not connected (* = marked no-connect by the designer): D1 A2(Dz) B1(Pd1) B2(Pup) C2(Pd2)

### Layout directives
differential pair: MICROAB_N, MICROAB_P

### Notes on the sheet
- PB12
- (near JP19) PC6
- PA9
- (near R5) PA11
- (near R5) PA12
- PB13
- (near R5) PA10
- VBUS OK
- (near T1) transistor pins numbers follow
  SOT23 JEDEC standard,
- USB Full Speed operating range voltage: 3.0V<VDDUSB<3.6V

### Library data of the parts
C15 = CAP: as C58 on sheet MCU2
CN1 = 475900001: Ordered by: Subcon; ECCN_US/EU: NA; Comments: USB Micro AB receptacle
D1 = EMIF02-USB03F2: Ordered by: ST; ECCN_US/EU: EAR99/NEC; Ref St: 9179037
JP19 = JP2: Ordered by: Subcon; ECCN_US/EU: NA
LD5 LD6 = LED2: as LD9 on sheet ST_LINK
R1 R6 R8 R9 R261 = res1: as R35 on sheet MCU2
R2-R5 R21 = Res1: as R33 on sheet MCU2
T1 = 9013-SOT23: as T4 on sheet ST_LINK
U1 = STMPS2141STR: Ordered by: ST; ECCN_US/EU: EAR99/NEC; Ref St: 9159009

## Sheet Touch Sensing.SchDoc: Touch Sensing
size A4; DocumentNumber: MB1144; Revision: C-02; SheetNumber: 17; SheetTotal: 25; Project: STM32L476G-EVAL

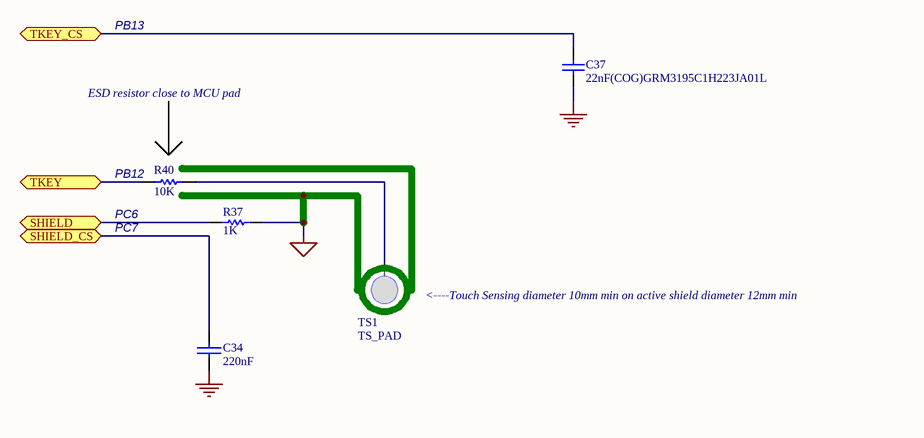
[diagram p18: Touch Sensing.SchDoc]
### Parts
C34  220nF  [0603C]
C37  22nF(COG)GRM3195C1H223JA01L  [1206C]
R37  1K  [0402R]
R40  10K  [0402R]
TS1  TS_PAD  [TS_PAD]

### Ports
SHIELD, SHIELD_CS, TKEY, TKEY_CS

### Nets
GND: C34.1 C37.1
TS_SHIELD: R37.2
NetC34_2: C34.2 ; port SHIELD_CS
NetC37_2: C37.2 ; port TKEY_CS
NetR37_1: R37.1 ; port SHIELD
NetR39_1: R40.1 ; port TKEY
NetR40_2: R40.2 TS1.1

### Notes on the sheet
- PB13
- ESD resistor close to MCU pad
- (near R40) PB12
- (near R40) PC6
- (near R40) PC7
- (near TS1) <----Touch Sensing diameter 10mm min on active shield diameter 12mm min

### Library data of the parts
C34 = CAP: as C54-C57 on sheet MCU2
C37 = CAP: as C141 on sheet MCU2
R37 = Res1: as R268 on sheet ST_LINK
R40 = Res1: as R33 on sheet MCU2
TS1 = TS_PAD: Ordered by: Subcon; ECCN_US/EU: NA; Assembly: with transparent plastic cover; Comments: touch sensing button

## Sheet CAN.SchDoc: CAN
size A4; DocumentNumber: MB1144; Revision: C-02; SheetNumber: 16; SheetTotal: 25; Project: STM32L476G-EVAL

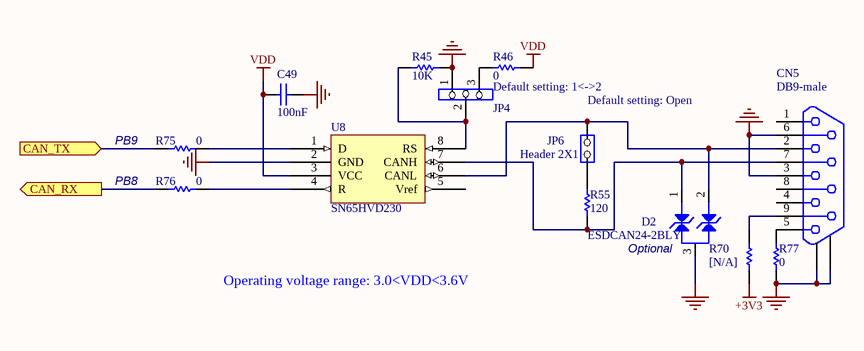
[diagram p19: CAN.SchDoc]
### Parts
C49  100nF  [0402C]
CN5  DB9-male  [DB9/M]
D2  ESDCAN24-2BLY  [SOT23-213]
JP4  Header 3X1  [SIP3]  (value not drawn)
JP6  Header 2X1  [SIP2]
R45  10K  [0402R]
R46  0  [0603R]
R55  120  [0402R]
R70  [N/A]  [0603R]
R75  0  [0603R]
R76  0  [0603R]
R77  0  [0603R]
U8  SN65HVD230  [SOIC8_1R27_4R9X6]

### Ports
CAN_RX (out), CAN_TX (in)

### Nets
+3V3: R70.1
GND: C49.1 CN5.3 CN5.6 CN5.10 CN5.11 D2.3 JP4.1 R45.2 R77.1 U8.2(GND)
VDD: C49.2 R46.2 U8.3(VCC)
NetCN5_2: CN5.2 D2.2 JP6.2(NO) U8.6(CANL)
NetCN5_5: CN5.5 R77.2
NetCN5_7: CN5.7 D2.1 R55.1 U8.7(CANH)
NetCN5_9: CN5.9 R70.2
NetCN11_8: R75.2 ; port CAN_TX
NetCN11_24: R76.1 ; port CAN_RX
NetJP4_2: JP4.2 R45.1 U8.8(RS)
NetJP4_3: JP4.3 R46.1
NetJP6_1: JP6.1(COMMON) R55.2
NetR75_1: R75.1 U8.1(D)
NetR76_2: R76.2 U8.4(R)

Not connected (* = marked no-connect by the designer): CN5 1 4 8; U8 5(Vref)

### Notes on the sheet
- Default setting: 1<->2
- (near JP6) Default setting: Open
- PB9
- PB8
- (near D2) Optional
- Operating voltage range: 3.0<VDD<3.6V

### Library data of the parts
C49 = CAP: as C54-C57 on sheet MCU2
CN5 = DB9: Ordered by: Subcon; Comments: DB9 CAN; ECCN_US/EU: NA
D2 = ESDCAN24-2BLY: Ordered by: ST; ECCN_US/EU: EAR99/NEC; Ref St: 9179002
JP4 = Jumper3: Ordered by: Subcon; ECCN_US/EU: NA
JP6 = JP2: Ordered by: Subcon; ECCN_US/EU: NA
R45 R46 R55 R77 = res1: as R35 on sheet MCU2
R70 = res1: as R96 on sheet MCU2
R75 R76 = Res1: as R33 on sheet MCU2
U8 = SN65HVD230D: Manuf_1: TI; Ordered by: Subcon; ECCN_US/EU: EAR99/NEC; Comments: QSPI memory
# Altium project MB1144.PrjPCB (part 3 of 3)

## Sheet peripherals.SchDoc: peripherals
size A3; DocumentNumber: MB1144; Revision: C-02; SheetNumber: 15; SheetTotal: 25; PageSetup: Record=PageOptions|CenterHorizontal=True|CenterVertical=True|PrintScale=1.39|XCorrection=1.00|YCorrection=1.00|PrintKind=1|BorderSize=5000000|LeftOffset=0|BottomOffset=0|Orientation=2|PaperLength=1000|PaperWidth=1000|Scale=100|PaperSource=264|PrintQuality=600|MediaType=1|DitherType=10|PaperKind=A3|PrintScaleMode=1; Project: STM32L476G-EVAL

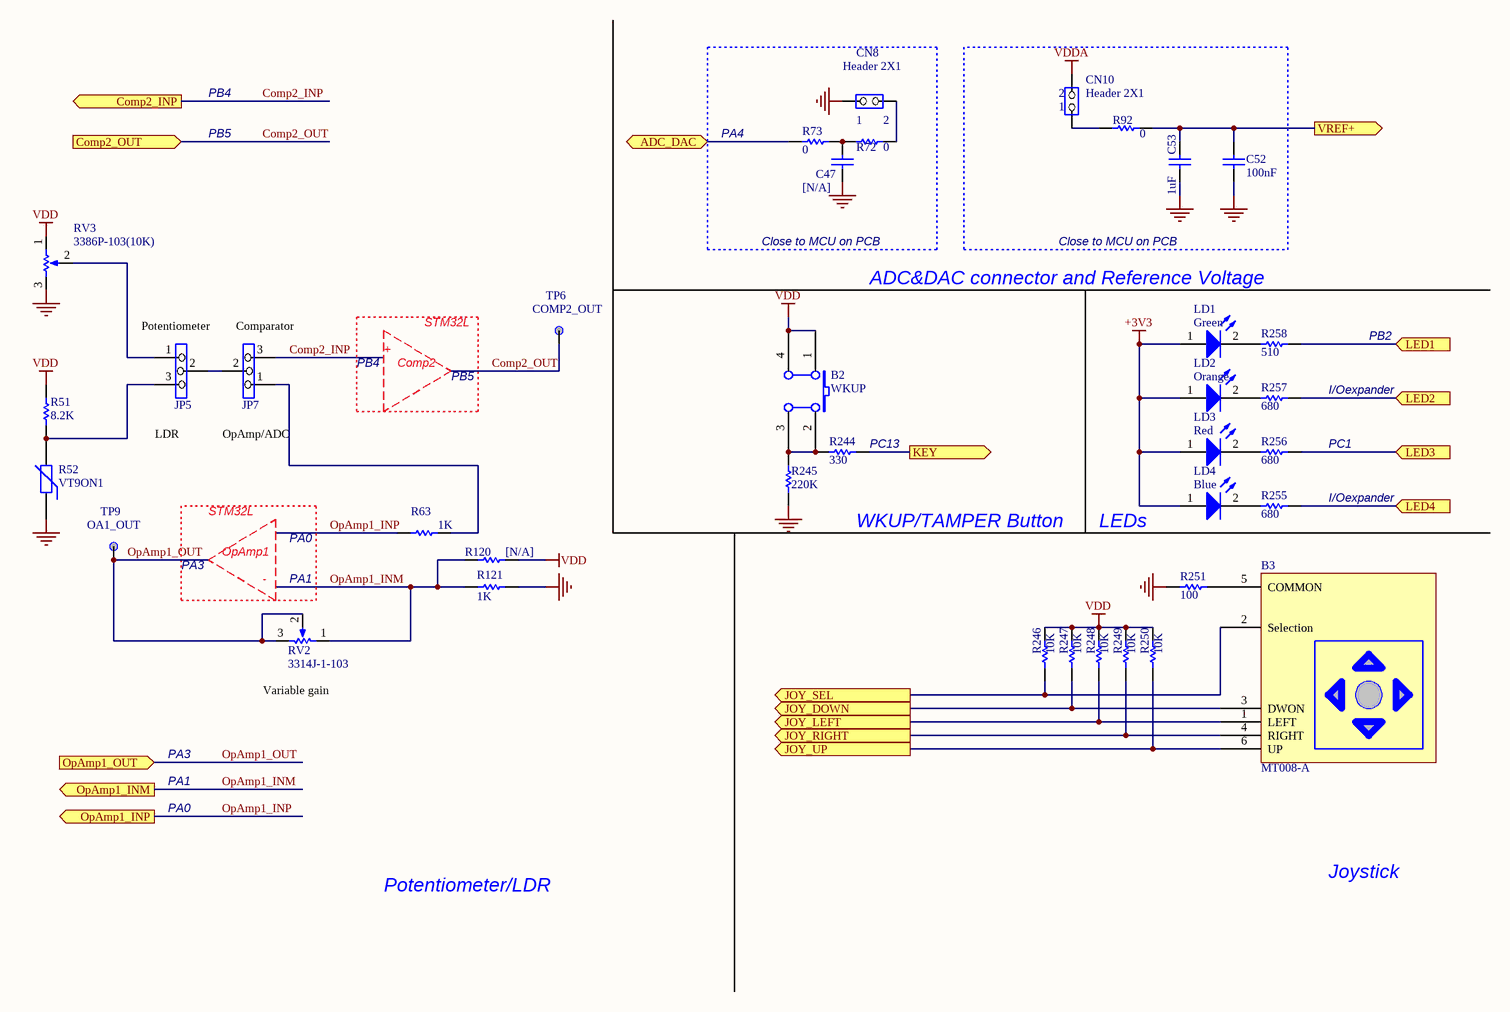
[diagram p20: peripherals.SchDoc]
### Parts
B2  WKUP  [PB10]
B3  MT008-A  [MT-008A]
C47  [N/A]  [0603C]
C52  100nF  [0402C]
C53  1uF  [0603C]
CN8  Header 2X1  [SIP2]
CN10  Header 2X1  [SIP2]
JP5  Header 3X1  [SIP3]  (value not drawn)
JP7  Header 3X1  [SIP3]  (value not drawn)
LD1  Green  [0603D]
LD2  Orange  [0603D]
LD3  Red  [0603D]
LD4  Blue  [0603D]
R51  8.2K  [0402R]
R52  VT9ON1  [PVT901]
R63  1K  [0402R]
R72  0  [0603R]
R73  0  [0603R]
R92  0  [0603R]
R120  [N/A]  [0603R]
R121  1K  [0402R]
R244  330  [0402R]
R245  220K  [0402R]
R246  10K  [0402R]
R247  10K  [0402R]
R248  10K  [0402R]
R249  10K  [0402R]
R250  10K  [0402R]
R251  100  [0402R]
R255  680  [0402R]
R256  680  [0402R]
R257  680  [0402R]
R258  510  [0402R]
RV2  3314J-1-103  [PTF_3314J]
RV3  3386P-103(10K)  [3386P]
TP6  TP Name: COMP2_OUT  [TP]  (hidden comment: [N/A])
TP9  TP Name: OA1_OUT  [TP]  (hidden comment: [N/A])

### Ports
ADC_DAC (bidir), Comp2_INP (out), Comp2_OUT (in), JOY_DOWN (out), JOY_LEFT (out), JOY_RIGHT (out), JOY_SEL (out), JOY_UP (out), KEY (out), LED1 (in), LED2 (in), LED3 (in), LED4 (in), OpAmp1_INM (out), OpAmp1_INP (out), OpAmp1_OUT (in), VREF+ (out)

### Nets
+3V3: LD1.1(A) LD2.1(A) LD3.1(A) LD4.1(A)
GND: C47.1 C52.1 C53.2 CN8.1(COMMON) R52.1 R121.1 R245.2 R251.1 RV3.3(TOP)
VDD: B2.1(A0) B2.4(A1) R51.2 R120.2 R246.1 R247.2 R248.2 R249.2 R250.2 RV3.1(BOT)
VDDA: CN10.2(NO)
Comp2_INP: JP7.3 ; port Comp2_INP
Comp2_OUT: TP6.1 ; port Comp2_OUT
OpAmp1_INM: R120.1 R121.2 RV2.1(BOT) ; port OpAmp1_INM
OpAmp1_INP: R63.2 ; port OpAmp1_INP
OpAmp1_OUT: RV2.2(TAP) RV2.3(TOP) TP9.1 ; port OpAmp1_OUT
PA4: R73.1 ; port ADC_DAC
PC13: R244.2 ; port KEY
NetB2_2: B2.2(B0) B2.3(B1) R244.1 R245.1
NetB3_1: B3.1(LEFT) R248.1 ; port JOY_LEFT
NetB3_2: B3.2(Selection) R246.2 ; port JOY_SEL
NetB3_3: B3.3(DWON) R247.1 ; port JOY_DOWN
NetB3_4: B3.4(RIGHT) R249.1 ; port JOY_RIGHT
NetB3_5: B3.5(COMMON) R251.2
NetB3_6: B3.6(UP) R250.1 ; port JOY_UP
NetC47_2: C47.2 R72.1 R73.2
NetC52_2: C52.2 C53.1 R92.2 ; port VREF+
NetCN8_2: CN8.2(NO) R72.2
NetCN10_1: CN10.1(COMMON) R92.1
NetCN11_30: R256.1 ; port LED3
NetJP5_1: JP5.1 RV3.2(TAP)
NetJP5_2: JP5.2 JP7.2
NetJP5_3: JP5.3 R51.1 R52.2
NetJP7_1: JP7.1 R63.1
NetLD1_2: LD1.2(K) R258.2
NetLD2_2: LD2.2(K) R257.2
NetLD3_2: LD3.2(K) R256.2
NetLD4_2: LD4.2(K) R255.2
NetR54_2: R258.1 ; port LED1
NetR255_1: R255.1 ; port LED4
NetR257_1: R257.1 ; port LED2

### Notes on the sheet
- PB4
- (near CN10) 2
- PB5
- PA4
- 1
- 2
- (near CN10) 1
- Close to MCU on PCB
- ADC&DAC connector and Reference Voltage
- Potentiometer
- (near JP7) Comparator
- +
- Comp2
- STM32L
- PB2
- LDR
- OpAmp/ADC
- I/Oexpander
- (near R244) PC13
- PC1
- PA3
- OpAmp1
- PA0
- WKUP/TAMPER Button
- LEDs
- (near RV2) -
- (near RV2) PA1
- (near RV2) Variable gain
- PA1
- Potentiometer/LDR
- Joystick

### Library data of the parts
B2 = SW PUSHBUTTON: SE PUSHBUTTON; Ordered by: Subcon; Assembly: Blue; ECCN_US/EU: NA
B3 = MT-008A: Ordered by: Subcon; Assembly: with button; ECCN_US/EU: NA
C47 = cap: Capacitor; Value: 100pF; Ordered by: Subcon; ECCN_US/EU: NA; Fitted: NO
C52 = Cap: Capacitor; Value: 10nF; Ordered by: Subcon; ECCN_US/EU: NA
C53 = CAP: Capacitor; Value: 100nF; Ordered by: Subcon; ECCN_US/EU: NA
CN8 CN10 = JP2: Ordered by: Subcon; ECCN_US/EU: NA
JP5 JP7 = Jumper3: Ordered by: Subcon; ECCN_US/EU: NA
LD1-LD4 = LED2: Typical RED, GREEN, YELLOW, AMBER GaAs LED; Ordered by: Subcon; ECCN_US/EU: NA
R51 R72 R73 R92 R244 R246-R251 R255-R258 = Res1: Resistor; Value: 1K; Ordered by: Subcon; ECCN_US/EU: NA
R52 = Res Varistor: Varistor (Voltage-Sensitive Resistor); ECCN_US/EU: NA; Ordered by: Subcon
R63 R121 = Res1: Resistor; Ordered by: Subcon; ECCN_US/EU: NA
R120 = Res1: Resistor; Value: 1K; Ordered by: Subcon; ECCN_US/EU: NA; Fitted: NO
R245 = res1: Resistor; Value: 1K; Ordered by: Subcon; ECCN_US/EU: NA
RV2 = RV: Potentiometer 10K; Ordered by: Subcon; Comments: adjustable 10K potentiometer; ECCN_US/EU: NA
RV3 = RV: Potentiometer 10K; Ordered by: Subcon; Comments: 10K potentiometer; ECCN_US/EU: NA
TP6 TP9 = TP: Ordered by: Subcon; Fitted or not fitted: NO; ECCN_US/EU: NA; Fitted: NO

## Sheet Power.SchDoc: Power
size A3; DocumentNumber: MB1144; Revision: C-02; SheetNumber: 7; SheetTotal: 25; Project: STM32L476G-EVAL

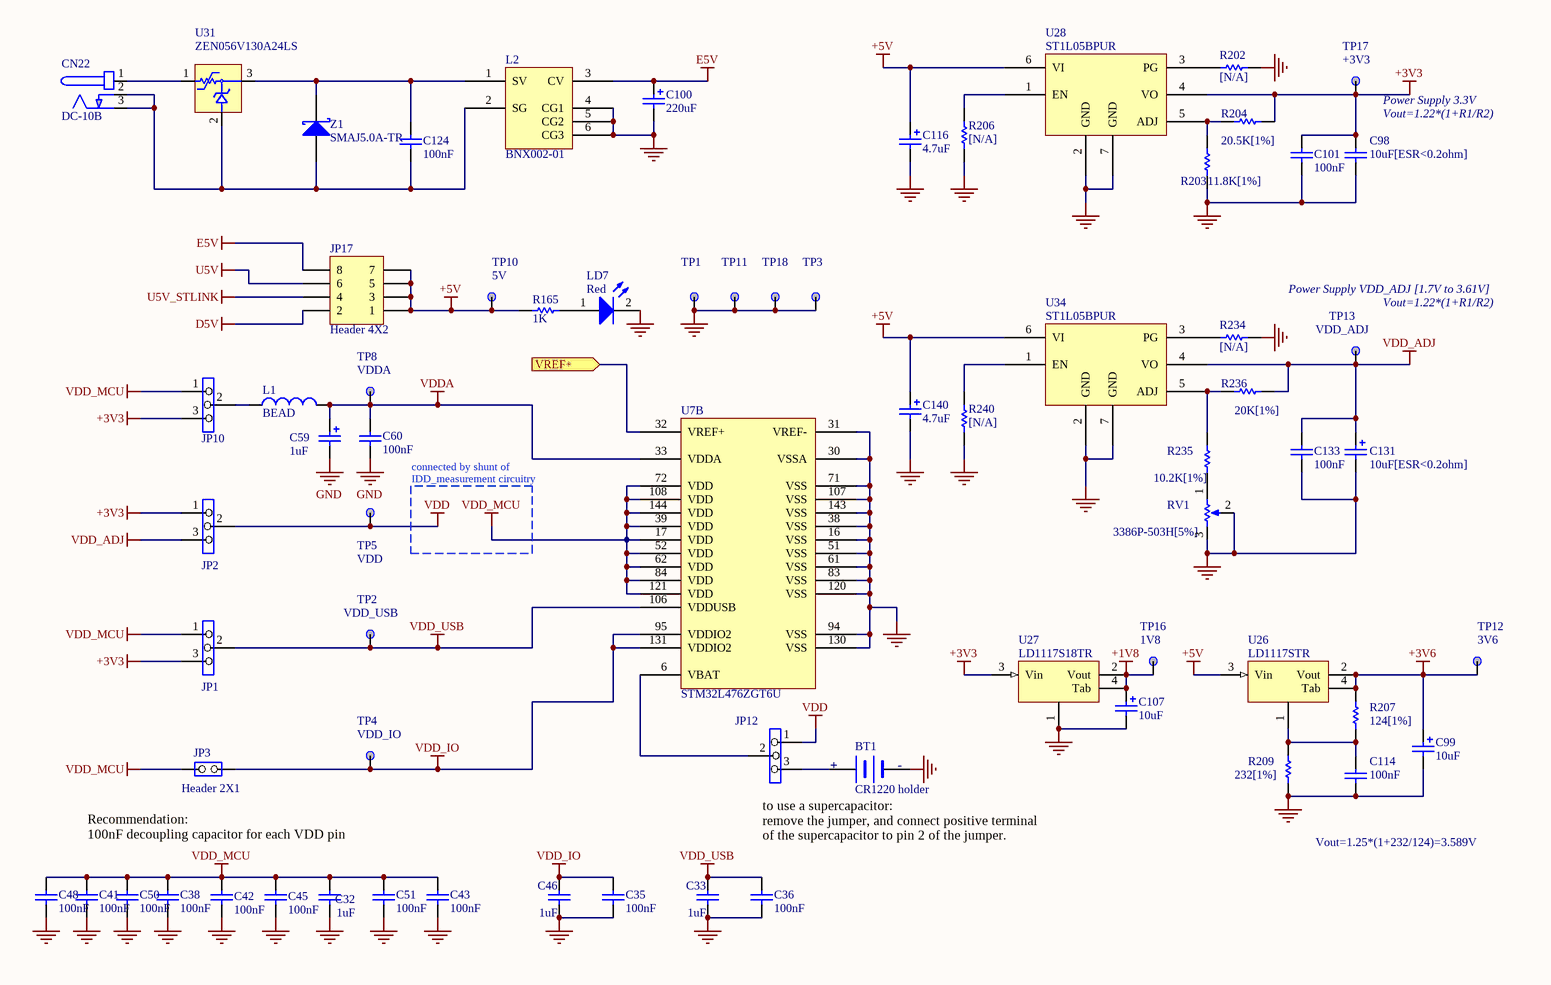
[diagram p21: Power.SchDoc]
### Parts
BT1  CR1220 holder  [BAT_2SM_CR1220]
C32  1uF  [0603C]
C33  1uF  [0603C]
C35  100nF  [0402C]
C36  100nF  [0402C]
C38  100nF  [0402C]
C41  100nF  [0402C]
C42  100nF  [0402C]
C43  100nF  [0402C]
C45  100nF  [0402C]
C46  1uF  [0603C]
C48  100nF  [0402C]
C50  100nF  [0402C]
C51  100nF  [0402C]
C59  1uF  [TAN-A]
C60  100nF  [0402C]
C98  10uF[ESR<0.2ohm]  [0805C]
C99  10uF  [TAN-A]
C100  220uF  [c310m-6]
C101  100nF  [0402C]
C107  10uF  [TAN-A]
C114  100nF  [0402C]
C116  4.7uF  [TAN-A]
C124  100nF  [0402C]
C131  10uF[ESR<0.2ohm]  [0805C]
C133  100nF  [0402C]
C140  4.7uF  [TAN-A]
CN22  DC-10B  [PWR_JACK_DC10]
JP1  Header 3X1  [SIP3]  (value not drawn)
JP2  Header 3X1  [SIP3]  (value not drawn)
JP3  Header 2X1  [SIP2]
JP10  Header 3X1  [SIP3]  (value not drawn)
JP12  Header 3X1  [SIP3]  (value not drawn)
JP17  Header 4X2  [HDR_2X4_2R54]
L1  BEAD  [0603L]
L2  BNX002-01  [BNX001]
LD7  Red  [0603D]
R165  1K  [0402R]
R202  [N/A]  [0603R]
R203  11.8K[1%]  [0603R]
R204  20.5K[1%]  [0603R]
R206  [N/A]  [0603R]
R207  124[1%]  [0603R]
R209  232[1%]  [0603R]
R234  [N/A]  [0603R]
R235  10.2K[1%]  [0603R]
R236  20K[1%]  [0603R]
R240  [N/A]  [0603R]
RV1  3386P-503H[5%]  [3386P]
TP1  [N/A]  [TP]  (value not drawn)
TP2  TP Name: VDD_USB  [TP]  (hidden comment: [N/A])
TP3  [N/A]  [TP]  (value not drawn)
TP4  TP Name: VDD_IO  [TP]  (hidden comment: [N/A])
TP5  TP Name: VDD  [TP]  (hidden comment: [N/A])
TP8  TP Name: VDDA  [TP]  (hidden comment: [N/A])
TP10  TP Name: 5V  [TP]  (hidden comment: [N/A])
TP11  [N/A]  [TP]  (value not drawn)
TP12  TP Name: 3V6  [TP]  (hidden comment: [N/A])
TP13  TP Name: VDD_ADJ  [TP]  (hidden comment: [N/A])
TP16  TP Name: 1V8  [TP]  (hidden comment: [N/A])
TP17  TP Name: +3V3  [TP]  (hidden comment: [N/A])
TP18  [N/A]  [TP]  (value not drawn)
U7  STM32L476ZGT6U  [TQFP144_0R5_22X22_SOCKET]  (part B of 3)
U26  LD1117STR  [SOT-223]
U27  LD1117S18TR  [SOT-223]
U28  ST1L05BPUR  [DFN6_0R95_3X3]
U31  ZEN056V130A24LS  [TYCO_ZEN056V130A24LS]
U34  ST1L05BPUR  [DFN6_0R95_3X3]
Z1  SMAJ5.0A-TR  [sma]

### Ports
VREF+ (in)

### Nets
+1V8: C107.1 TP16.1 U27.2(Vout) U27.4(Tab)
+3V3: C98.1 C101.1 JP1.3 JP2.1 JP10.3 R204.1 TP17.1 U27.3(Vin) U28.4(VO)
+3V6: C99.1 R207.2 TP12.1 U26.2(Vout) U26.4(Tab)
+5V: C116.1 C140.1 JP17.1 JP17.3 JP17.5 JP17.7 R165.2 TP10.1 U26.3(Vin) U28.6(VI) U34.6(VI)
D5V: JP17.2
E5V: C100.1 JP17.8 L2.3(CV)
GND: BT1.2(-) C32.2 C33.2 C35.1 C36.1 C38.1 C41.1 C42.2 C43.1 C45.2 C46.2 C48.1 C50.1 C51.1 C59.2 C60.1 C98.2 C99.2 C100.2 C101.2 C107.2 C114.2 C116.2 C131.2 C133.2 C140.2 L2.4(CG1) L2.5(CG2) L2.6(CG3) LD7.2(K) R202.1 R203.2 R206.2 R209.1 R234.1 R240.2 RV1.2(TAP) RV1.3(TOP) TP1.1 TP3.1 TP11.1 TP18.1 U7.16(VSS) U7.30(VSSA) U7.31(VREF-) U7.38(VSS) U7.51(VSS) U7.61(VSS) U7.71(VSS) U7.83(VSS) U7.94(VSS) U7.107(VSS) U7.120(VSS) U7.130(VSS) U7.143(VSS) U27.1 U28.2(GND) U28.7(GND) U34.2(GND) U34.7(GND)
U5V: JP17.6
U5V_STLINK: JP17.4
VDD: JP2.2 JP12.1 TP5.1
VDD_ADJ: C131.1 C133.1 JP2.3 R236.1 TP13.1 U34.4(VO)
VDD_IO: C35.2 C46.1 JP3.2(NO) TP4.1 U7.95(VDDIO2) U7.131(VDDIO2)
VDD_MCU: C32.1 C38.2 C41.2 C42.1 C43.2 C45.1 C48.2 C50.2 C51.2 JP1.1 JP3.1(COMMON) JP10.1 U7.17(VDD) U7.39(VDD) U7.52(VDD) U7.62(VDD) U7.72(VDD) U7.84(VDD) U7.108(VDD) U7.121(VDD) U7.144(VDD)
VDD_USB: C33.1 C36.2 JP1.2 TP2.1 U7.106(VDDUSB)
VDDA: C59.1 C60.2 L1.2 TP8.1 U7.33(VDDA)
NetBT1_1: BT1.1(+) JP12.3
NetC52_2: U7.32(VREF+) ; port VREF+
NetC114_1: C114.1 R207.1 R209.2 U26.1
NetC124_1: C124.1 L2.1(SV) U31.3 Z1.2(K)
NetC124_2: C124.2 CN22.2(GND) CN22.3(GND) L2.2(SG) U31.2 Z1.1(A)
NetCN22_1: CN22.1(+) U31.1
NetJP10_2: JP10.2 L1.1
NetJP12_2: JP12.2 U7.6(VBAT)
NetLD7_1: LD7.1(A) R165.1
NetR202_2: R202.2 U28.3(PG)
NetR203_1: R203.1 R204.2 U28.5(ADJ)
NetR206_1: R206.1 U28.1(EN)
NetR234_2: R234.2 U34.3(PG)
NetR235_1: R235.1 R236.2 U34.5(ADJ)
NetR235_2: R235.2 RV1.1(BOT)
NetR240_1: R240.1 U34.1(EN)

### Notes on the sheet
- Power Supply 3.3V
- Vout=1.22*(1+R1/R2)
- Power Supply VDD_ADJ [1.7V to 3.61V]
- (near TP13) Vout=1.22*(1+R1/R2)
- connected by shunt of
  IDD_measurement circuitry
- (near BT1) +
- (near BT1) -
- Recommendation:
  100nF decoupling capacitor for each VDD pin
- to use a supercapacitor:
  remove the jumper, and connect positive terminal
  of the supercapacitor to pin 2 of the jumper.
- Vout=1.25*(1+232/124)=3.589V

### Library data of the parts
BT1 = BATTERY: Ordered by: Subcon; Assembly: with battery; ECCN_US/EU: NA
C32 C33 C46 = CAP: as C53 on sheet peripherals
C35 C36 C60 C98 C101 C114 C133 = Cap: as C52 on sheet peripherals
C38 C41-C43 C45 C48 C50 C51 = CAP: Capacitor; Ordered by: Subcon; ECCN_US/EU: NA
C59 C131 = Cap Pol1: Polarized Capacitor (Radial); Value: 10uF; Ordered by: Subcon; ECCN_US/EU: NA
C99 = Cap Pol1: Polarized Capacitor (Radial); ECCN_US/EU: NA; Ordered by: Subcon
C100 = Cap Pol1: Polarized Capacitor (Radial); Value: 47uF; Ordered by: Subcon; ECCN_US/EU: NA
C107 = Cap Pol1: Polarized Capacitor (Radial); Ordered by: Subcon; ECCN_US/EU: NA
C116 C140 = Cap Pol1: Polarized Capacitor (Radial); Value: 100pF; Ordered by: Subcon; ECCN_US/EU: NA
C124 = CAP: Capacitor; Value: 100pF; Ordered by: Subcon; ECCN_US/EU: NA
CN22 = PJ202A: Ordered by: Subcon; Comments: power jack; ECCN_US/EU: NA
JP1 JP2 JP10 JP12 = Jumper3: Ordered by: Subcon; ECCN_US/EU: NA
JP3 = JP2: Ordered by: Subcon; ECCN_US/EU: NA
JP17 = Header 4X2: Header, 4-Pin, Dual row; Ordered by: Subcon; ECCN_US/EU: NA
L1 = Inductor: Value: 100uH; Ordered by: Subcon; ECCN_US/EU: NA
L2 = BNX002: Ordered by: Subcon; ECCN_US/EU: NA
LD7 = LED2: as LD1-LD4 on sheet peripherals
R165 = res1: Resistor; Ordered by: Subcon; ECCN_US/EU: NA
R202 R206 R234 R240 = res1: Resistor; Value: 1K; Ordered by: Subcon; ECCN_US/EU: NA; Fitted: NO
R203 R204 R235 R236 = Res1: as R51 on sheet peripherals
R207 R209 = Res1: Resistor; Value: 1K; ECCN_US/EU: NA; Ordered by: Subcon
RV1 = RV: Potentiometer 50K; Ordered by: Subcon; Comments: 50K potentiometer; ECCN_US/EU: NA
TP1 TP3 TP11 TP18 = TP: TP Name: GND; Ordered by: Subcon; Fitted or not fitted: NO; ECCN_US/EU: NA; Fitted: NO
TP2 TP4 TP5 TP8 TP10 TP12 TP13 TP16 TP17 = TP: as TP6 on sheet peripherals
U7 = STM32L476_TQFP144: Manuf_Part_1: STM32L476ZGT6U cut1.3; Ordered by: ST; ECCN_US/EU: 3A991A2/NEC; Assembly: MCU; Ref St: 9175195
U26 = LD1117: Ordered by: ST; ECCN_US/EU: EAR99/NEC; Ref St: 9176138
U27 = LD1117: Ordered by: ST; ECCN_US/EU: EAR99/NEC; Ref St: 9176180
U28 U34 = ST1L05: Ordered by: ST; ECCN_US/EU: EAR99/NEC; Ref St: 9176239
U31 = ZEN056V130A24LS: Manuf_1: TYCO; Ordered by: Subcon; ECCN_US/EU: EAR99/NEC
Z1 = D Schottky: Schottky Diode; Code - JEDEC: DO-214-AA; Ordered by: ST; ECCN_US/EU: EAR99/NEC; Ref St: 9151107

## Sheet Audio.SchDoc: Audio
size A3; DocumentNumber: MB1144; Revision: C-02; SheetNumber: 20; SheetTotal: 25; Project: STM32L476G-EVAL

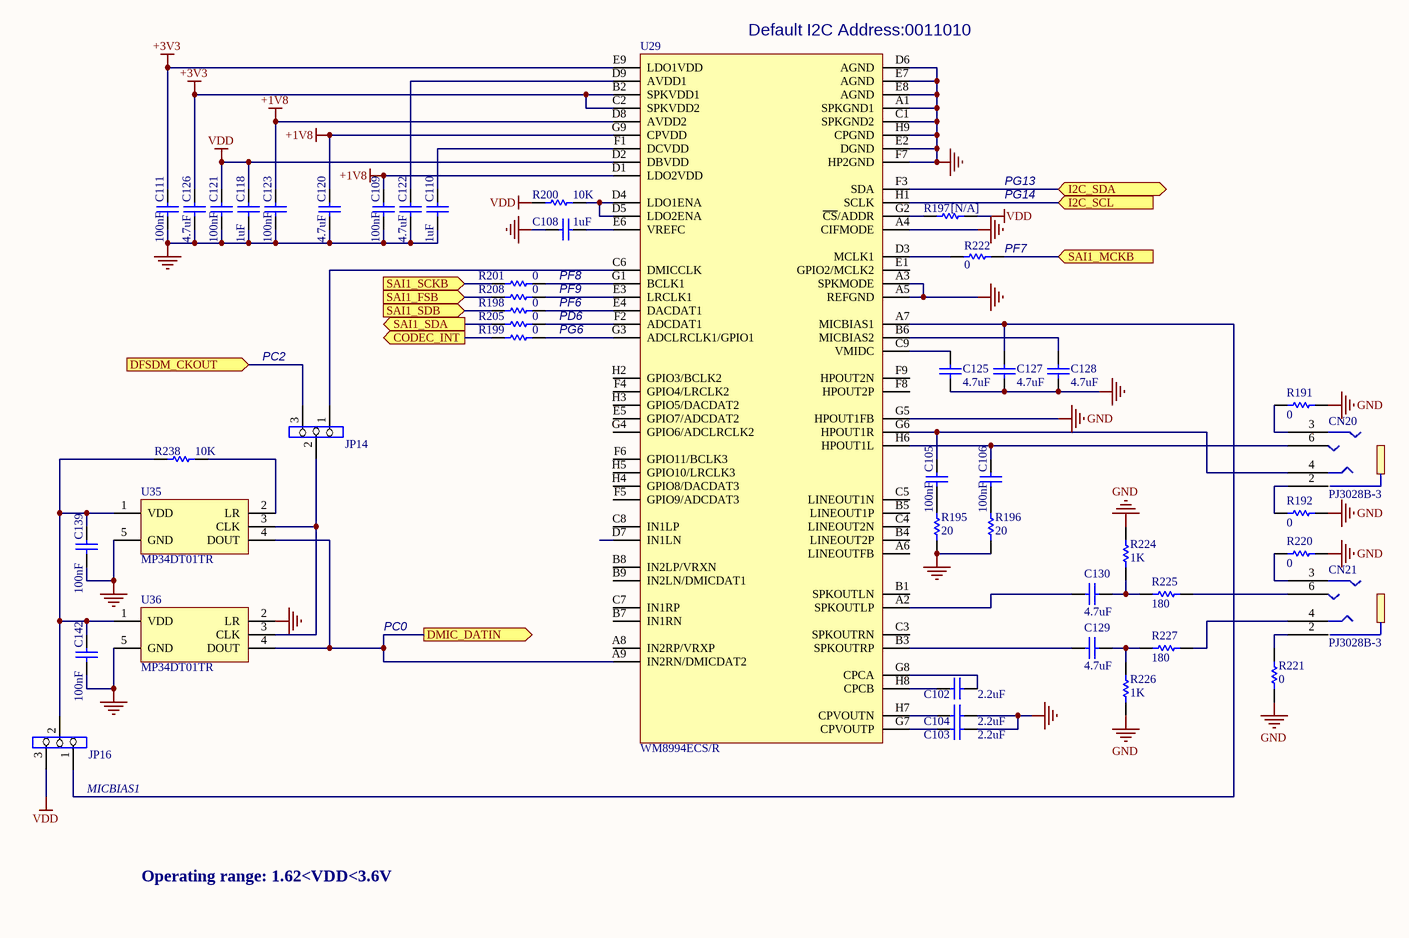
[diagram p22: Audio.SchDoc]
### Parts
C102  2.2uF  [0603C]
C103  2.2uF  [0603C]
C104  2.2uF  [0603C]
C105  100nF  [0402C]
C106  100nF  [0402C]
C108  1uF  [0603C]
C109  100nF  [0402C]
C110  1uF  [0603C]
C111  100nF  [0402C]
C118  1uF  [0603C]
C120  4.7uF  [0603C]
C121  100nF  [0402C]
C122  4.7uF  [0603C]
C123  100nF  [0402C]
C125  4.7uF  [0603C]
C126  4.7uF  [0603C]
C127  4.7uF  [0603C]
C128  4.7uF  [0603C]
C129  4.7uF  [0603C]
C130  4.7uF  [0603C]
C139  100nF  [0402C]
C142  100nF  [0402C]
CN20  PJ3028B-3  [PJ3028B]
CN21  PJ3028B-3  [PJ3028B]
JP14  Header 3X1  [SIP3]  (value not drawn)
JP16  Header 3X1  [SIP3]  (value not drawn)
R191  0  [0603R]
R192  0  [0603R]
R195  20  [0402R]
R196  20  [0402R]
R197  [N/A]  [0603R]
R198  0  [0603R]
R199  0  [0603R]
R200  10K  [0402R]
R201  0  [0603R]
R205  0  [0603R]
R208  0  [0603R]
R220  0  [0603R]
R221  0  [0603R]
R222  0  [0603R]
R224  1K  [0402R]
R225  180  [0402R]
R226  1K  [0402R]
R227  180  [0402R]
R238  10K  [0402R]
U29  WM8994ECS/R  [BGA72_0R5_4R5X4]
U35  MP34DT01TR  [MP34DT01TR]
U36  MP34DT01TR  [MP34DT01TR]

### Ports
CODEC_INT (out), DFSDM_CKOUT (in), DMIC_DATIN (out), I2C_SCL (in), I2C_SDA (bidir), SAI1_FSB (in), SAI1_MCKB (in), SAI1_SCKB (in), SAI1_SDA (out), SAI1_SDB (in)

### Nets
+1V8: C109.1 C120.1 C123.1 U29.D1(LDO2VDD) U29.D8(AVDD2) U29.G9(CPVDD)
+3V3: C111.1 C126.1 U29.B2(SPKVDD1) U29.C2(SPKVDD2) U29.E9(LDO1VDD)
GND: C103.2 C104.2 C108.2 C109.2 C110.2 C111.2 C118.2 C120.2 C121.2 C122.2 C123.2 C125.1 C126.2 C127.1 C128.1 C139.2 C142.2 R191.2 R192.1 R195.2 R196.2 R220.2 R221.2 R224.1 R226.1 U29.A1(SPKGND1) U29.A3(SPKMODE) U29.A4(CIFMODE) U29.A5(REFGND) U29.C1(SPKGND2) U29.D6(AGND) U29.E2(DGND) U29.E7(AGND) U29.E8(AGND) U29.F7(HP2GND) U29.G5(HPOUT1FB) U29.H9(CPGND) U35.5(GND) U36.2(LR) U36.5(GND)
VDD: C118.1 C121.1 JP16.3 R197.1 R200.2 U29.D2(DBVDD)
I2C_SCL: U29.H1(SCLK) ; port I2C_SCL
I2C_SDA: U29.F3(SDA) ; port I2C_SDA
NetC102_1: C102.1 U29.H8(CPCB)
NetC102_2: C102.2 U29.G8(CPCA)
NetC103_1: C103.1 U29.G7(CPVOUTP)
NetC104_1: C104.1 U29.H7(CPVOUTN)
NetC105_1: C105.1 CN20.4 U29.G6(HPOUT1R)
NetC105_2: C105.2 R195.1
NetC106_1: C106.1 CN20.6 U29.H6(HPOUT1L)
NetC106_2: C106.2 R196.1
NetC108_1: C108.1 U29.E6(VREFC)
NetC110_1: C110.1 U29.F1(DCVDD)
NetC122_1: C122.1 U29.D9(AVDD1)
NetC125_2: C125.2 U29.C9(VMIDC)
NetC127_2: C127.2 JP16.1 U29.A7(MICBIAS1)
NetC128_2: C128.2 U29.B6(MICBIAS2)
NetC129_1: C129.1 R226.2 R227.2
NetC129_2: C129.2 U29.B3(SPKOUTRP)
NetC130_1: C130.1 R224.2 R225.1
NetC130_2: C130.2 U29.A2(SPKOUTLP)
NetC139_1: C139.1 C142.1 JP16.2 R238.2 U35.1(VDD) U36.1(VDD)
NetCN11_28: JP14.3 ; port DFSDM_CKOUT
NetCN11_32: U29.A9(IN2RN/DMICDAT2) U35.4(DOUT) U36.4(DOUT) ; port DMIC_DATIN
NetCN20_2: CN20.2 R192.2
NetCN20_3: CN20.3 R191.1
NetCN21_2: CN21.2 R221.1
NetCN21_3: CN21.3 R220.1
NetCN21_4: CN21.4 R227.1
NetCN21_6: CN21.6 R225.2
NetJP14_1: JP14.1 U29.C6(DMICCLK)
NetJP14_2: JP14.2 U35.3(CLK) U36.3(CLK)
NetR35_1: R199.2 ; port CODEC_INT
NetR53_2: R205.2 ; port SAI1_SDA
NetR89_1: R201.2 ; port SAI1_SCKB
NetR90_1: R208.2 ; port SAI1_FSB
NetR105_1: R198.2 ; port SAI1_SDB
NetR106_1: R222.1 ; port SAI1_MCKB
NetR197_2: R197.2 U29.G2(~{CS}/ADDR)
NetR198_1: R198.1 U29.E4(DACDAT1)
NetR199_1: R199.1 U29.G3(ADCLRCLK1/GPIO1)
NetR200_1: R200.1 U29.D4(LDO1ENA) U29.D5(LDO2ENA)
NetR201_1: R201.1 U29.G1(BCLK1)
NetR205_1: R205.1 U29.F2(ADCDAT1)
NetR208_1: R208.1 U29.E3(LRCLK1)
NetR222_2: R222.2 U29.D3(MCLK1)
NetR238_1: R238.1 U35.2(LR)

Not connected (* = marked no-connect by the designer): U29 A6(LINEOUTFB) A8(IN2RP/VRXP) B1(SPKOUTLN) B4(LINEOUT2P) B5(LINEOUT1P) B7(IN1RN) B8(IN2LP/VRXN) B9(IN2LN/DMICDAT1) C3(SPKOUTRN) C4(LINEOUT2N) C5(LINEOUT1N) C7(IN1RP) C8(IN1LP) D7(IN1LN) E1(GPIO2/MCLK2) E5(GPIO7/ADCDAT2) F4(GPIO4/LRCLK2) F5(GPIO9/ADCDAT3) F6(GPIO11/BCLK3) F8(HPOUT2P) F9(HPOUT2N) G4(GPIO6/ADCLRCLK2) H2(GPIO3/BCLK2) H3(GPIO5/DACDAT2) H4(GPIO8/DACDAT3) H5(GPIO10/LRCLK3)

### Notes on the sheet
- (near U29) Default I2C Address:0011010
- PG13
- PG14
- PF8
- PF9
- (near R222) PF7
- PC2
- PD6
- PF6
- PG6
- PC0
- (near JP16) MICBIAS1
- Operating range: 1.62<VDD<3.6V

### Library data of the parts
C102-C104 C108 C110 C118 = CAP: as C53 on sheet peripherals
C105 C106 C109 C111 C120-C123 C125-C130 C139 C142 = Cap: as C52 on sheet peripherals
CN20 CN21 = PJ3028B-3: ECCN_US/EU: NA; Ordered by: Subcon; Comments: Audio jack
JP14 JP16 = Jumper3: Ordered by: Subcon; ECCN_US/EU: NA
R191 R192 R195 R196 R198-R201 R205 R208 R220-R222 R225 R227 R238 = Res1: as R51 on sheet peripherals
R197 = Res1: as R120 on sheet peripherals
R224 R226 = Res1: as R63 on sheet peripherals
U29 = WM8994ECS/R: Manuf_1: Wolfson; Ordered by: Subcon; ECCN_US/EU: EAR99/NEC
U35 U36 = MP34DT01TR: MEMS audio sensor; Ordered by: ST; ECCN_US/EU: EAR99/NEC; Ref St: 9188008

## Sheet LCD_TFT.SchDoc: LCD_TFT
size A3; DocumentNumber: MB1144; Revision: C-02; SheetNumber: 11; SheetTotal: 25; PageSetup: Record=PageOptions|CenterHorizontal=True|CenterVertical=True|PrintScale=1.01|XCorrection=1.00|YCorrection=1.00|PrintKind=1|BorderSize=5000000|LeftOffset=0|BottomOffset=0|Orientation=2|PaperLength=1000|PaperWidth=1000|Scale=100|PaperSource=15|PrintQuality=600|MediaType=1|DitherType=10|PaperKind=A3|PrintScaleMode=1; Project: STM32L476G-EVAL

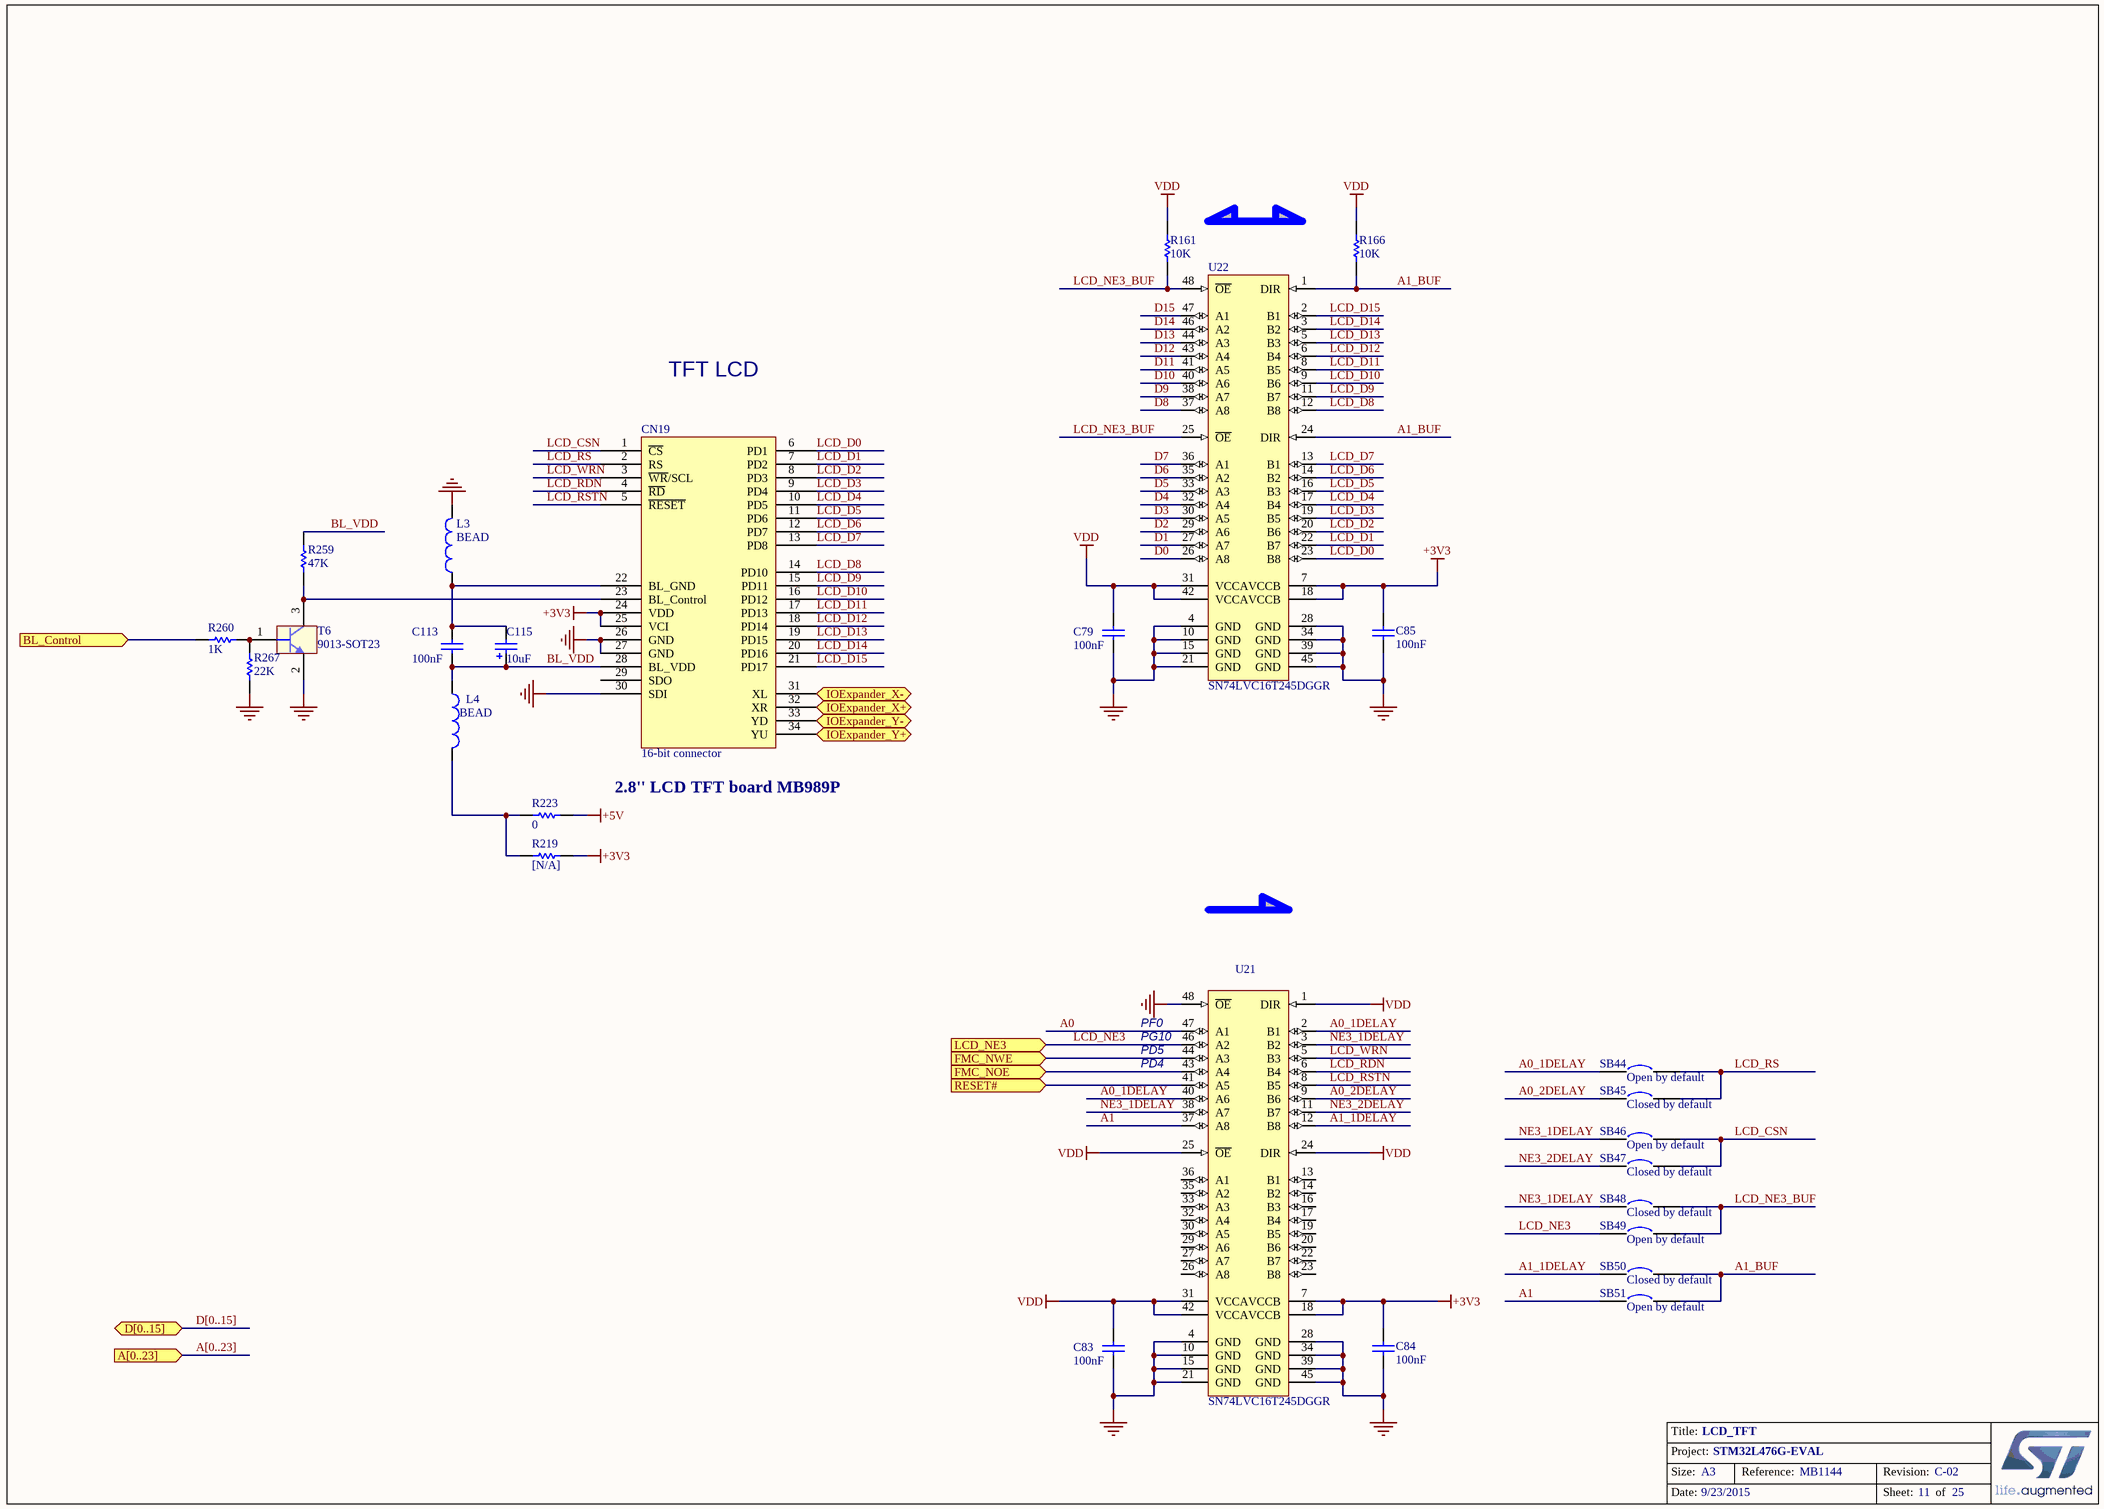
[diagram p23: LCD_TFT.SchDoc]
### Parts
C79  100nF  [0402C]
C83  100nF  [0402C]
C84  100nF  [0402C]
C85  100nF  [0402C]
C113  100nF  [0402C]
C115  10uF  [TAN-A]
CN19  16-bit connector  [HDR_2X17_2R54]
L3  BEAD  [0603L]
L4  BEAD  [0603L]
R161  10K  [0402R]
R166  10K  [0402R]
R219  [N/A]  [0603R]
R223  0  [0603R]
R259  47K  [0402R]
R260  1K  [0402R]
R267  22K  [0402R]
SB44  Open by default  [SB_0603]
SB45  Closed by default  [SB_0603]
SB46  Open by default  [SB_0603]
SB47  Closed by default  [SB_0603]
SB48  Closed by default  [SB_0603]
SB49  Open by default  [SB_0603]
SB50  Closed by default  [SB_0603]
SB51  Open by default  [SB_0603]
T6  9013-SOT23  [SOT-23]
U21  SN74LVC16T245DGGR  [TSSOP48_0R5_12R5X8R1]
U22  SN74LVC16T245DGGR  [TSSOP48_0R5_12R5X8R1]

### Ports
A[0..23] (in), BL_Control (in), D[0..15] (bidir), FMC_NOE (in), FMC_NWE (in), IOExpander_X+ (bidir), IOExpander_X- (bidir), IOExpander_Y+ (bidir), IOExpander_Y- (bidir), LCD_NE3 (in), RESET# (in)

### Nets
+3V3: C84.1 C85.1 CN19.24(VDD) CN19.25(VCI) R219.1 U21.7(VCCB) U21.18(VCCB) U22.7(VCCB) U22.18(VCCB)
+5V: R223.1
GND: C79.2 C83.2 C84.2 C85.2 CN19.26(GND) CN19.27(GND) CN19.30(SDI) L3.2 R267.2 T6.2(E) U21.4(GND) U21.10(GND) U21.15(GND) U21.21(GND) U21.28(GND) U21.34(GND) U21.39(GND) U21.45(GND) U21.48(~{OE}) U22.4(GND) U22.10(GND) U22.15(GND) U22.21(GND) U22.28(GND) U22.34(GND) U22.39(GND) U22.45(GND)
VDD: C79.1 C83.1 R161.1 R166.1 U21.1(DIR) U21.24(DIR) U21.25(~{OE}) U21.31(VCCA) U21.42(VCCA) U22.31(VCCA) U22.42(VCCA)
A0: U21.47(A1)
A0_1DELAY: SB44.1 U21.2(B1) U21.40(A6)
A0_2DELAY: SB45.1 U21.9(B6)
A1: SB51.1 U21.37(A8)
A1_1DELAY: SB50.1 U21.12(B8)
A1_BUF: R166.2 SB50.2 SB51.2 U22.1(DIR) U22.24(DIR)
BL_VDD: C113.2 C115.1 CN19.28(BL_VDD) L4.1 R259.1
D0: U22.26(A8)
D1: U22.27(A7)
D2: U22.29(A6)
D3: U22.30(A5)
D4: U22.32(A4)
D5: U22.33(A3)
D6: U22.35(A2)
D7: U22.36(A1)
D8: U22.37(A8)
D9: U22.38(A7)
D10: U22.40(A6)
D11: U22.41(A5)
D12: U22.43(A4)
D13: U22.44(A3)
D14: U22.46(A2)
D15: U22.47(A1)
LCD_CSN: CN19.1(~{CS}) SB46.2 SB47.2
LCD_D0: CN19.6(PD1) U22.23(B8)
LCD_D1: CN19.7(PD2) U22.22(B7)
LCD_D2: CN19.8(PD3) U22.20(B6)
LCD_D3: CN19.9(PD4) U22.19(B5)
LCD_D4: CN19.10(PD5) U22.17(B4)
LCD_D5: CN19.11(PD6) U22.16(B3)
LCD_D6: CN19.12(PD7) U22.14(B2)
LCD_D7: CN19.13(PD8) U22.13(B1)
LCD_D8: CN19.14(PD10) U22.12(B8)
LCD_D9: CN19.15(PD11) U22.11(B7)
LCD_D10: CN19.16(PD12) U22.9(B6)
LCD_D11: CN19.17(PD13) U22.8(B5)
LCD_D12: CN19.18(PD14) U22.6(B4)
LCD_D13: CN19.19(PD15) U22.5(B3)
LCD_D14: CN19.20(PD16) U22.3(B2)
LCD_D15: CN19.21(PD17) U22.2(B1)
LCD_NE3: SB49.1 U21.46(A2) ; port LCD_NE3
LCD_NE3_BUF: R161.2 SB48.2 SB49.2 U22.25(~{OE}) U22.48(~{OE})
LCD_RDN: CN19.4(~{RD}) U21.6(B4)
LCD_RS: CN19.2(RS) SB44.2 SB45.2
LCD_RSTN: CN19.5(~{RESET}) U21.8(B5)
LCD_WRN: CN19.3(~{WR}/SCL) U21.5(B3)
NE3_1DELAY: SB46.1 SB48.1 U21.3(B2) U21.38(A7)
NE3_2DELAY: SB47.1 U21.11(B7)
PD4: U21.43(A4) ; port FMC_NOE
PD5: U21.44(A3) ; port FMC_NWE
RESET#: U21.41(A5) ; port RESET#
NetC113_1: C113.1 C115.2 CN19.22(BL_GND) L3.1
NetCN19_23: CN19.23(BL_Control) R259.2 T6.3(C)
NetCN19_31: CN19.31(XL) ; port IOExpander_X-
NetCN19_32: CN19.32(XR) ; port IOExpander_X+
NetCN19_33: CN19.33(YD) ; port IOExpander_Y-
NetCN19_34: CN19.34(YU) ; port IOExpander_Y+
NetL4_2: L4.2 R219.2 R223.2
NetR260_1: R260.1 ; port BL_Control
NetR260_2: R260.2 R267.1 T6.1(B)

Not connected (* = marked no-connect by the designer): CN19 29(SDO); U21 13(B1) 14(B2) 16(B3) 17(B4) 19(B5) 20(B6) 22(B7) 23(B8) 26(A8) 27(A7) 29(A6) 30(A5) 32(A4) 33(A3) 35(A2) 36(A1)

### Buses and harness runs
bus A[0..23] = port A[0..23]
bus D[0..15] = port D[0..15]

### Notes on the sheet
- TFT LCD
- 2.8'' LCD TFT board MB989P
- (near U21) PG10
- (near U21) PD5
- (near U21) PF0
- (near U21) PD4

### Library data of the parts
C79 C83-C85 = CAP: as C124 on sheet Power
C113 = Cap: as C52 on sheet peripherals
C115 = Cap Pol1: as C107 on sheet Power
CN19 = ColorLCD_module_16bits: Female connector 2x17; Ordered by: Subcon; Comments: LCD TFT paralell; Assembly: with MB989P revB; ECCN_US/EU: NA
L3 L4 = Inductor: as L1 on sheet Power
R161 R166 R267 = res1: as R245 on sheet peripherals
R219 = Res1: as R120 on sheet peripherals
R223 R259 = Res1: as R51 on sheet peripherals
R260 = Res1: as R63 on sheet peripherals
SB44 SB46 SB49 SB51 = Circuit Breaker: Ordered by: Subcon; Comments: Solder bridge; Fitted: NO; ECCN_US/EU: NA
SB45 SB47 SB48 SB50 = Circuit Breaker: Ordered by: Subcon; Comments: Solder bridge; ECCN_US/EU: NA
T6 = 9013-SOT23: NPN Bipolar Transistor; Manuf_1: Taitron; Manuf_Part_1: MMBT9013; Description: NPN Bipolar Transistor, SOT-23 Footprint; Ordered by: Subcon; ECCN_US/EU: EAR99/NEC
U21 U22 = SN74LVC16T245: Manuf_1: TI; Ordered by: Subcon; ECCN_US/EU: EAR99/NEC

## Sheet RF_I2C_EEPROM.SchDoc: RF_I2C_EEPROM
size A4; DocumentNumber: MB1144; Revision: C-02; SheetNumber: 22; SheetTotal: 25; Project: STM32L476G-EVAL

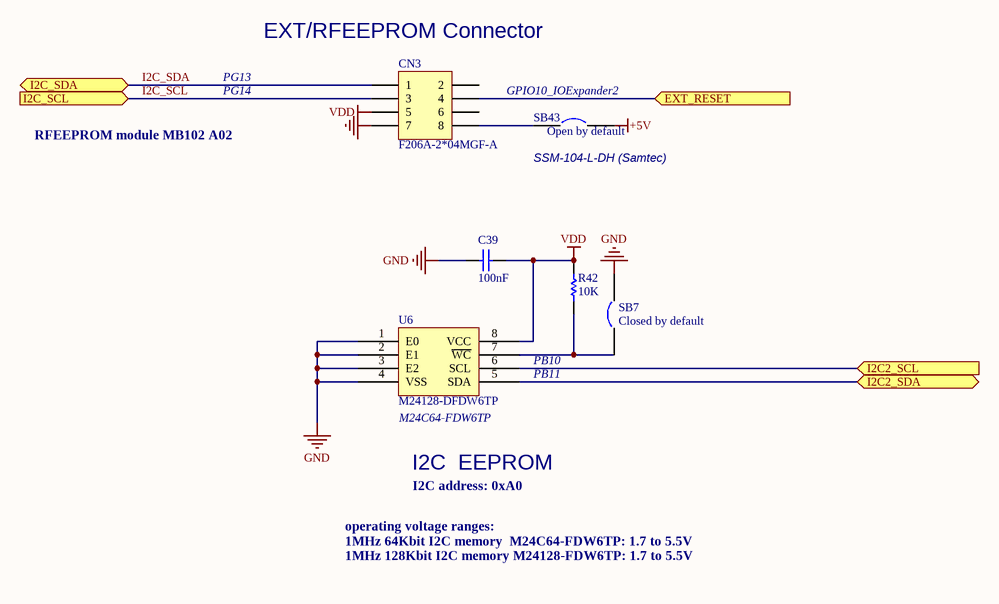
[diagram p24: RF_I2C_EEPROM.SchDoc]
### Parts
C39  100nF  [0402C]
CN3  F206A-2*04MGF-A  [SSM-104-L-DH]
R42  10K  [0402R]
SB7  Closed by default  [SB_0603]
SB43  Open by default  [SB_0603]
U6  M24128-DFDW6TP  [TSSOP8_0R65_3X6R4]

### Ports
EXT_RESET (in), I2C2_SCL (in), I2C2_SDA (bidir), I2C_SCL (in), I2C_SDA (bidir)

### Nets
+5V: SB43.2
GND: C39.1 CN3.7 SB7.2 U6.1(E0) U6.2(E1) U6.3(E2) U6.4(VSS)
VDD: C39.2 CN3.5 R42.1 U6.8(VCC)
I2C_SCL: CN3.3 ; port I2C_SCL
I2C_SDA: CN3.1 ; port I2C_SDA
NetCN3_4: CN3.4 ; port EXT_RESET
NetCN3_8: CN3.8 SB43.1
NetR42_2: R42.2 SB7.1 U6.7(~{WC})
NetR263_2: U6.5(SDA) ; port I2C2_SDA
NetR264_2: U6.6(SCL) ; port I2C2_SCL

Not connected (* = marked no-connect by the designer): CN3 2 6

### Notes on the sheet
- PG13
- (near CN3) EXT/RFEEPROM Connector
- RFEEPROM module MB102 A02
  I2C address: 0xA6
- PG14
- (near SB43) GPIO10_IOExpander2
- SSM-104-L-DH (Samtec)
- PB11
- PB10
- (near U6) M24C64-FDW6TP
- I2C  EEPROM
- I2C address: 0xA0
- operating voltage ranges:
  1MHz 64Kbit I2C memory  M24C64-FDW6TP: 1.7 to 5.5V
  1MHz 128Kbit I2C memory M24128-FDW6TP: 1.7 to 5.5V

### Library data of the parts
C39 = CAP: as C124 on sheet Power
CN3 = SSM-104-L-DH: Header, 5-Pin, Dual row; Ordered by: Subcon; Comments: EXT/RF E2P connector; ECCN_US/EU: NA; Assembly: with MB1020 A02
R42 = Res1: as R51 on sheet peripherals
SB7 = Circuit Breaker: as SB45 on sheet LCD_TFT
SB43 = Circuit Breaker: as SB44 on sheet LCD_TFT
U6 = M24C64-WMN6: Ordered by: ST; ECCN_US/EU: EAR99/NEC; Ref St: 9175653

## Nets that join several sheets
+1V8: Power (C107.1 TP16.1 U27.2 U27.4), Audio (6 pins)
+3V3: MotorControl (CN2.28 R14.2 R20.2), Extension connector (R44.1), USART_IrDA (10 pins), SWP_SmartCard_NFC (9 pins), USB_OTG_FS (R6.1 R8.1 R9.1), CAN (R70.1), peripherals (LD1.1 LD2.1 LD3.1 LD4.1), Power (9 pins), Audio (5 pins), LCD_TFT (9 pins)
+3V6: SRAM&Flash (C20.1 U5.G5), Power (5 pins)
+5V: MotorControl (CN2.25), ST_LINK (R169.2), SWP_SmartCard_NFC (C135.1 C138.1 U30.6), IDD_measurement (C75.1 R128.1 U15.4), USB_OTG_FS (U1.5), Power (11 pins), LCD_TFT (R223.1), RF_I2C_EEPROM (SB43.2)
D5V: Extension connector (CN6.28), ST_LINK (D7.1), Power (JP17.2)
E5V: ST_LINK (D5.1), Power (C100.1 JP17.8 L2.3)
GND: MCU (R100.2 R101.2 R102.2), LCD_Glass (R138.2 R139.2), IO_Expandor (10 pins), MCU2 (9 pins), SRAM&Flash (13 pins), MotorControl (26 pins), MicroSD (C90.2 CN18.6 CN18.9), QSPI (C44.2 U9.4), Extension connector (9 pins), JTAG&Trace (24 pins), ST_LINK (38 pins), USART_IrDA (19 pins), SWP_SmartCard_NFC (17 pins), STPMS2&PT100 (20 pins), IDD_measurement (12 pins), USB_OTG_FS (12 pins), Touch Sensing (C34.1 C37.1), CAN (10 pins), peripherals (9 pins), Power (60 pins), Audio (40 pins), LCD_TFT (27 pins), RF_I2C_EEPROM (7 pins)
U5V: ST_LINK (D6.1), USB_OTG_FS (R2.1), Power (JP17.6)
U5V_STLINK: ST_LINK (C143.2 U37.6 U37.7), Power (JP17.4)
VDD: LCD_Glass (R263.1 R264.1), IO_Expandor (9 pins), MCU2 (R57.2 R60.2 R96.2 SW1.1), SRAM&Flash (16 pins), MicroSD (7 pins), QSPI (C44.1 R74.1 U9.8), Extension connector (CN7.40), JTAG&Trace (8 pins), ST_LINK (8 pins), USART_IrDA (5 pins), SWP_SmartCard_NFC (C112.1 C119.1 U30.21), STPMS2&PT100 (5 pins), IDD_measurement (11 pins), CAN (C49.2 R46.2 U8.3), peripherals (10 pins), Power (JP2.2 JP12.1 TP5.1), Audio (6 pins), LCD_TFT (11 pins), RF_I2C_EEPROM (C39.2 CN3.5 R42.1 U6.8)
VDD_MCU: IDD_measurement (JP11.2 JP11.3), Power (21 pins)
VDDA: peripherals (CN10.2), Power (5 pins)
A0: MCU2 (U7.10), SRAM&Flash (U2.A3 U5.E2), Extension connector (CN6.25), LCD_TFT (U21.47)
A1: MCU2 (U7.11), SRAM&Flash (U2.A4 U5.D2), Extension connector (CN6.26), LCD_TFT (SB51.1 U21.37)
A2: MCU2 (U7.12), SRAM&Flash (U2.A5 U5.C2), Extension connector (CN6.32)
A3: MCU2 (U7.13), SRAM&Flash (U2.B3 U5.A2), Extension connector (CN6.34)
A4: MCU2 (U7.14), SRAM&Flash (U2.B4 U5.B2), Extension connector (CN6.37)
A5: MCU2 (U7.15), SRAM&Flash (U2.C3 U5.D3), Extension connector (CN6.38)
A6: MCU2 (U7.50), SRAM&Flash (U2.C4 U5.C3), Extension connector (CN7.17)
A7: MCU2 (U7.53), SRAM&Flash (U2.D4 U5.A3), Extension connector (CN7.18)
A8: MCU2 (U7.54), SRAM&Flash (U2.H2 U5.B6), Extension connector (CN7.16)
A9: MCU2 (U7.55), SRAM&Flash (U2.H3 U5.A6), Extension connector (CN7.14)
A10: MCU2 (U7.56), SRAM&Flash (U2.H4 U5.C6), Extension connector (CN7.12)
A11: MCU2 (U7.57), SRAM&Flash (U2.H5 U5.D6), Extension connector (CN7.11)
A12: MCU2 (U7.87), SRAM&Flash (U2.G3 U5.B7), Extension connector (CN6.13)
A13: MCU2 (U7.88), SRAM&Flash (U2.G4 U5.A7), Extension connector (CN6.12)
A14: MCU2 (U7.89), SRAM&Flash (U2.F3 U5.C7), Extension connector (CN6.14)
A15: MCU2 (U7.90), SRAM&Flash (U2.F4 U5.D7), Extension connector (CN6.10)
A16: LCD_Glass (CN14.30), SRAM&Flash (U2.E4 U5.E7)
A17: LCD_Glass (R151.1), SRAM&Flash (U2.D3 U5.B3)
A18: LCD_Glass (CN14.34), SRAM&Flash (U2.H1 U5.C4)
A19: LCD_Glass (R139.1 R150.1), SRAM&Flash (U2.G2 U5.D5)
A20: MCU (R84.1 R100.1), SRAM&Flash (U2.H6 U5.D4)
A21: MCU (R85.1 R101.1), SRAM&Flash (U2.E3 U5.C5)
A22: MCU (R86.1 R102.1), SRAM&Flash (U5.B8)
A23: LCD_Glass (R138.1 R149.1), SRAM&Flash (U5.C8)
BOOT0: MCU2 (JP8.1 R67.1 U7.138), Extension connector (CN7.20)
Comp2_INP: LCD_Glass (CN11.44), peripherals (JP7.3)
Comp2_OUT: LCD_Glass (CN11.14), peripherals (TP6.1)
D0: LCD_Glass (CN14.36), SRAM&Flash (U2.B6 U5.E3), LCD_TFT (U22.26)
D1: LCD_Glass (CN14.38), SRAM&Flash (U2.C5 U5.H3), LCD_TFT (U22.27)
D2: MCU (U7.114), SRAM&Flash (U2.C6 U5.E4), Extension connector (CN6.17), LCD_TFT (U22.29)
D3: MCU (U7.115), SRAM&Flash (U2.D5 U5.H4), Extension connector (CN6.16), LCD_TFT (U22.30)
D4: MCU (U7.58), SRAM&Flash (U2.E5 U5.H5), Extension connector (CN7.10), LCD_TFT (U22.32)
D5: MCU (U7.59), SRAM&Flash (U2.F5 U5.E5), Extension connector (CN7.9), LCD_TFT (U22.33)
D6: MCU (U7.60), SRAM&Flash (U2.F6 U5.H6), Extension connector (CN7.8), LCD_TFT (U22.35)
D7: MCU (U7.63), SRAM&Flash (U2.G6 U5.E6), Extension connector (CN7.7), LCD_TFT (U22.36)
D8: MCU (U7.64), SRAM&Flash (U2.B1 U5.F3), Extension connector (CN7.6), LCD_TFT (U22.37)
D9: MCU (U7.65), SRAM&Flash (U2.C1 U5.G3), Extension connector (CN7.5), LCD_TFT (U22.38)
D10: MCU (U7.66), SRAM&Flash (U2.C2 U5.F4), Extension connector (CN7.4), LCD_TFT (U22.40)
D11: MCU (U7.67), SRAM&Flash (U2.D2 U5.G4), Extension connector (CN7.3), LCD_TFT (U22.41)
D12: MCU (U7.68), SRAM&Flash (U2.E2 U5.F5), Extension connector (CN7.2), LCD_TFT (U22.43)
D13: LCD_Glass (CN14.24), SRAM&Flash (U2.F2 U5.G6), LCD_TFT (U22.44)
D14: LCD_Glass (CN14.26), SRAM&Flash (U2.F1 U5.F6), LCD_TFT (U22.46)
D15: LCD_Glass (CN14.28), SRAM&Flash (U2.G1 U5.G7), LCD_TFT (U22.47)
I2C_SCL: IO_Expandor (U32.4 U33.19), MCU2 (R60.1 R61.1), Audio (U29.H1), RF_I2C_EEPROM (CN3.3)
I2C_SDA: IO_Expandor (U32.5 U33.20), MCU2 (R57.1 R58.1), Audio (U29.F3), RF_I2C_EEPROM (CN3.1)
LCD_NE3: MCU2 (U7.125), Extension connector (CN6.21), LCD_TFT (SB49.1 U21.46)
LCDCOM0: MCU (U7.100), LCD_Glass (CN11.3)
LCDCOM1: MCU (U7.101), LCD_Glass (CN11.1)
LCDCOM2: MCU (U7.102), LCD_Glass (CN11.5)
LCDCOM3: MCU (U7.140), LCD_Glass (CN11.7)
LCDCOM4: LCD_Glass (CN14.7), MCU2 (U7.111)
LCDCOM5: LCD_Glass (CN14.5), MCU2 (U7.112)
LCDCOM6: LCD_Glass (CN14.3), MCU2 (U7.113)
LCDCOM7: MCU (U7.116), LCD_Glass (CN14.1)
LCDSEG0: MCU (R82.1), LCD_Glass (CN14.47)
LCDSEG1: MCU (R81.1), LCD_Glass (CN11.35)
LCDSEG2: MCU (R78.2), LCD_Glass (CN11.33)
LCDSEG3: MCU (R68.1), LCD_Glass (CN11.41)
LCDSEG4: MCU (R66.1), LCD_Glass (CN11.39)
LCDSEG5: MCU (R62.1), LCD_Glass (CN11.37)
LCDSEG6: MCU (R56.1), LCD_Glass (CN11.47)
LCDSEG7: MCU (U7.133), LCD_Glass (CN11.45), JTAG&Trace (RS1.9), ST_LINK (U24.6)
LCDSEG8: MCU (U7.134), LCD_Glass (CN11.43), JTAG&Trace (RS1.5), ST_LINK (U23.19)
LCDSEG9: MCU (U7.135), LCD_Glass (CN11.13)
LCDSEG10: MCU (R50.1), LCD_Glass (CN11.11)
LCDSEG11: MCU (R48.1), LCD_Glass (CN11.9)
LCDSEG12: MCU (R39.2), LCD_Glass (CN11.19)
LCDSEG13: MCU (R38.1), LCD_Glass (CN11.17)
LCDSEG14: MCU (U7.75), LCD_Glass (CN11.15)
LCDSEG15: MCU (U7.76), LCD_Glass (CN11.25)
LCDSEG16: MCU (U7.139), LCD_Glass (CN11.23)
LCDSEG17: MCU (U7.110), LCD_Glass (CN11.21), JTAG&Trace (RS1.7), ST_LINK (U23.17)
LCDSEG18: LCD_Glass (CN11.31), MCU2 (R97.1)
LCDSEG19: LCD_Glass (CN11.29), MCU2 (R98.1)
LCDSEG20: LCD_Glass (CN11.27), MCU2 (R99.1)
LCDSEG21: MCU (U7.137), LCD_Glass (CN14.9)
LCDSEG22: LCD_Glass (CN14.11), MCU2 (R65.1)
LCDSEG23: LCD_Glass (CN14.13), MCU2 (R64.1)
LCDSEG24: LCD_Glass (CN14.15), MCU2 (R36.1)
LCDSEG25: LCD_Glass (CN14.17), MCU2 (R33.1)
LCDSEG26: LCD_Glass (CN14.19), MCU2 (SB28.2 U7.98)
LCDSEG27: LCD_Glass (CN14.21), MCU2 (SB29.2 U7.99)
LCDSEG28: MCU (U7.77), LCD_Glass (CN14.23)
LCDSEG29: MCU (U7.78), LCD_Glass (CN14.25)
LCDSEG30: MCU (U7.79), LCD_Glass (CN14.27)
LCDSEG31: MCU (U7.80), LCD_Glass (CN14.29)
LCDSEG32: MCU (U7.81), LCD_Glass (CN14.31)
LCDSEG33: MCU (U7.82), LCD_Glass (CN14.33)
LCDSEG34: MCU (U7.85), LCD_Glass (CN14.35)
LCDSEG35: MCU (U7.86), LCD_Glass (CN14.37)
LCDSEG36: MCU (U7.141), LCD_Glass (CN14.39)
LCDSEG37: MCU (U7.142), LCD_Glass (CN14.41)
LCDSEG38: MCU (R103.2), LCD_Glass (CN14.43)
LCDSEG39: MCU (R104.2), LCD_Glass (CN14.45)
NetB3_1: IO_Expandor (U33.3), peripherals (B3.1 R248.1)
NetB3_2: IO_Expandor (U33.1), peripherals (B3.2 R246.2)
NetB3_3: IO_Expandor (U33.2), peripherals (B3.3 R247.1)
NetB3_4: IO_Expandor (U33.4), peripherals (B3.4 R249.1)
NetB3_6: IO_Expandor (U33.5), peripherals (B3.6 R250.1)
NetC1_2: MCU (SB32.1), MotorControl (C1.2 CN2.33)
NetC2_2: MCU (SB31.1), MotorControl (C2.2 CN2.34)
NetC3_1: MCU2 (SB17.1), MotorControl (C3.1 R7.2)
NetC4_2: MCU (SB35.1), MotorControl (C4.2 CN2.31 SB1.2)
NetC5_2: MCU (SB3.1), MotorControl (C5.2 CN2.30 R20.1)
NetC6_2: MCU (SB20.1), MotorControl (C6.2 R12.2)
NetC7_2: MCU2 (SB29.1), MotorControl (C7.2 CN2.1 R14.1)
NetC9_2: MCU2 (SB37.2), MotorControl (C9.2 CN2.29)
NetC10_2: MCU2 (SB42.1), MotorControl (C10.2 R17.1)
NetC11_1: MCU2 (SB16.1), MotorControl (C11.1 R13.2 R19.1)
NetC13_2: MCU2 (SB36.1), MotorControl (C13.2 R10.1)
NetC14_2: MCU2 (SB34.1), MotorControl (C14.2 R11.1)
NetC15_1: LCD_Glass (CN11.2 R108.2), USB_OTG_FS (6 pins)
NetC16_2: MCU2 (SB25.2), MotorControl (C16.2 R15.1)
NetC17_1: MCU (SB22.1), MotorControl (C17.1 R16.2)
NetC34_2: MCU2 (SB4.1), Touch Sensing (C34.2)
NetC37_2: MCU (SB6.1), Touch Sensing (C37.2)
NetC52_2: peripherals (C52.2 C53.1 R92.2), Power (U7.32)
NetC73_1: MCU (R69.2), IDD_measurement (C73.1 R122.2)
NetCN2_3: MCU2 (SB27.1), MotorControl (CN2.3)
NetCN2_5: MCU (SB19.1), MotorControl (CN2.5)
NetCN2_7: MCU2 (SB30.1), MotorControl (CN2.7)
NetCN2_9: MCU (SB15.1), MotorControl (CN2.9)
NetCN2_11: MCU2 (SB28.1), MotorControl (CN2.11)
NetCN2_13: MCU (SB13.1), MotorControl (CN2.13)
NetCN2_21: MCU2 (SB5.2), MotorControl (CN2.21)
NetCN2_23: MCU (SB11.1), MotorControl (CN2.23)
NetCN3_4: IO_Expandor (U33.12), RF_I2C_EEPROM (CN3.4)
NetCN11_4: LCD_Glass (CN11.4), MicroSD (R194.1)
NetCN11_6: LCD_Glass (CN11.6), USB_OTG_FS (R5.2)
NetCN11_8: LCD_Glass (CN11.8), CAN (R75.2)
NetCN11_16: LCD_Glass (CN11.16), SWP_SmartCard_NFC (CN13.4)
NetCN11_18: LCD_Glass (CN11.18 R108.1), SWP_SmartCard_NFC (CN13.6)
NetCN11_20: LCD_Glass (CN11.20 R109.1), SWP_SmartCard_NFC (CN23.6)
NetCN11_24: LCD_Glass (CN11.24), CAN (R76.1)
NetCN11_26: LCD_Glass (CN11.26), SWP_SmartCard_NFC (CN13.5)
NetCN11_28: LCD_Glass (CN11.28), STPMS2&PT100 (6 pins), Audio (JP14.3)
NetCN11_30: LCD_Glass (CN11.30), peripherals (R256.1)
NetCN11_32: LCD_Glass (CN11.32), Audio (U29.A9 U35.4 U36.4)
NetCN12_12: MCU (SB26.2), JTAG&Trace (CN12.12 U18.4)
NetCN12_18: MCU (SB38.2), JTAG&Trace (CN12.18 U19.3)
NetCN12_20: MCU (SB39.2), JTAG&Trace (CN12.20 U19.1)
NetCN13_1: USART_IrDA (JP15.6), SWP_SmartCard_NFC (CN13.1)
NetCN13_2: USART_IrDA (U10.13 U11.3 U12.7), SWP_SmartCard_NFC (CN13.2)
NetCN14_2: LCD_Glass (CN14.2), MicroSD (CN18.3 R178.2)
NetCN14_10: LCD_Glass (CN14.10), USART_IrDA (JP15.1 JP15.3 JP15.5 R158.1)
NetCN14_40: LCD_Glass (CN14.40), SRAM&Flash (U2.A1)
NetCN14_42: LCD_Glass (CN14.42), SRAM&Flash (U2.B2)
NetCN18_1: LCD_Glass (R142.1), MicroSD (CN18.1 R175.2)
NetCN18_2: LCD_Glass (R141.1), MicroSD (CN18.2 R176.2)
NetCN18_5: LCD_Glass (R140.1), MicroSD (CN18.5)
NetCN18_7: LCD_Glass (R147.1), MicroSD (CN18.7 R182.2)
NetCN18_8: LCD_Glass (R148.1), MicroSD (CN18.8 R185.2)
NetCN19_31: IO_Expandor (U32.16), LCD_TFT (CN19.31)
NetCN19_32: IO_Expandor (U32.13), LCD_TFT (CN19.32)
NetCN19_33: IO_Expandor (U32.1), LCD_TFT (CN19.33)
NetCN19_34: IO_Expandor (U32.15), LCD_TFT (CN19.34)
NetD4_2: MCU2 (D4.2), USART_IrDA (R93.1 U10.16)
NetJP19_1: LCD_Glass (R145.1), USB_OTG_FS (JP19.1)
NetLD6_2: LCD_Glass (R109.2), USB_OTG_FS (LD6.2 R8.2 U1.3)
NetR24_1: LCD_Glass (R146.1), STPMS2&PT100 (R24.1)
NetR32_2: MCU (SB10.2), SRAM&Flash (R32.2 U5.A4)
NetR34_1: MCU2 (R34.1), ST_LINK (R189.1), USART_IrDA (R119.2)
NetR35_1: MCU2 (R35.1), Audio (R199.2)
NetR37_1: MCU2 (SB2.1), Touch Sensing (R37.1)
NetR39_1: MCU (R39.1 SB3.2 U7.73), Touch Sensing (R40.1)
NetR53_2: MCU (R53.2), Audio (R205.2)
NetR54_2: MCU (R54.2), peripherals (R258.1)
NetR59_2: MCU2 (R59.2), USART_IrDA (U10.20)
NetR71_2: MCU (SB8.1), QSPI (R71.2)
NetR89_1: MCU2 (R89.1), Audio (R201.2)
NetR90_1: MCU2 (R90.1), Audio (R208.2)
NetR91_1: MCU2 (R91.1), IDD_measurement (R127.2 U14.12)
NetR104_1: MCU (R104.1 U7.2), JTAG&Trace (R154.2)
NetR105_1: MCU2 (R105.1), Audio (R198.2)
NetR106_1: MCU2 (R106.1), Audio (R222.1)
NetR107_1: LCD_Glass (R107.1), SWP_SmartCard_NFC (U30.24)
NetR137_1: LCD_Glass (R144.1), IDD_measurement (5 pins)
NetR143_1: LCD_Glass (R143.1), SWP_SmartCard_NFC (R210.2)
NetR156_2: MCU (SB40.2), JTAG&Trace (R156.2)
NetR213_1: IO_Expandor (U33.10), SWP_SmartCard_NFC (R213.1 U30.23)
NetR214_2: IO_Expandor (U33.6), SWP_SmartCard_NFC (R214.2 U30.20)
NetR215_2: IO_Expandor (U33.7), SWP_SmartCard_NFC (R215.2 U30.19)
NetR241_1: IO_Expandor (U33.8), SWP_SmartCard_NFC (R241.1 U30.3)
NetR255_1: IO_Expandor (U32.11), peripherals (R255.1)
NetR257_1: IO_Expandor (U32.8), peripherals (R257.1)
NetR260_1: IO_Expandor (U33.11), LCD_TFT (R260.1)
NetR263_2: LCD_Glass (R263.2 R265.1), RF_I2C_EEPROM (U6.5)
NetR264_2: LCD_Glass (R264.2 R266.1), RF_I2C_EEPROM (U6.6)
NetSB9_1: MCU (SB9.1), QSPI (U9.6)
NetSB12_1: MCU (SB12.1), QSPI (U9.5)
NetSB14_1: MCU (SB14.1), QSPI (U9.2)
NetSB18_1: MCU (SB18.1), QSPI (U9.3)
NetSB21_1: MCU (SB21.1), QSPI (U9.7)
OpAmp1_INM: LCD_Glass (CN14.48), peripherals (R120.1 R121.2 RV2.1)
OpAmp1_INP: MCU (R83.2), peripherals (R63.2)
OpAmp1_OUT: LCD_Glass (R111.1), peripherals (RV2.2 RV2.3 TP9.1)
PA0: MCU (R83.1 SB35.2 U7.34), Extension connector (CN7.37)
PA4: MCU (U7.40), Extension connector (CN7.38), peripherals (R73.1)
PA5: MCU (R69.1 U7.41), Extension connector (CN7.35)
PA11: MCU (U7.103), Extension connector (CN6.6), USB_OTG_FS (D1.D3 R3.2)
PA12: MCU (U7.104), Extension connector (CN6.7), USB_OTG_FS (D1.C3 R4.2)
PA13: MCU (U7.105), Extension connector (CN6.5), JTAG&Trace (RS1.13), ST_LINK (U23.27 U24.7)
PA14: MCU (U7.109), Extension connector (CN6.8), JTAG&Trace (RS1.11), ST_LINK (U23.15 U23.26)
PB2: MCU (R54.1 SB11.2 U7.48), Extension connector (CN7.13)
PB6: MCU (U7.136), Extension connector (CN6.40), USART_IrDA (R118.2)
PC3: MCU2 (R94.1 U7.29), Extension connector (CN7.36)
PC13: MCU2 (U7.7), Extension connector (R80.2), peripherals (R244.2)
PC14: MCU2 (R87.2 U7.8), Extension connector (SB41.1)
PC15: MCU2 (R88.2 U7.9), Extension connector (SB33.1)
PD3: MCU (U7.117), Extension connector (CN6.15), STPMS2&PT100 (R23.1)
PD4: MCU (U7.118), SRAM&Flash (U2.A2 U5.G2), Extension connector (CN6.18), LCD_TFT (U21.43)
PD5: MCU (U7.119), SRAM&Flash (U2.G5 U5.A5), Extension connector (CN6.19), LCD_TFT (U21.44)
PD6: MCU (R53.1 SB10.1 U7.122), Extension connector (CN6.24)
PD7: MCU (U7.123), SRAM&Flash (R18.2), Extension connector (CN6.23)
PE4: MCU (R84.2 SB40.1 U7.3), Extension connector (CN7.21)
PE5: MCU (R85.2 SB38.1 U7.4), Extension connector (CN7.23)
PE6: MCU (R86.2 SB39.1 U7.5), Extension connector (CN7.22)
PF6: MCU2 (R105.2 U7.18), Extension connector (CN7.27)
PF7: MCU2 (R106.2 U7.19), Extension connector (CN7.28)
PF8: MCU2 (R89.2 U7.20), Extension connector (CN7.30)
PF9: MCU2 (R90.2 SB25.1 U7.21), Extension connector (CN7.29)
PF10: MCU2 (R91.2 SB37.1 U7.22), Extension connector (CN7.31)
PF11: MCU2 (U7.49), Extension connector (CN7.19), SWP_SmartCard_NFC (CN13.3)
PG6: MCU2 (R35.2 SB5.1 U7.91), Extension connector (CN6.3)
PG7: MCU2 (R34.2 U7.92), Extension connector (CN6.4)
PG8: MCU2 (U7.93), Extension connector (CN6.9), ST_LINK (R188.2), USART_IrDA (R158.2)
PG9: MCU2 (U7.124), SRAM&Flash (R43.2), Extension connector (CN6.20)
PG11: MCU2 (U7.126), Extension connector (CN6.27), USART_IrDA (R93.2)
PG12: MCU2 (U7.127), Extension connector (CN6.31), USART_IrDA (R116.2)
PG13: MCU2 (R58.2 U7.128), Extension connector (CN6.29)
PG14: MCU2 (R61.2 U7.129), Extension connector (CN6.33)
PG15: IO_Expandor (R228.1), MCU2 (U7.132), Extension connector (CN6.35)
PH0: MCU2 (C54.1 U7.23 X2.2), Extension connector (SB24.1)
PH1: MCU2 (R95.1 U7.24), Extension connector (SB23.1)
RESET#: MCU2 (6 pins), Extension connector (R79.1), JTAG&Trace (RS1.3), ST_LINK (U23.18), LCD_TFT (U21.41)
